VERSION 5.8 ;
BUSBITCHARS "[]" ;
DIVIDERCHAR "/" ;
UNITS
    DATABASE MICRONS 1000 ;
END UNITS

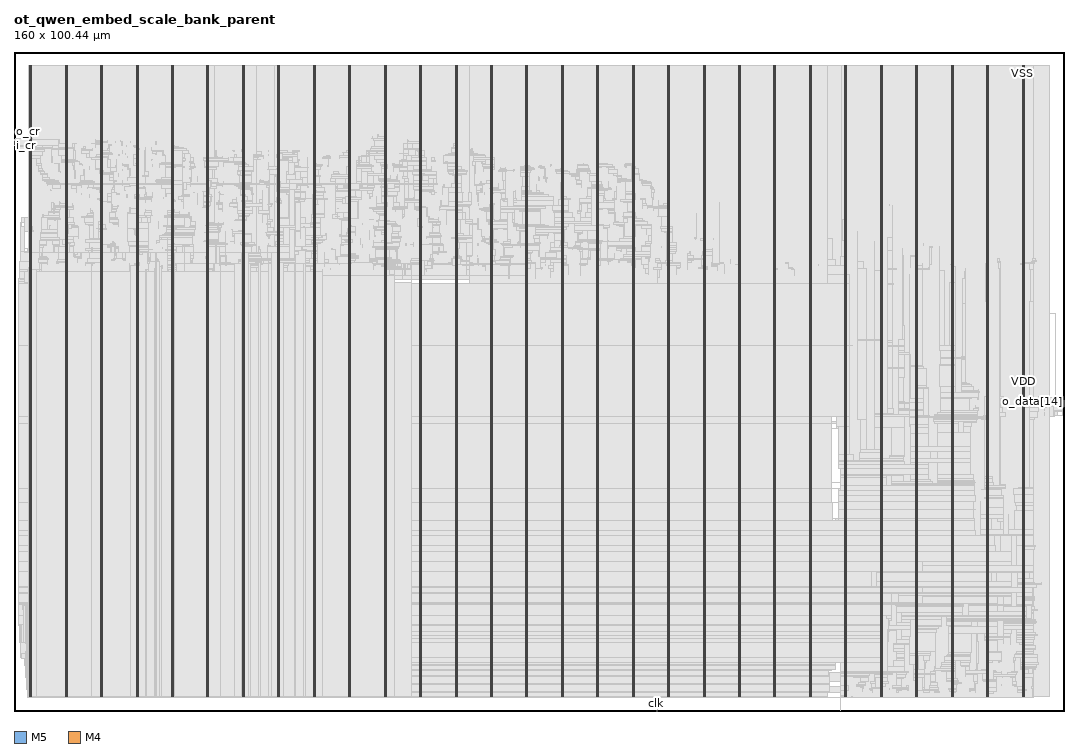
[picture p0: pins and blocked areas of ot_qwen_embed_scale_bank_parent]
MACRO ot_qwen_embed_scale_bank_parent
  FOREIGN ot_qwen_embed_scale_bank_parent 0 0 ;
  CLASS BLOCK ;
  SIZE 160 BY 100.44 ;
  PIN clk
    DIRECTION INPUT ;
    USE SIGNAL ;
    PORT
      LAYER M5 ;
        RECT  97.872 0 97.896 0.084 ;
    END
  END clk
  PIN fault
    DIRECTION OUTPUT ;
    USE SIGNAL ;
    PORT
      LAYER M5 ;
        RECT  97.92 0 97.944 0.084 ;
    END
  END fault
  PIN i_cr
    DIRECTION OUTPUT ;
    USE SIGNAL ;
    PORT
      LAYER M4 ;
        RECT  0 86.112 0.084 86.136 ;
    END
  END i_cr
  PIN i_row[0]
    DIRECTION INPUT ;
    USE SIGNAL ;
    PORT
      LAYER M4 ;
        RECT  0 86.16 0.084 86.184 ;
    END
  END i_row[0]
  PIN i_row[10]
    DIRECTION INPUT ;
    USE SIGNAL ;
    PORT
      LAYER M4 ;
        RECT  0 86.64 0.084 86.664 ;
    END
  END i_row[10]
  PIN i_row[11]
    DIRECTION INPUT ;
    USE SIGNAL ;
    PORT
      LAYER M4 ;
        RECT  0 86.688 0.084 86.712 ;
    END
  END i_row[11]
  PIN i_row[12]
    DIRECTION INPUT ;
    USE SIGNAL ;
    PORT
      LAYER M4 ;
        RECT  0 86.736 0.084 86.76 ;
    END
  END i_row[12]
  PIN i_row[13]
    DIRECTION INPUT ;
    USE SIGNAL ;
    PORT
      LAYER M4 ;
        RECT  0 86.784 0.084 86.808 ;
    END
  END i_row[13]
  PIN i_row[14]
    DIRECTION INPUT ;
    USE SIGNAL ;
    PORT
      LAYER M4 ;
        RECT  0 86.832 0.084 86.856 ;
    END
  END i_row[14]
  PIN i_row[15]
    DIRECTION INPUT ;
    USE SIGNAL ;
    PORT
      LAYER M4 ;
        RECT  0 86.88 0.084 86.904 ;
    END
  END i_row[15]
  PIN i_row[16]
    DIRECTION INPUT ;
    USE SIGNAL ;
    PORT
      LAYER M4 ;
        RECT  0 86.928 0.084 86.952 ;
    END
  END i_row[16]
  PIN i_row[17]
    DIRECTION INPUT ;
    USE SIGNAL ;
    PORT
      LAYER M4 ;
        RECT  0 86.976 0.084 87 ;
    END
  END i_row[17]
  PIN i_row[1]
    DIRECTION INPUT ;
    USE SIGNAL ;
    PORT
      LAYER M4 ;
        RECT  0 86.208 0.084 86.232 ;
    END
  END i_row[1]
  PIN i_row[2]
    DIRECTION INPUT ;
    USE SIGNAL ;
    PORT
      LAYER M4 ;
        RECT  0 86.256 0.084 86.28 ;
    END
  END i_row[2]
  PIN i_row[3]
    DIRECTION INPUT ;
    USE SIGNAL ;
    PORT
      LAYER M4 ;
        RECT  0 86.304 0.084 86.328 ;
    END
  END i_row[3]
  PIN i_row[4]
    DIRECTION INPUT ;
    USE SIGNAL ;
    PORT
      LAYER M4 ;
        RECT  0 86.352 0.084 86.376 ;
    END
  END i_row[4]
  PIN i_row[5]
    DIRECTION INPUT ;
    USE SIGNAL ;
    PORT
      LAYER M4 ;
        RECT  0 86.4 0.084 86.424 ;
    END
  END i_row[5]
  PIN i_row[6]
    DIRECTION INPUT ;
    USE SIGNAL ;
    PORT
      LAYER M4 ;
        RECT  0 86.448 0.084 86.472 ;
    END
  END i_row[6]
  PIN i_row[7]
    DIRECTION INPUT ;
    USE SIGNAL ;
    PORT
      LAYER M4 ;
        RECT  0 86.496 0.084 86.52 ;
    END
  END i_row[7]
  PIN i_row[8]
    DIRECTION INPUT ;
    USE SIGNAL ;
    PORT
      LAYER M4 ;
        RECT  0 86.544 0.084 86.568 ;
    END
  END i_row[8]
  PIN i_row[9]
    DIRECTION INPUT ;
    USE SIGNAL ;
    PORT
      LAYER M4 ;
        RECT  0 86.592 0.084 86.616 ;
    END
  END i_row[9]
  PIN i_v
    DIRECTION INPUT ;
    USE SIGNAL ;
    PORT
      LAYER M4 ;
        RECT  0 87.024 0.084 87.048 ;
    END
  END i_v
  PIN o_cr
    DIRECTION INPUT ;
    USE SIGNAL ;
    PORT
      LAYER M4 ;
        RECT  0 87.072 0.084 87.096 ;
    END
  END o_cr
  PIN o_data[0]
    DIRECTION OUTPUT ;
    USE SIGNAL ;
    PORT
      LAYER M4 ;
        RECT  159.916 46.464 160 46.488 ;
    END
  END o_data[0]
  PIN o_data[10]
    DIRECTION OUTPUT ;
    USE SIGNAL ;
    PORT
      LAYER M4 ;
        RECT  159.916 46.944 160 46.968 ;
    END
  END o_data[10]
  PIN o_data[11]
    DIRECTION OUTPUT ;
    USE SIGNAL ;
    PORT
      LAYER M4 ;
        RECT  159.916 46.992 160 47.016 ;
    END
  END o_data[11]
  PIN o_data[12]
    DIRECTION OUTPUT ;
    USE SIGNAL ;
    PORT
      LAYER M4 ;
        RECT  159.916 47.04 160 47.064 ;
    END
  END o_data[12]
  PIN o_data[13]
    DIRECTION OUTPUT ;
    USE SIGNAL ;
    PORT
      LAYER M4 ;
        RECT  159.916 47.088 160 47.112 ;
    END
  END o_data[13]
  PIN o_data[14]
    DIRECTION OUTPUT ;
    USE SIGNAL ;
    PORT
      LAYER M4 ;
        RECT  159.916 47.136 160 47.16 ;
    END
  END o_data[14]
  PIN o_data[15]
    DIRECTION OUTPUT ;
    USE SIGNAL ;
    PORT
      LAYER M4 ;
        RECT  159.916 47.184 160 47.208 ;
    END
  END o_data[15]
  PIN o_data[1]
    DIRECTION OUTPUT ;
    USE SIGNAL ;
    PORT
      LAYER M4 ;
        RECT  159.916 46.512 160 46.536 ;
    END
  END o_data[1]
  PIN o_data[2]
    DIRECTION OUTPUT ;
    USE SIGNAL ;
    PORT
      LAYER M4 ;
        RECT  159.916 46.56 160 46.584 ;
    END
  END o_data[2]
  PIN o_data[3]
    DIRECTION OUTPUT ;
    USE SIGNAL ;
    PORT
      LAYER M4 ;
        RECT  159.916 46.608 160 46.632 ;
    END
  END o_data[3]
  PIN o_data[4]
    DIRECTION OUTPUT ;
    USE SIGNAL ;
    PORT
      LAYER M4 ;
        RECT  159.916 46.656 160 46.68 ;
    END
  END o_data[4]
  PIN o_data[5]
    DIRECTION OUTPUT ;
    USE SIGNAL ;
    PORT
      LAYER M4 ;
        RECT  159.916 46.704 160 46.728 ;
    END
  END o_data[5]
  PIN o_data[6]
    DIRECTION OUTPUT ;
    USE SIGNAL ;
    PORT
      LAYER M4 ;
        RECT  159.916 46.752 160 46.776 ;
    END
  END o_data[6]
  PIN o_data[7]
    DIRECTION OUTPUT ;
    USE SIGNAL ;
    PORT
      LAYER M4 ;
        RECT  159.916 46.8 160 46.824 ;
    END
  END o_data[7]
  PIN o_data[8]
    DIRECTION OUTPUT ;
    USE SIGNAL ;
    PORT
      LAYER M4 ;
        RECT  159.916 46.848 160 46.872 ;
    END
  END o_data[8]
  PIN o_data[9]
    DIRECTION OUTPUT ;
    USE SIGNAL ;
    PORT
      LAYER M4 ;
        RECT  159.916 46.896 160 46.92 ;
    END
  END o_data[9]
  PIN o_v
    DIRECTION OUTPUT ;
    USE SIGNAL ;
    PORT
      LAYER M4 ;
        RECT  159.916 47.232 160 47.256 ;
    END
  END o_v
  PIN rst_n
    DIRECTION INPUT ;
    USE SIGNAL ;
    PORT
      LAYER M5 ;
        RECT  97.968 0 97.992 0.084 ;
    END
  END rst_n
  PIN VDD
    DIRECTION INOUT ;
    USE POWER ;
    PORT
      LAYER M5 ;
        RECT  153.792 2.151 153.912 98.289 ;
        RECT  148.392 2.151 148.512 98.289 ;
        RECT  142.992 2.151 143.112 98.289 ;
        RECT  137.592 2.151 137.712 98.289 ;
        RECT  132.192 2.151 132.312 98.289 ;
        RECT  126.792 2.151 126.912 98.289 ;
        RECT  121.392 2.151 121.512 98.289 ;
        RECT  115.992 2.151 116.112 98.289 ;
        RECT  110.592 2.151 110.712 98.289 ;
        RECT  105.192 2.151 105.312 98.289 ;
        RECT  99.792 2.151 99.912 98.289 ;
        RECT  94.392 2.151 94.512 98.289 ;
        RECT  88.992 2.151 89.112 98.289 ;
        RECT  83.592 2.151 83.712 98.289 ;
        RECT  78.192 2.151 78.312 98.289 ;
        RECT  72.792 2.151 72.912 98.289 ;
        RECT  67.392 2.151 67.512 98.289 ;
        RECT  61.992 2.151 62.112 98.289 ;
        RECT  56.592 2.151 56.712 98.289 ;
        RECT  51.192 2.151 51.312 98.289 ;
        RECT  45.792 2.151 45.912 98.289 ;
        RECT  40.392 2.151 40.512 98.289 ;
        RECT  34.992 2.151 35.112 98.289 ;
        RECT  29.592 2.151 29.712 98.289 ;
        RECT  24.192 2.151 24.312 98.289 ;
        RECT  18.792 2.151 18.912 98.289 ;
        RECT  13.392 2.151 13.512 98.289 ;
        RECT  7.992 2.151 8.112 98.289 ;
        RECT  2.592 2.151 2.712 98.289 ;
    END
  END VDD
  PIN VSS
    DIRECTION INOUT ;
    USE GROUND ;
    PORT
      LAYER M5 ;
        RECT  153.6 2.137 153.72 98.303 ;
        RECT  148.2 2.137 148.32 98.303 ;
        RECT  142.8 2.137 142.92 98.303 ;
        RECT  137.4 2.137 137.52 98.303 ;
        RECT  132 2.137 132.12 98.303 ;
        RECT  126.6 2.137 126.72 98.303 ;
        RECT  121.2 2.151 121.32 98.303 ;
        RECT  115.8 2.151 115.92 98.303 ;
        RECT  110.4 2.151 110.52 98.303 ;
        RECT  105 2.151 105.12 98.303 ;
        RECT  99.6 2.151 99.72 98.303 ;
        RECT  94.2 2.151 94.32 98.303 ;
        RECT  88.8 2.151 88.92 98.303 ;
        RECT  83.4 2.151 83.52 98.303 ;
        RECT  78 2.151 78.12 98.303 ;
        RECT  72.6 2.151 72.72 98.303 ;
        RECT  67.2 2.151 67.32 98.303 ;
        RECT  61.8 2.151 61.92 98.303 ;
        RECT  56.4 2.151 56.52 98.303 ;
        RECT  51 2.151 51.12 98.303 ;
        RECT  45.6 2.151 45.72 98.303 ;
        RECT  40.2 2.151 40.32 98.303 ;
        RECT  34.8 2.151 34.92 98.303 ;
        RECT  29.4 2.151 29.52 98.303 ;
        RECT  24 2.151 24.12 98.303 ;
        RECT  18.6 2.151 18.72 98.303 ;
        RECT  13.2 2.151 13.32 98.303 ;
        RECT  7.8 2.151 7.92 98.303 ;
        RECT  2.4 2.151 2.52 98.303 ;
    END
  END VSS
  OBS
    LAYER RVTN ;
     RECT  126.036 2.16 157.788 2.295 ;
     RECT  126.036 2.565 157.788 2.835 ;
     RECT  126.036 3.105 157.788 3.375 ;
     RECT  126.036 3.645 157.788 3.915 ;
     RECT  126.036 4.185 157.788 4.455 ;
     RECT  126.036 4.725 157.788 4.995 ;
     RECT  126.036 5.265 157.788 5.535 ;
     RECT  126.036 5.805 157.788 6.075 ;
     RECT  126.036 6.345 157.788 6.615 ;
     RECT  126.036 6.885 157.788 7.155 ;
     RECT  126.036 7.425 157.788 7.695 ;
     RECT  126.036 7.965 157.788 8.235 ;
     RECT  126.036 8.505 157.788 8.775 ;
     RECT  126.036 9.045 157.788 9.315 ;
     RECT  126.036 9.585 157.788 9.855 ;
     RECT  126.036 10.125 157.788 10.395 ;
     RECT  126.036 10.665 157.788 10.935 ;
     RECT  126.036 11.205 157.788 11.475 ;
     RECT  126.036 11.745 157.788 12.015 ;
     RECT  126.036 12.285 157.788 12.555 ;
     RECT  126.036 12.825 157.788 13.095 ;
     RECT  126.036 13.365 157.788 13.635 ;
     RECT  126.036 13.905 157.788 14.175 ;
     RECT  126.036 14.445 157.788 14.715 ;
     RECT  126.036 14.985 157.788 15.255 ;
     RECT  126.036 15.525 157.788 15.795 ;
     RECT  126.036 16.065 157.788 16.335 ;
     RECT  126.036 16.605 157.788 16.875 ;
     RECT  126.036 17.145 157.788 17.415 ;
     RECT  126.036 17.685 157.788 17.955 ;
     RECT  126.036 18.225 157.788 18.495 ;
     RECT  126.036 18.765 157.788 19.035 ;
     RECT  126.036 19.305 157.788 19.575 ;
     RECT  126.036 19.845 157.788 20.115 ;
     RECT  126.036 20.385 157.788 20.655 ;
     RECT  126.036 20.925 157.788 21.195 ;
     RECT  126.036 21.465 157.788 21.735 ;
     RECT  126.036 22.005 157.788 22.275 ;
     RECT  126.036 22.545 157.788 22.815 ;
     RECT  126.036 23.085 157.788 23.355 ;
     RECT  126.036 23.625 157.788 23.895 ;
     RECT  126.036 24.165 157.788 24.435 ;
     RECT  126.036 24.705 157.788 24.975 ;
     RECT  126.036 25.245 157.788 25.515 ;
     RECT  126.036 25.785 157.788 26.055 ;
     RECT  126.036 26.325 157.788 26.595 ;
     RECT  126.036 26.865 157.788 27.135 ;
     RECT  126.036 27.405 157.788 27.675 ;
     RECT  126.036 27.945 157.788 28.215 ;
     RECT  126.036 28.485 157.788 28.755 ;
     RECT  126.036 29.025 157.788 29.295 ;
     RECT  126.036 29.565 157.788 29.835 ;
     RECT  126.036 30.105 157.788 30.375 ;
     RECT  126.036 30.645 157.788 30.915 ;
     RECT  126.036 31.185 157.788 31.455 ;
     RECT  126.036 31.725 157.788 31.995 ;
     RECT  126.036 32.265 157.788 32.535 ;
     RECT  126.036 32.805 157.788 33.075 ;
     RECT  126.036 33.345 157.788 33.615 ;
     RECT  126.036 33.885 157.788 34.155 ;
     RECT  126.036 34.425 157.788 34.695 ;
     RECT  126.036 34.965 157.788 35.235 ;
     RECT  126.036 35.505 157.788 35.775 ;
     RECT  126.036 36.045 157.788 36.315 ;
     RECT  126.036 36.585 157.788 36.855 ;
     RECT  126.036 37.125 157.788 37.395 ;
     RECT  126.036 37.665 157.788 37.935 ;
     RECT  126.036 38.205 157.788 38.475 ;
     RECT  126.036 38.745 157.788 39.015 ;
     RECT  126.036 39.285 157.788 39.555 ;
     RECT  126.036 39.825 157.788 40.095 ;
     RECT  126.036 40.365 157.788 40.635 ;
     RECT  126.036 40.905 157.788 41.175 ;
     RECT  126.036 41.445 157.788 41.715 ;
     RECT  126.036 41.985 157.788 42.255 ;
     RECT  126.036 42.525 157.788 42.795 ;
     RECT  126.036 43.065 157.788 43.335 ;
     RECT  126.036 43.605 157.788 43.875 ;
     RECT  126.036 44.145 157.788 44.415 ;
     RECT  126.036 44.685 157.788 44.955 ;
     RECT  126.036 45.225 157.788 45.495 ;
     RECT  126.036 45.765 157.788 46.035 ;
     RECT  126.036 46.305 157.788 46.575 ;
     RECT  126.036 46.845 157.788 47.115 ;
     RECT  126.036 47.385 157.788 47.655 ;
     RECT  126.036 47.925 157.788 48.195 ;
     RECT  126.036 48.465 157.788 48.735 ;
     RECT  126.036 49.005 157.788 49.275 ;
     RECT  126.036 49.545 157.788 49.815 ;
     RECT  126.036 50.085 157.788 50.355 ;
     RECT  126.036 50.625 157.788 50.895 ;
     RECT  126.036 51.165 157.788 51.435 ;
     RECT  126.036 51.705 157.788 51.975 ;
     RECT  126.036 52.245 157.788 52.515 ;
     RECT  126.036 52.785 157.788 53.055 ;
     RECT  126.036 53.325 157.788 53.595 ;
     RECT  126.036 53.865 157.788 54.135 ;
     RECT  126.036 54.405 157.788 54.675 ;
     RECT  126.036 54.945 157.788 55.215 ;
     RECT  126.036 55.485 157.788 55.755 ;
     RECT  126.036 56.025 157.788 56.295 ;
     RECT  126.036 56.565 157.788 56.835 ;
     RECT  126.036 57.105 157.788 57.375 ;
     RECT  126.036 57.645 157.788 57.915 ;
     RECT  126.036 58.185 157.788 58.455 ;
     RECT  126.036 58.725 157.788 58.995 ;
     RECT  126.036 59.265 157.788 59.535 ;
     RECT  126.036 59.805 157.788 60.075 ;
     RECT  126.036 60.345 157.788 60.615 ;
     RECT  126.036 60.885 157.788 61.155 ;
     RECT  126.036 61.425 157.788 61.695 ;
     RECT  126.036 61.965 157.788 62.235 ;
     RECT  126.036 62.505 157.788 62.775 ;
     RECT  126.036 63.045 157.788 63.315 ;
     RECT  126.036 63.585 157.788 63.855 ;
     RECT  126.036 64.125 157.788 64.395 ;
     RECT  126.036 64.665 157.788 64.935 ;
     RECT  126.036 65.205 157.788 65.475 ;
     RECT  126.036 65.745 157.788 66.015 ;
     RECT  126.036 66.285 157.788 66.555 ;
     RECT  126.036 66.825 157.788 67.095 ;
     RECT  2.16 67.365 157.788 67.635 ;
     RECT  2.16 67.905 157.788 68.175 ;
     RECT  2.16 68.445 157.788 68.715 ;
     RECT  2.16 68.985 157.788 69.255 ;
     RECT  2.16 69.525 157.788 69.795 ;
     RECT  2.16 70.065 157.788 70.335 ;
     RECT  2.16 70.605 157.788 70.875 ;
     RECT  2.16 71.145 157.788 71.415 ;
     RECT  2.16 71.685 157.788 71.955 ;
     RECT  2.16 72.225 157.788 72.495 ;
     RECT  2.16 72.765 157.788 73.035 ;
     RECT  2.16 73.305 157.788 73.575 ;
     RECT  2.16 73.845 157.788 74.115 ;
     RECT  2.16 74.385 157.788 74.655 ;
     RECT  2.16 74.925 157.788 75.195 ;
     RECT  2.16 75.465 157.788 75.735 ;
     RECT  2.16 76.005 157.788 76.275 ;
     RECT  2.16 76.545 157.788 76.815 ;
     RECT  2.16 77.085 157.788 77.355 ;
     RECT  2.16 77.625 157.788 77.895 ;
     RECT  2.16 78.165 157.788 78.435 ;
     RECT  2.16 78.705 157.788 78.975 ;
     RECT  2.16 79.245 157.788 79.515 ;
     RECT  2.16 79.785 157.788 80.055 ;
     RECT  2.16 80.325 157.788 80.595 ;
     RECT  2.16 80.865 157.788 81.135 ;
     RECT  2.16 81.405 157.788 81.675 ;
     RECT  2.16 81.945 157.788 82.215 ;
     RECT  2.16 82.485 157.788 82.755 ;
     RECT  2.16 83.025 157.788 83.295 ;
     RECT  2.16 83.565 157.788 83.835 ;
     RECT  2.16 84.105 157.788 84.375 ;
     RECT  2.16 84.645 157.788 84.915 ;
     RECT  2.16 85.185 157.788 85.455 ;
     RECT  2.16 85.725 157.788 85.995 ;
     RECT  2.16 86.265 157.788 86.535 ;
     RECT  2.16 86.805 157.788 87.075 ;
     RECT  2.16 87.345 157.788 87.615 ;
     RECT  2.16 87.885 157.788 88.155 ;
     RECT  2.16 88.425 157.788 88.695 ;
     RECT  2.16 88.965 157.788 89.235 ;
     RECT  2.16 89.505 157.788 89.775 ;
     RECT  2.16 90.045 157.788 90.315 ;
     RECT  2.16 90.585 157.788 90.855 ;
     RECT  2.16 91.125 157.788 91.395 ;
     RECT  2.16 91.665 157.788 91.935 ;
     RECT  2.16 92.205 157.788 92.475 ;
     RECT  2.16 92.745 157.788 93.015 ;
     RECT  2.16 93.285 157.788 93.555 ;
     RECT  2.16 93.825 157.788 94.095 ;
     RECT  2.16 94.365 157.788 94.635 ;
     RECT  2.16 94.905 157.788 95.175 ;
     RECT  2.16 95.445 157.788 95.715 ;
     RECT  2.16 95.985 157.788 96.255 ;
     RECT  2.16 96.525 157.788 96.795 ;
     RECT  2.16 97.065 157.788 97.335 ;
     RECT  2.16 97.605 157.788 97.875 ;
     RECT  2.16 98.145 157.788 98.28 ;
    LAYER RVTP ;
     RECT  126.036 2.295 157.788 2.565 ;
     RECT  126.036 2.835 157.788 3.105 ;
     RECT  126.036 3.375 157.788 3.645 ;
     RECT  126.036 3.915 157.788 4.185 ;
     RECT  126.036 4.455 157.788 4.725 ;
     RECT  126.036 4.995 157.788 5.265 ;
     RECT  126.036 5.535 157.788 5.805 ;
     RECT  126.036 6.075 157.788 6.345 ;
     RECT  126.036 6.615 157.788 6.885 ;
     RECT  126.036 7.155 157.788 7.425 ;
     RECT  126.036 7.695 157.788 7.965 ;
     RECT  126.036 8.235 157.788 8.505 ;
     RECT  126.036 8.775 157.788 9.045 ;
     RECT  126.036 9.315 157.788 9.585 ;
     RECT  126.036 9.855 157.788 10.125 ;
     RECT  126.036 10.395 157.788 10.665 ;
     RECT  126.036 10.935 157.788 11.205 ;
     RECT  126.036 11.475 157.788 11.745 ;
     RECT  126.036 12.015 157.788 12.285 ;
     RECT  126.036 12.555 157.788 12.825 ;
     RECT  126.036 13.095 157.788 13.365 ;
     RECT  126.036 13.635 157.788 13.905 ;
     RECT  126.036 14.175 157.788 14.445 ;
     RECT  126.036 14.715 157.788 14.985 ;
     RECT  126.036 15.255 157.788 15.525 ;
     RECT  126.036 15.795 157.788 16.065 ;
     RECT  126.036 16.335 157.788 16.605 ;
     RECT  126.036 16.875 157.788 17.145 ;
     RECT  126.036 17.415 157.788 17.685 ;
     RECT  126.036 17.955 157.788 18.225 ;
     RECT  126.036 18.495 157.788 18.765 ;
     RECT  126.036 19.035 157.788 19.305 ;
     RECT  126.036 19.575 157.788 19.845 ;
     RECT  126.036 20.115 157.788 20.385 ;
     RECT  126.036 20.655 157.788 20.925 ;
     RECT  126.036 21.195 157.788 21.465 ;
     RECT  126.036 21.735 157.788 22.005 ;
     RECT  126.036 22.275 157.788 22.545 ;
     RECT  126.036 22.815 157.788 23.085 ;
     RECT  126.036 23.355 157.788 23.625 ;
     RECT  126.036 23.895 157.788 24.165 ;
     RECT  126.036 24.435 157.788 24.705 ;
     RECT  126.036 24.975 157.788 25.245 ;
     RECT  126.036 25.515 157.788 25.785 ;
     RECT  126.036 26.055 157.788 26.325 ;
     RECT  126.036 26.595 157.788 26.865 ;
     RECT  126.036 27.135 157.788 27.405 ;
     RECT  126.036 27.675 157.788 27.945 ;
     RECT  126.036 28.215 157.788 28.485 ;
     RECT  126.036 28.755 157.788 29.025 ;
     RECT  126.036 29.295 157.788 29.565 ;
     RECT  126.036 29.835 157.788 30.105 ;
     RECT  126.036 30.375 157.788 30.645 ;
     RECT  126.036 30.915 157.788 31.185 ;
     RECT  126.036 31.455 157.788 31.725 ;
     RECT  126.036 31.995 157.788 32.265 ;
     RECT  126.036 32.535 157.788 32.805 ;
     RECT  126.036 33.075 157.788 33.345 ;
     RECT  126.036 33.615 157.788 33.885 ;
     RECT  126.036 34.155 157.788 34.425 ;
     RECT  126.036 34.695 157.788 34.965 ;
     RECT  126.036 35.235 157.788 35.505 ;
     RECT  126.036 35.775 157.788 36.045 ;
     RECT  126.036 36.315 157.788 36.585 ;
     RECT  126.036 36.855 157.788 37.125 ;
     RECT  126.036 37.395 157.788 37.665 ;
     RECT  126.036 37.935 157.788 38.205 ;
     RECT  126.036 38.475 157.788 38.745 ;
     RECT  126.036 39.015 157.788 39.285 ;
     RECT  126.036 39.555 157.788 39.825 ;
     RECT  126.036 40.095 157.788 40.365 ;
     RECT  126.036 40.635 157.788 40.905 ;
     RECT  126.036 41.175 157.788 41.445 ;
     RECT  126.036 41.715 157.788 41.985 ;
     RECT  126.036 42.255 157.788 42.525 ;
     RECT  126.036 42.795 157.788 43.065 ;
     RECT  126.036 43.335 157.788 43.605 ;
     RECT  126.036 43.875 157.788 44.145 ;
     RECT  126.036 44.415 157.788 44.685 ;
     RECT  126.036 44.955 157.788 45.225 ;
     RECT  126.036 45.495 157.788 45.765 ;
     RECT  126.036 46.035 157.788 46.305 ;
     RECT  126.036 46.575 157.788 46.845 ;
     RECT  126.036 47.115 157.788 47.385 ;
     RECT  126.036 47.655 157.788 47.925 ;
     RECT  126.036 48.195 157.788 48.465 ;
     RECT  126.036 48.735 157.788 49.005 ;
     RECT  126.036 49.275 157.788 49.545 ;
     RECT  126.036 49.815 157.788 50.085 ;
     RECT  126.036 50.355 157.788 50.625 ;
     RECT  126.036 50.895 157.788 51.165 ;
     RECT  126.036 51.435 157.788 51.705 ;
     RECT  126.036 51.975 157.788 52.245 ;
     RECT  126.036 52.515 157.788 52.785 ;
     RECT  126.036 53.055 157.788 53.325 ;
     RECT  126.036 53.595 157.788 53.865 ;
     RECT  126.036 54.135 157.788 54.405 ;
     RECT  126.036 54.675 157.788 54.945 ;
     RECT  126.036 55.215 157.788 55.485 ;
     RECT  126.036 55.755 157.788 56.025 ;
     RECT  126.036 56.295 157.788 56.565 ;
     RECT  126.036 56.835 157.788 57.105 ;
     RECT  126.036 57.375 157.788 57.645 ;
     RECT  126.036 57.915 157.788 58.185 ;
     RECT  126.036 58.455 157.788 58.725 ;
     RECT  126.036 58.995 157.788 59.265 ;
     RECT  126.036 59.535 157.788 59.805 ;
     RECT  126.036 60.075 157.788 60.345 ;
     RECT  126.036 60.615 157.788 60.885 ;
     RECT  126.036 61.155 157.788 61.425 ;
     RECT  126.036 61.695 157.788 61.965 ;
     RECT  126.036 62.235 157.788 62.505 ;
     RECT  126.036 62.775 157.788 63.045 ;
     RECT  126.036 63.315 157.788 63.585 ;
     RECT  126.036 63.855 157.788 64.125 ;
     RECT  126.036 64.395 157.788 64.665 ;
     RECT  126.036 64.935 157.788 65.205 ;
     RECT  126.036 65.475 157.788 65.745 ;
     RECT  126.036 66.015 157.788 66.285 ;
     RECT  126.036 66.555 157.788 66.825 ;
     RECT  126.036 67.095 157.788 67.23 ;
     RECT  2.16 67.23 157.788 67.365 ;
     RECT  2.16 67.635 157.788 67.905 ;
     RECT  2.16 68.175 157.788 68.445 ;
     RECT  2.16 68.715 157.788 68.985 ;
     RECT  2.16 69.255 157.788 69.525 ;
     RECT  2.16 69.795 157.788 70.065 ;
     RECT  2.16 70.335 157.788 70.605 ;
     RECT  2.16 70.875 157.788 71.145 ;
     RECT  2.16 71.415 157.788 71.685 ;
     RECT  2.16 71.955 157.788 72.225 ;
     RECT  2.16 72.495 157.788 72.765 ;
     RECT  2.16 73.035 157.788 73.305 ;
     RECT  2.16 73.575 157.788 73.845 ;
     RECT  2.16 74.115 157.788 74.385 ;
     RECT  2.16 74.655 157.788 74.925 ;
     RECT  2.16 75.195 157.788 75.465 ;
     RECT  2.16 75.735 157.788 76.005 ;
     RECT  2.16 76.275 157.788 76.545 ;
     RECT  2.16 76.815 157.788 77.085 ;
     RECT  2.16 77.355 157.788 77.625 ;
     RECT  2.16 77.895 157.788 78.165 ;
     RECT  2.16 78.435 157.788 78.705 ;
     RECT  2.16 78.975 157.788 79.245 ;
     RECT  2.16 79.515 157.788 79.785 ;
     RECT  2.16 80.055 157.788 80.325 ;
     RECT  2.16 80.595 157.788 80.865 ;
     RECT  2.16 81.135 157.788 81.405 ;
     RECT  2.16 81.675 157.788 81.945 ;
     RECT  2.16 82.215 157.788 82.485 ;
     RECT  2.16 82.755 157.788 83.025 ;
     RECT  2.16 83.295 157.788 83.565 ;
     RECT  2.16 83.835 157.788 84.105 ;
     RECT  2.16 84.375 157.788 84.645 ;
     RECT  2.16 84.915 157.788 85.185 ;
     RECT  2.16 85.455 157.788 85.725 ;
     RECT  2.16 85.995 157.788 86.265 ;
     RECT  2.16 86.535 157.788 86.805 ;
     RECT  2.16 87.075 157.788 87.345 ;
     RECT  2.16 87.615 157.788 87.885 ;
     RECT  2.16 88.155 157.788 88.425 ;
     RECT  2.16 88.695 157.788 88.965 ;
     RECT  2.16 89.235 157.788 89.505 ;
     RECT  2.16 89.775 157.788 90.045 ;
     RECT  2.16 90.315 157.788 90.585 ;
     RECT  2.16 90.855 157.788 91.125 ;
     RECT  2.16 91.395 157.788 91.665 ;
     RECT  2.16 91.935 157.788 92.205 ;
     RECT  2.16 92.475 157.788 92.745 ;
     RECT  2.16 93.015 157.788 93.285 ;
     RECT  2.16 93.555 157.788 93.825 ;
     RECT  2.16 94.095 157.788 94.365 ;
     RECT  2.16 94.635 157.788 94.905 ;
     RECT  2.16 95.175 157.788 95.445 ;
     RECT  2.16 95.715 157.788 95.985 ;
     RECT  2.16 96.255 157.788 96.525 ;
     RECT  2.16 96.795 157.788 97.065 ;
     RECT  2.16 97.335 157.788 97.605 ;
     RECT  2.16 97.875 157.788 98.145 ;
    LAYER M1 ;
     RECT  2.16 2.16 123.984 65.07 ;
     RECT  126.036 2.151 157.788 67.221 ;
     RECT  2.16 67.221 157.788 98.289 ;
    LAYER M2 ;
     RECT  0.175 86.85 0.347 86.868 ;
     RECT  0.175 85.536 0.499 85.554 ;
     RECT  0.715 65.376 0.751 65.394 ;
     RECT  0.751 65.376 0.931 65.934 ;
     RECT  0.859 66.951 0.931 66.969 ;
     RECT  1.003 73.044 1.075 73.062 ;
     RECT  0.967 74.43 1.111 74.448 ;
     RECT  0.931 65.376 1.291 66.969 ;
     RECT  1.291 65.25 1.435 66.969 ;
     RECT  1.435 65.25 1.507 67.014 ;
     RECT  1.075 73.044 1.615 73.134 ;
     RECT  1.111 74.43 1.615 75.186 ;
     RECT  1.039 70.416 2.011 70.434 ;
     RECT  0.895 68.454 2.047 68.472 ;
     RECT  2.047 68.454 2.083 69.048 ;
     RECT  2.083 2.106 2.16 2.124 ;
     RECT  1.507 65.25 2.16 67.05 ;
     RECT  2.083 68.454 2.16 69.246 ;
     RECT  2.011 70.038 2.16 70.434 ;
     RECT  1.615 73.044 2.16 75.186 ;
     RECT  0.499 85.536 2.16 85.986 ;
     RECT  1.687 86.85 2.16 86.868 ;
     RECT  2.16 2.106 30.479 98.289 ;
     RECT  30.479 2.106 35.699 65.349 ;
     RECT  35.699 2.106 36.895 65.304 ;
     RECT  30.479 66.366 36.895 98.289 ;
     RECT  36.895 2.106 39.623 98.289 ;
     RECT  39.623 2.106 69.403 65.07 ;
     RECT  39.623 65.826 69.403 98.289 ;
     RECT  69.403 2.106 123.984 98.289 ;
     RECT  123.984 2.88 124.223 5.832 ;
     RECT  123.984 11.754 124.259 12.816 ;
     RECT  124.259 11.754 124.295 11.772 ;
     RECT  123.984 9.396 124.655 9.504 ;
     RECT  125.095 27.108 125.131 27.126 ;
     RECT  123.984 52.218 125.131 52.236 ;
     RECT  123.984 29.268 125.167 29.286 ;
     RECT  123.984 16.308 125.239 16.326 ;
     RECT  125.203 17.154 125.239 17.172 ;
     RECT  125.167 55.998 125.239 56.016 ;
     RECT  125.167 11.016 125.303 11.124 ;
     RECT  123.984 43.038 125.347 43.056 ;
     RECT  123.984 43.848 125.347 44.136 ;
     RECT  123.984 33.894 125.671 33.912 ;
     RECT  125.167 29.034 125.707 29.286 ;
     RECT  123.984 20.394 125.779 20.412 ;
     RECT  123.984 2.106 126.036 2.124 ;
     RECT  124.223 2.88 126.036 3.708 ;
     RECT  124.223 4.464 126.036 5.832 ;
     RECT  126.031 8.514 126.036 8.532 ;
     RECT  124.655 9.396 126.036 9.414 ;
     RECT  125.303 11.016 126.036 11.034 ;
     RECT  124.259 12.798 126.036 12.816 ;
     RECT  125.239 16.308 126.036 17.172 ;
     RECT  125.779 20.16 126.036 20.412 ;
     RECT  125.743 21.168 126.036 21.186 ;
     RECT  123.984 22.896 126.036 23.454 ;
     RECT  125.815 25.326 126.036 25.344 ;
     RECT  125.131 27.108 126.036 27.666 ;
     RECT  125.707 28.494 126.036 29.286 ;
     RECT  123.984 31.734 126.036 31.752 ;
     RECT  125.671 33.588 126.036 33.912 ;
     RECT  123.984 34.776 126.036 34.794 ;
     RECT  125.671 36.936 126.036 36.954 ;
     RECT  125.347 43.038 126.036 44.136 ;
     RECT  123.984 44.928 126.036 44.946 ;
     RECT  125.095 46.008 126.036 46.026 ;
     RECT  123.984 50.328 126.036 50.346 ;
     RECT  125.131 52.218 126.036 52.506 ;
     RECT  125.239 55.998 126.036 56.556 ;
     RECT  124.735 61.056 126.036 61.074 ;
     RECT  123.984 65.25 126.036 98.289 ;
     RECT  126.036 2.106 155.291 98.289 ;
     RECT  155.291 2.151 157.788 98.289 ;
     RECT  157.788 44.928 158.459 47.844 ;
     RECT  158.459 44.928 158.495 47.682 ;
     RECT  158.495 44.928 158.531 45.594 ;
     RECT  157.788 60.516 158.747 60.534 ;
     RECT  158.495 46.548 158.963 47.682 ;
     RECT  158.963 46.548 158.999 47.574 ;
     RECT  158.531 45 159.071 45.594 ;
     RECT  158.999 46.548 159.071 47.304 ;
     RECT  159.071 45 159.755 45.018 ;
     RECT  159.071 47.286 159.827 47.304 ;
    LAYER M3 ;
     RECT  97.992 0.043 98.01 0.173 ;
     RECT  125.964 0.043 125.982 2.059 ;
     RECT  125.964 2.059 126.198 2.143 ;
     RECT  2.088 2.101 2.106 2.16 ;
     RECT  127.692 2.191 127.71 2.237 ;
     RECT  125.964 2.143 126.705 2.413 ;
     RECT  132.015 2.143 132.105 2.413 ;
     RECT  137.415 2.143 137.505 2.413 ;
     RECT  142.815 2.143 142.905 2.413 ;
     RECT  148.215 2.143 148.305 2.413 ;
     RECT  153.615 2.143 153.705 2.413 ;
     RECT  148.215 2.413 148.497 2.605 ;
     RECT  148.215 2.605 149.202 2.641 ;
     RECT  153.615 2.413 153.897 2.767 ;
     RECT  142.815 2.413 143.097 2.839 ;
     RECT  2.088 2.16 123.984 2.875 ;
     RECT  134.64 2.839 134.658 2.875 ;
     RECT  138.636 2.839 138.726 2.875 ;
     RECT  140.328 2.839 140.346 2.875 ;
     RECT  153.072 2.767 153.897 2.875 ;
     RECT  2.088 2.875 124.146 2.911 ;
     RECT  142.815 2.839 143.442 2.911 ;
     RECT  148.215 2.641 149.274 2.911 ;
     RECT  148.176 2.911 149.598 3.001 ;
     RECT  140.328 2.875 140.994 3.005 ;
     RECT  145.548 2.911 145.566 3.019 ;
     RECT  125.964 2.413 126.897 3.065 ;
     RECT  130.752 2.875 130.842 3.067 ;
     RECT  137.415 2.413 137.697 3.067 ;
     RECT  138.636 2.875 139.446 3.067 ;
     RECT  137.415 3.067 139.446 3.073 ;
     RECT  140.328 3.005 140.922 3.073 ;
     RECT  126 3.065 126.897 3.109 ;
     RECT  150.48 3.073 150.498 3.137 ;
     RECT  126 3.109 127.062 3.145 ;
     RECT  134.532 2.875 134.73 3.145 ;
     RECT  137.415 3.073 140.922 3.173 ;
     RECT  130.536 3.067 130.842 3.181 ;
     RECT  134.532 3.145 135.054 3.181 ;
     RECT  145.548 3.019 145.746 3.181 ;
     RECT  146.484 2.875 146.502 3.181 ;
     RECT  152.892 2.875 153.897 3.181 ;
     RECT  145.548 3.181 146.538 3.299 ;
     RECT  152.892 3.181 154.314 3.299 ;
     RECT  129.24 3.037 129.258 3.307 ;
     RECT  130.464 3.181 130.842 3.307 ;
     RECT  134.532 3.181 135.198 3.307 ;
     RECT  136.224 3.181 136.242 3.307 ;
     RECT  145.62 3.299 146.538 3.307 ;
     RECT  138.492 3.173 140.886 3.335 ;
     RECT  152.892 3.299 154.17 3.341 ;
     RECT  142.524 2.911 143.694 3.343 ;
     RECT  130.32 3.307 130.842 3.389 ;
     RECT  133.38 3.307 133.398 3.389 ;
     RECT  142.416 3.343 143.694 3.389 ;
     RECT  145.62 3.307 146.574 3.407 ;
     RECT  134.532 3.307 136.242 3.415 ;
     RECT  129.24 3.307 129.33 3.451 ;
     RECT  130.68 3.389 130.842 3.451 ;
     RECT  132.015 2.413 132.297 3.451 ;
     RECT  155.268 2.101 155.286 3.451 ;
     RECT  129.24 3.451 129.51 3.541 ;
     RECT  133.848 3.415 136.242 3.569 ;
     RECT  138.492 3.335 138.762 3.569 ;
     RECT  139.536 3.335 140.886 3.569 ;
     RECT  139.536 3.569 140.814 3.605 ;
     RECT  146.304 3.407 146.574 3.605 ;
     RECT  148.176 3.001 149.67 3.605 ;
     RECT  130.68 3.451 132.297 3.641 ;
     RECT  132.015 3.641 132.297 3.685 ;
     RECT  152.892 3.341 153.897 3.685 ;
     RECT  155.088 3.451 155.286 3.713 ;
     RECT  128.916 3.541 129.51 3.721 ;
     RECT  152.46 3.685 153.897 3.749 ;
     RECT  128.34 3.721 129.51 3.811 ;
     RECT  135.936 3.569 136.242 3.839 ;
     RECT  139.536 3.605 140.742 3.869 ;
     RECT  126 3.145 127.134 3.875 ;
     RECT  133.848 3.569 135.162 3.875 ;
     RECT  136.224 3.839 136.242 3.875 ;
     RECT  139.536 3.869 140.706 3.875 ;
     RECT  152.46 3.749 152.694 3.883 ;
     RECT  2.088 2.911 124.254 3.979 ;
     RECT  128.34 3.811 129.69 3.983 ;
     RECT  150.444 3.883 150.462 3.983 ;
     RECT  152.208 3.883 152.694 3.991 ;
     RECT  142.815 3.389 143.694 4.075 ;
     RECT  130.68 3.641 131.202 4.123 ;
     RECT  132.015 3.685 132.75 4.123 ;
     RECT  2.052 3.979 124.254 4.157 ;
     RECT  142.815 4.075 143.802 4.189 ;
     RECT  146.376 3.605 146.574 4.261 ;
     RECT  128.628 3.983 129.69 4.301 ;
     RECT  139.644 3.875 140.706 4.379 ;
     RECT  142.815 4.189 144.306 4.379 ;
     RECT  142.815 4.379 144.162 4.415 ;
     RECT  146.376 4.261 146.754 4.423 ;
     RECT  152.172 3.991 152.694 4.451 ;
     RECT  130.536 4.123 131.202 4.493 ;
     RECT  132.015 4.123 133.218 4.493 ;
     RECT  128.916 4.301 129.69 4.495 ;
     RECT  142.815 4.415 143.874 4.495 ;
     RECT  148.215 3.605 149.67 4.507 ;
     RECT  139.644 4.379 140.49 4.523 ;
     RECT  142.092 4.495 143.874 4.649 ;
     RECT  147.78 4.507 149.67 4.657 ;
     RECT  137.415 3.173 137.697 4.699 ;
     RECT  147.636 4.657 149.67 4.757 ;
     RECT  131.148 4.493 131.202 4.843 ;
     RECT  142.092 4.649 143.766 4.919 ;
     RECT  142.092 4.919 143.622 4.955 ;
     RECT  134.532 3.875 135.162 4.987 ;
     RECT  128.916 4.495 130.266 5.035 ;
     RECT  131.148 4.843 131.238 5.071 ;
     RECT  132.015 4.493 133.11 5.071 ;
     RECT  153.615 3.749 153.897 5.071 ;
     RECT  155.268 3.713 155.286 5.071 ;
     RECT  128.268 5.035 130.266 5.161 ;
     RECT  134.532 4.987 135.486 5.161 ;
     RECT  137.052 4.699 137.697 5.161 ;
     RECT  138.492 3.569 138.726 5.161 ;
     RECT  152.172 4.451 152.622 5.161 ;
     RECT  151.812 5.161 152.622 5.197 ;
     RECT  126 3.875 126.897 5.227 ;
     RECT  127.944 5.161 130.266 5.227 ;
     RECT  149.292 4.757 149.67 5.233 ;
     RECT  150.588 5.161 150.606 5.233 ;
     RECT  149.292 5.233 150.606 5.305 ;
     RECT  151.704 5.197 152.622 5.305 ;
     RECT  2.088 4.157 124.254 5.323 ;
     RECT  126 5.227 130.266 5.431 ;
     RECT  1.692 5.323 124.254 5.453 ;
     RECT  131.148 5.071 133.11 5.503 ;
     RECT  149.292 5.305 152.622 5.531 ;
     RECT  137.052 5.161 138.726 5.575 ;
     RECT  139.644 4.523 140.454 5.575 ;
     RECT  149.292 5.531 150.57 5.603 ;
     RECT  134.532 5.161 135.918 5.611 ;
     RECT  145.044 5.233 145.062 5.611 ;
     RECT  146.16 4.423 146.754 5.611 ;
     RECT  151.416 5.531 152.622 5.611 ;
     RECT  126 5.431 130.41 5.707 ;
     RECT  131.148 5.503 133.794 5.707 ;
     RECT  137.052 5.575 140.454 5.729 ;
     RECT  153.615 5.071 155.358 5.729 ;
     RECT  145.044 5.611 146.754 5.773 ;
     RECT  147.636 4.757 148.497 5.773 ;
     RECT  126 5.707 133.794 5.803 ;
     RECT  134.532 5.611 136.026 5.803 ;
     RECT  151.416 5.611 152.766 5.873 ;
     RECT  126 5.803 136.026 5.881 ;
     RECT  152.028 5.873 152.766 5.881 ;
     RECT  149.292 5.603 150.534 5.909 ;
     RECT  142.092 4.955 143.514 5.995 ;
     RECT  149.292 5.909 149.778 5.999 ;
     RECT  150.516 5.909 150.534 5.999 ;
     RECT  126 5.881 136.242 6.035 ;
     RECT  139.644 5.729 140.454 6.035 ;
     RECT  149.292 5.999 149.634 6.035 ;
     RECT  152.028 5.881 152.874 6.035 ;
     RECT  152.028 6.035 152.442 6.071 ;
     RECT  133.056 6.035 135.738 6.077 ;
     RECT  141.732 5.995 143.514 6.079 ;
     RECT  149.292 6.035 149.49 6.107 ;
     RECT  140.112 6.035 140.454 6.115 ;
     RECT  141.408 6.079 143.514 6.115 ;
     RECT  140.112 6.115 143.514 6.143 ;
     RECT  145.044 5.773 148.497 6.143 ;
     RECT  149.472 6.107 149.49 6.143 ;
     RECT  146.484 6.143 148.497 6.179 ;
     RECT  1.692 5.453 124.074 6.187 ;
     RECT  137.052 5.729 138.762 6.269 ;
     RECT  146.484 6.179 146.754 6.269 ;
     RECT  1.692 6.187 124.614 6.283 ;
     RECT  153.615 5.729 154.53 6.283 ;
     RECT  155.268 5.729 155.358 6.283 ;
     RECT  147.492 6.179 148.497 6.305 ;
     RECT  140.328 6.143 143.514 6.449 ;
     RECT  138.708 6.269 138.762 6.511 ;
     RECT  153.432 6.283 154.53 6.511 ;
     RECT  155.268 6.283 155.61 6.511 ;
     RECT  138.708 6.511 138.942 6.539 ;
     RECT  153.432 6.511 155.61 6.619 ;
     RECT  153.432 6.619 155.718 6.691 ;
     RECT  133.056 6.077 135.63 6.749 ;
     RECT  145.044 6.143 145.602 6.781 ;
     RECT  153.432 6.691 155.79 6.781 ;
     RECT  144.828 6.781 145.602 6.808 ;
     RECT  141.192 6.449 143.514 6.809 ;
     RECT  140.328 6.449 140.454 6.845 ;
     RECT  133.992 6.749 135.63 6.853 ;
     RECT  1.692 6.283 125.19 6.859 ;
     RECT  144.432 6.808 145.602 6.859 ;
     RECT  137.052 6.269 137.79 7.051 ;
     RECT  153.324 6.781 155.79 7.087 ;
     RECT  1.656 6.859 125.19 7.099 ;
     RECT  153.324 7.087 156.006 7.123 ;
     RECT  141.264 6.809 143.514 7.151 ;
     RECT  146.736 6.269 146.754 7.231 ;
     RECT  148.215 6.305 148.497 7.321 ;
     RECT  1.656 7.099 125.226 7.339 ;
     RECT  126 6.035 132.297 7.339 ;
     RECT  153.324 7.123 156.114 7.349 ;
     RECT  144.252 6.859 145.602 7.357 ;
     RECT  141.408 7.151 143.514 7.385 ;
     RECT  138.744 6.539 138.942 7.393 ;
     RECT  148.215 7.321 148.77 7.393 ;
     RECT  152.424 6.071 152.442 7.429 ;
     RECT  148.215 7.393 149.022 7.435 ;
     RECT  150.084 7.435 150.102 7.483 ;
     RECT  150.084 7.483 150.498 7.501 ;
     RECT  152.352 7.429 152.442 7.501 ;
     RECT  133.992 6.853 135.666 7.655 ;
     RECT  149.976 7.501 150.498 7.661 ;
     RECT  138.744 7.393 139.122 7.675 ;
     RECT  148.215 7.435 149.13 7.699 ;
     RECT  149.976 7.661 150.426 7.699 ;
     RECT  152.28 7.501 152.442 7.699 ;
     RECT  141.768 7.385 143.514 7.723 ;
     RECT  144.252 7.357 145.746 7.723 ;
     RECT  138.744 7.675 139.41 7.735 ;
     RECT  138.6 7.735 139.41 7.771 ;
     RECT  152.28 7.699 152.514 7.771 ;
     RECT  134.532 7.655 135.666 8.041 ;
     RECT  1.656 7.339 132.297 8.107 ;
     RECT  152.28 7.771 152.55 8.131 ;
     RECT  153.324 7.349 156.006 8.131 ;
     RECT  152.28 8.131 156.006 8.159 ;
     RECT  134.532 8.041 135.702 8.195 ;
     RECT  141.768 7.723 145.746 8.339 ;
     RECT  142.092 8.339 145.746 8.401 ;
     RECT  138.6 7.771 139.554 8.437 ;
     RECT  142.092 8.401 145.782 8.465 ;
     RECT  136.476 7.051 137.79 8.491 ;
     RECT  138.6 8.437 139.698 8.491 ;
     RECT  142.2 8.465 145.782 8.537 ;
     RECT  152.424 8.159 156.006 8.537 ;
     RECT  142.452 8.537 145.782 8.671 ;
     RECT  136.476 8.491 139.698 8.735 ;
     RECT  152.64 8.537 155.286 8.771 ;
     RECT  134.532 8.195 135.666 8.779 ;
     RECT  142.452 8.671 145.818 8.851 ;
     RECT  148.215 7.699 150.426 8.941 ;
     RECT  152.82 8.771 155.286 9.041 ;
     RECT  148.215 8.941 150.462 9.077 ;
     RECT  152.928 9.041 155.286 9.113 ;
     RECT  134.496 8.779 135.666 9.121 ;
     RECT  137.415 8.735 139.698 9.121 ;
     RECT  140.436 6.845 140.454 9.121 ;
     RECT  133.056 6.749 133.11 9.275 ;
     RECT  153.615 9.113 155.286 9.391 ;
     RECT  133.992 9.121 135.666 9.499 ;
     RECT  153.615 9.391 155.646 9.545 ;
     RECT  153.615 9.545 155.61 10.049 ;
     RECT  133.956 9.499 135.666 10.075 ;
     RECT  136.476 8.735 136.494 10.075 ;
     RECT  153.615 10.049 155.286 10.093 ;
     RECT  133.956 10.075 136.494 10.355 ;
     RECT  153.216 10.093 155.286 10.459 ;
     RECT  0.936 8.107 132.297 10.507 ;
     RECT  146.736 7.231 147.042 10.625 ;
     RECT  133.056 9.275 133.074 10.651 ;
     RECT  148.215 9.077 149.814 10.699 ;
     RECT  152.82 10.459 155.286 10.843 ;
     RECT  147.924 10.699 149.814 10.891 ;
     RECT  150.768 10.315 150.786 10.891 ;
     RECT  134.496 10.355 136.494 10.895 ;
     RECT  0.9 10.507 132.297 10.987 ;
     RECT  152.82 10.843 155.466 11.245 ;
     RECT  147.924 10.891 150.786 11.258 ;
     RECT  151.884 10.123 151.902 11.258 ;
     RECT  147.924 11.258 151.902 11.309 ;
     RECT  135.288 10.895 136.494 11.419 ;
     RECT  0.864 10.987 132.297 11.467 ;
     RECT  152.82 11.245 155.538 11.551 ;
     RECT  152.82 11.551 155.934 11.705 ;
     RECT  142.452 8.851 145.89 11.749 ;
     RECT  146.736 10.625 146.79 11.749 ;
     RECT  150.768 11.309 151.902 11.755 ;
     RECT  142.452 11.749 146.79 11.803 ;
     RECT  147.924 11.309 149.814 11.803 ;
     RECT  152.82 11.705 155.646 11.939 ;
     RECT  152.82 11.939 155.574 11.975 ;
     RECT  137.415 9.121 140.454 11.983 ;
     RECT  0.828 11.467 132.297 12.043 ;
     RECT  133.056 10.651 133.254 12.043 ;
     RECT  133.056 12.043 133.47 12.253 ;
     RECT  134.496 10.895 134.514 12.253 ;
     RECT  133.056 12.253 134.514 12.353 ;
     RECT  137.415 11.983 140.562 12.361 ;
     RECT  150.768 11.755 151.938 12.361 ;
     RECT  152.82 11.975 155.286 12.361 ;
     RECT  133.236 12.353 134.514 12.487 ;
     RECT  135.288 11.419 136.674 12.487 ;
     RECT  137.415 12.361 140.598 12.523 ;
     RECT  137.415 12.523 140.85 12.829 ;
     RECT  142.452 11.803 149.814 12.929 ;
     RECT  142.452 12.929 145.89 13.003 ;
     RECT  137.415 12.829 141.354 13.063 ;
     RECT  133.236 12.487 136.674 13.085 ;
     RECT  0.792 12.043 132.297 13.099 ;
     RECT  150.768 12.361 155.286 13.099 ;
     RECT  0.756 13.099 132.297 13.195 ;
     RECT  150.768 13.099 155.394 13.369 ;
     RECT  134.496 13.085 136.674 13.433 ;
     RECT  150.768 13.369 155.61 13.441 ;
     RECT  150.768 13.441 155.754 13.595 ;
     RECT  146.772 12.929 149.814 13.603 ;
     RECT  142.128 13.003 145.89 13.675 ;
     RECT  146.772 13.603 149.886 13.675 ;
     RECT  142.128 13.675 149.886 13.801 ;
     RECT  150.768 13.595 155.682 13.801 ;
     RECT  133.236 13.085 133.47 13.819 ;
     RECT  142.128 13.801 155.682 13.829 ;
     RECT  135.288 13.433 136.674 13.867 ;
     RECT  137.412 13.063 141.354 13.867 ;
     RECT  142.128 13.829 155.61 13.973 ;
     RECT  133.236 13.819 133.65 14.107 ;
     RECT  142.128 13.973 155.106 14.171 ;
     RECT  155.016 14.171 155.106 14.243 ;
     RECT  135.288 13.867 141.354 14.443 ;
     RECT  142.128 14.171 154.278 14.443 ;
     RECT  0.72 13.195 132.297 14.521 ;
     RECT  133.02 14.107 133.65 14.521 ;
     RECT  135.288 14.443 154.278 14.549 ;
     RECT  155.088 14.243 155.106 14.827 ;
     RECT  155.088 14.827 155.214 14.989 ;
     RECT  134.496 13.433 134.514 15.061 ;
     RECT  135.288 14.549 144.594 15.061 ;
     RECT  155.088 14.989 155.322 15.061 ;
     RECT  145.476 14.549 154.278 15.179 ;
     RECT  155.088 15.061 155.394 15.331 ;
     RECT  155.088 15.331 155.934 15.485 ;
     RECT  155.088 15.485 155.466 15.863 ;
     RECT  134.496 15.061 144.594 15.871 ;
     RECT  150.768 15.179 154.278 15.989 ;
     RECT  145.476 15.179 149.922 16.069 ;
     RECT  150.768 15.989 151.938 16.069 ;
     RECT  134.496 15.871 144.666 16.105 ;
     RECT  152.82 15.989 154.278 16.141 ;
     RECT  155.088 15.863 155.214 16.141 ;
     RECT  145.476 16.069 151.938 16.169 ;
     RECT  0.72 14.521 133.65 16.267 ;
     RECT  134.388 16.105 144.666 16.267 ;
     RECT  152.82 16.141 155.214 16.295 ;
     RECT  0.72 16.267 144.666 16.331 ;
     RECT  138.42 16.331 144.666 16.411 ;
     RECT  145.476 16.169 149.922 16.411 ;
     RECT  0.72 16.331 137.697 16.529 ;
     RECT  153.615 16.295 155.214 16.843 ;
     RECT  153.615 16.843 155.538 16.915 ;
     RECT  153.615 16.915 155.574 17.069 ;
     RECT  153.615 17.069 155.538 17.339 ;
     RECT  153.615 17.339 155.466 17.375 ;
     RECT  138.42 16.411 149.922 17.419 ;
     RECT  138.42 17.419 149.958 17.491 ;
     RECT  150.768 16.169 151.938 17.491 ;
     RECT  152.82 16.295 152.838 17.491 ;
     RECT  153.615 17.375 155.142 17.491 ;
     RECT  134.784 16.529 137.697 17.653 ;
     RECT  138.42 17.491 151.938 17.653 ;
     RECT  0.72 16.529 133.65 17.851 ;
     RECT  134.784 17.653 151.938 17.851 ;
     RECT  0.72 17.851 151.938 17.987 ;
     RECT  138.42 17.987 151.938 18.031 ;
     RECT  152.82 17.491 155.142 18.031 ;
     RECT  0.72 17.987 137.697 18.805 ;
     RECT  138.42 18.031 155.142 18.805 ;
     RECT  0.72 18.805 155.142 18.811 ;
     RECT  0.72 18.811 155.79 18.869 ;
     RECT  0.72 18.869 151.938 18.995 ;
     RECT  152.892 18.869 155.79 19.345 ;
     RECT  152.892 19.345 156.582 19.499 ;
     RECT  152.892 19.499 155.466 19.535 ;
     RECT  156.564 19.499 156.582 19.643 ;
     RECT  131.364 18.995 151.938 19.769 ;
     RECT  152.892 19.535 155.358 20.147 ;
     RECT  149.76 19.769 151.938 21.091 ;
     RECT  152.892 20.147 153.897 21.091 ;
     RECT  131.364 19.769 149.022 21.115 ;
     RECT  149.76 21.091 153.897 21.115 ;
     RECT  154.692 20.147 155.358 21.115 ;
     RECT  0.72 18.995 130.626 21.199 ;
     RECT  131.364 21.115 155.358 21.199 ;
     RECT  0.72 21.199 155.358 21.263 ;
     RECT  138.42 21.263 155.358 22.199 ;
     RECT  138.42 22.199 152.838 22.208 ;
     RECT  0.72 21.263 137.697 22.819 ;
     RECT  138.42 22.208 151.938 22.819 ;
     RECT  0.72 22.819 151.938 24.269 ;
     RECT  153.615 22.199 155.358 24.601 ;
     RECT  153.615 24.601 155.502 25.051 ;
     RECT  0.72 24.269 149.526 25.169 ;
     RECT  152.82 22.208 152.838 25.177 ;
     RECT  153.615 25.051 155.646 25.177 ;
     RECT  152.82 25.177 155.646 25.205 ;
     RECT  0.72 25.169 149.418 26.669 ;
     RECT  150.372 24.269 151.938 26.761 ;
     RECT  152.82 25.205 155.358 26.761 ;
     RECT  147.312 26.669 149.418 26.797 ;
     RECT  150.372 26.761 155.358 26.797 ;
     RECT  147.312 26.797 155.358 26.897 ;
     RECT  0.72 26.669 146.502 27.509 ;
     RECT  147.312 26.897 150.75 27.635 ;
     RECT  151.488 26.897 155.358 27.635 ;
     RECT  147.312 27.635 149.526 27.707 ;
     RECT  150.372 27.635 150.75 28.921 ;
     RECT  0.72 27.509 146.43 29.057 ;
     RECT  147.312 27.707 149.022 29.299 ;
     RECT  149.904 28.921 150.75 29.299 ;
     RECT  125.676 29.057 146.43 29.363 ;
     RECT  147.312 29.299 150.75 29.939 ;
     RECT  151.488 27.635 151.506 29.939 ;
     RECT  152.46 27.635 155.358 30.605 ;
     RECT  125.676 29.363 146.178 30.649 ;
     RECT  125.676 30.649 146.502 30.749 ;
     RECT  148.215 29.939 150.75 30.991 ;
     RECT  152.82 30.605 155.358 31.351 ;
     RECT  0.72 29.057 124.65 31.757 ;
     RECT  152.676 31.351 155.358 31.801 ;
     RECT  125.676 30.749 146.178 31.927 ;
     RECT  147.312 29.939 147.33 31.991 ;
     RECT  148.14 30.991 150.75 32.305 ;
     RECT  147.888 32.305 150.75 32.459 ;
     RECT  148.14 32.459 150.75 32.801 ;
     RECT  125.676 31.927 146.502 32.909 ;
     RECT  152.388 31.801 155.358 33.043 ;
     RECT  125.676 32.909 146.394 33.611 ;
     RECT  148.14 32.801 150.498 33.781 ;
     RECT  147.492 33.781 150.498 33.821 ;
     RECT  152.244 33.043 155.358 33.845 ;
     RECT  0.72 31.757 124.614 33.917 ;
     RECT  147.816 33.821 150.498 33.961 ;
     RECT  153 33.845 155.358 33.989 ;
     RECT  147.816 33.961 151.074 34.013 ;
     RECT  126 33.611 146.394 34.385 ;
     RECT  147.888 34.013 151.074 34.385 ;
     RECT  133.776 34.385 146.394 34.501 ;
     RECT  150.156 34.385 151.074 34.529 ;
     RECT  133.776 34.501 146.43 34.691 ;
     RECT  140.688 34.691 146.43 34.771 ;
     RECT  147.888 34.385 149.31 34.799 ;
     RECT  140.688 34.771 146.466 34.889 ;
     RECT  133.776 34.691 139.95 34.973 ;
     RECT  140.688 34.889 146.394 34.997 ;
     RECT  136.548 34.973 139.95 35.033 ;
     RECT  140.688 34.997 146.358 35.159 ;
     RECT  136.548 35.033 139.626 35.267 ;
     RECT  147.888 34.799 149.166 35.429 ;
     RECT  140.688 35.159 146.25 35.501 ;
     RECT  126 34.385 132.966 35.509 ;
     RECT  147.888 35.429 149.058 35.699 ;
     RECT  147.888 35.699 148.914 35.735 ;
     RECT  126 35.509 133.002 35.851 ;
     RECT  133.776 34.973 135.594 35.851 ;
     RECT  126 35.851 135.594 35.977 ;
     RECT  136.548 35.267 139.374 35.977 ;
     RECT  140.688 35.501 146.178 36.005 ;
     RECT  126 35.977 139.374 36.931 ;
     RECT  125.676 36.931 139.374 37.613 ;
     RECT  136.548 37.613 139.374 37.831 ;
     RECT  140.688 36.005 145.818 37.831 ;
     RECT  136.548 37.831 139.842 37.867 ;
     RECT  140.652 37.831 145.818 37.867 ;
     RECT  125.676 37.613 135.666 37.967 ;
     RECT  125.676 37.967 135.594 38.129 ;
     RECT  128.88 38.129 135.594 38.435 ;
     RECT  136.548 37.867 145.818 38.435 ;
     RECT  133.344 38.435 135.594 38.749 ;
     RECT  133.344 38.749 135.666 38.939 ;
     RECT  133.668 38.939 135.666 38.975 ;
     RECT  125.676 38.129 127.962 39.119 ;
     RECT  128.88 38.435 132.354 39.317 ;
     RECT  136.548 38.435 139.626 39.559 ;
     RECT  140.688 38.435 145.818 39.559 ;
     RECT  129.06 39.317 132.354 39.857 ;
     RECT  136.548 39.559 145.818 40.289 ;
     RECT  136.548 40.289 139.41 40.325 ;
     RECT  136.548 40.325 139.338 42.287 ;
     RECT  140.688 40.289 145.818 42.485 ;
     RECT  137.415 42.287 139.338 43.141 ;
     RECT  131.076 39.857 132.354 43.231 ;
     RECT  133.74 38.975 135.666 43.231 ;
     RECT  136.548 42.287 136.638 43.303 ;
     RECT  144.648 42.485 145.818 43.303 ;
     RECT  136.404 43.303 136.638 43.403 ;
     RECT  125.676 39.119 127.386 43.411 ;
     RECT  136.476 43.403 136.638 43.681 ;
     RECT  137.376 43.141 139.338 43.681 ;
     RECT  0.72 33.917 124.542 43.843 ;
     RECT  140.688 42.485 143.91 43.879 ;
     RECT  144.648 43.303 145.962 43.915 ;
     RECT  140.256 43.879 143.91 44.077 ;
     RECT  140.148 44.077 143.91 44.149 ;
     RECT  144.648 43.915 146.61 44.149 ;
     RECT  129.06 39.857 129.834 44.383 ;
     RECT  140.148 44.149 146.61 44.491 ;
     RECT  147.888 35.735 148.497 44.491 ;
     RECT  154.692 33.989 155.358 44.491 ;
     RECT  140.148 44.491 146.754 44.617 ;
     RECT  147.492 44.491 148.497 44.617 ;
     RECT  136.476 43.681 139.338 44.653 ;
     RECT  140.148 44.617 148.497 44.653 ;
     RECT  154.692 44.491 155.502 44.689 ;
     RECT  136.476 44.653 148.497 44.879 ;
     RECT  131.076 43.231 135.666 44.887 ;
     RECT  136.476 44.879 139.482 44.887 ;
     RECT  150.156 34.529 150.39 44.887 ;
     RECT  147.528 44.879 148.497 44.915 ;
     RECT  0.72 43.843 124.614 44.923 ;
     RECT  125.352 43.411 127.386 44.923 ;
     RECT  150.156 44.887 150.57 44.923 ;
     RECT  131.076 44.887 139.482 44.951 ;
     RECT  137.415 44.951 139.482 44.987 ;
     RECT  140.256 44.879 146.79 44.987 ;
     RECT  147.708 44.915 148.497 44.987 ;
     RECT  139.32 44.987 139.482 45.023 ;
     RECT  131.076 44.951 136.494 45.185 ;
     RECT  140.256 44.987 146.754 45.185 ;
     RECT  140.328 45.185 146.754 45.221 ;
     RECT  131.076 45.185 134.046 45.329 ;
     RECT  150.156 44.923 151.074 45.455 ;
     RECT  156.996 44.959 157.014 45.455 ;
     RECT  140.688 45.221 146.754 45.491 ;
     RECT  154.692 44.689 156.006 45.571 ;
     RECT  158.508 44.923 158.526 45.571 ;
     RECT  159.732 44.995 159.75 45.571 ;
     RECT  141.192 45.491 146.754 45.761 ;
     RECT  134.784 45.185 136.494 45.769 ;
     RECT  137.415 44.987 138.582 45.769 ;
     RECT  146.268 45.761 146.754 45.805 ;
     RECT  158.508 45.571 159.75 45.841 ;
     RECT  134.784 45.769 138.582 45.995 ;
     RECT  133.056 45.329 134.046 46.103 ;
     RECT  146.268 45.805 147.042 46.103 ;
     RECT  134.784 45.995 136.494 46.139 ;
     RECT  150.156 45.455 150.57 46.229 ;
     RECT  153.615 33.989 153.897 46.237 ;
     RECT  154.692 45.571 156.15 46.237 ;
     RECT  146.52 46.103 147.042 46.265 ;
     RECT  157.068 45.805 157.086 46.273 ;
     RECT  153.615 46.237 156.15 46.373 ;
     RECT  157.068 46.273 157.302 46.381 ;
     RECT  158.472 45.841 159.75 46.381 ;
     RECT  146.52 46.265 146.538 46.535 ;
     RECT  157.068 46.381 159.75 46.637 ;
     RECT  154.692 46.373 156.15 46.645 ;
     RECT  154.692 46.645 156.762 46.679 ;
     RECT  156.744 46.679 156.762 46.685 ;
     RECT  154.692 46.679 155.718 46.733 ;
     RECT  134.784 46.139 135.702 46.921 ;
     RECT  136.476 46.139 136.494 46.921 ;
     RECT  157.896 46.637 159.75 46.925 ;
     RECT  158.436 46.925 159.75 46.939 ;
     RECT  134.784 46.921 136.494 47.035 ;
     RECT  137.415 45.995 138.582 47.035 ;
     RECT  158.436 46.939 159.822 47.069 ;
     RECT  134.784 47.035 138.582 47.075 ;
     RECT  158.436 47.069 159.066 47.117 ;
     RECT  134.784 47.075 135.702 47.219 ;
     RECT  159.804 47.069 159.822 47.309 ;
     RECT  146.988 47.425 147.006 47.461 ;
     RECT  141.192 45.761 145.53 47.563 ;
     RECT  136.476 47.075 138.582 47.579 ;
     RECT  158.436 47.117 158.994 47.579 ;
     RECT  156.132 47.623 156.15 47.659 ;
     RECT  158.436 47.579 158.958 47.687 ;
     RECT  150.156 46.229 150.39 47.695 ;
     RECT  141.192 47.563 145.89 47.731 ;
     RECT  146.88 47.461 147.006 47.731 ;
     RECT  156.132 47.659 156.366 47.731 ;
     RECT  150.156 47.695 150.75 47.849 ;
     RECT  158.436 47.687 158.742 47.849 ;
     RECT  156.132 47.731 156.798 47.885 ;
     RECT  147.888 44.987 148.497 47.993 ;
     RECT  141.192 47.731 147.006 48.541 ;
     RECT  141.192 48.541 147.078 48.569 ;
     RECT  144.36 48.569 147.078 48.659 ;
     RECT  144.36 48.659 147.006 48.839 ;
     RECT  146.988 48.839 147.006 48.965 ;
     RECT  137.415 47.579 138.582 49.081 ;
     RECT  139.32 45.023 139.338 49.081 ;
     RECT  137.415 49.081 139.338 49.271 ;
     RECT  144.36 48.839 146.178 49.379 ;
     RECT  141.192 48.569 143.514 49.513 ;
     RECT  137.415 49.271 139.122 49.541 ;
     RECT  144.36 49.379 145.89 49.739 ;
     RECT  144.36 49.739 145.53 49.919 ;
     RECT  144.36 49.919 145.17 50.045 ;
     RECT  134.784 47.219 135.594 50.791 ;
     RECT  137.415 49.541 139.086 52.169 ;
     RECT  133.056 46.103 133.902 52.213 ;
     RECT  134.784 50.791 135.666 52.213 ;
     RECT  133.056 52.213 135.666 52.313 ;
     RECT  137.415 52.169 138.582 52.475 ;
     RECT  136.476 47.579 136.602 52.483 ;
     RECT  137.415 52.475 138.438 52.483 ;
     RECT  136.476 52.483 138.438 52.583 ;
     RECT  141.012 49.513 143.514 52.591 ;
     RECT  140.976 52.591 143.514 52.817 ;
     RECT  144.36 50.045 144.99 53.599 ;
     RECT  141.228 52.817 143.514 53.671 ;
     RECT  144.324 53.599 144.99 53.671 ;
     RECT  141.228 53.671 144.99 53.825 ;
     RECT  144.36 53.825 144.99 54.095 ;
     RECT  134.784 52.313 135.666 54.301 ;
     RECT  136.476 52.583 136.602 54.301 ;
     RECT  134.784 54.301 136.602 54.329 ;
     RECT  134.784 54.329 136.494 54.635 ;
     RECT  134.784 54.635 135.702 54.869 ;
     RECT  141.228 53.825 143.514 54.985 ;
     RECT  133.056 52.313 133.902 55.561 ;
     RECT  134.784 54.869 135.666 55.561 ;
     RECT  0.72 44.923 127.386 55.675 ;
     RECT  0.72 55.675 127.746 55.715 ;
     RECT  133.056 55.561 135.666 55.751 ;
     RECT  141.048 54.985 143.514 55.751 ;
     RECT  133.056 55.751 133.902 56.093 ;
     RECT  133.056 56.093 133.866 56.489 ;
     RECT  128.52 44.383 129.834 56.533 ;
     RECT  131.076 45.329 132.297 56.533 ;
     RECT  134.784 55.751 135.666 56.561 ;
     RECT  128.52 56.533 132.297 56.633 ;
     RECT  135.396 56.561 135.666 58.721 ;
     RECT  158.724 47.849 158.742 60.539 ;
     RECT  144.468 54.095 144.99 62.131 ;
     RECT  148.215 47.993 148.497 62.437 ;
     RECT  154.692 46.733 155.358 62.465 ;
     RECT  133.056 56.489 133.83 65.035 ;
     RECT  0.72 55.715 127.386 65.07 ;
     RECT  133.056 65.035 134.046 65.129 ;
     RECT  142.488 55.751 143.514 65.273 ;
     RECT  0.72 65.07 2.106 65.399 ;
     RECT  37.44 65.07 37.458 65.821 ;
     RECT  3.816 65.07 3.978 65.911 ;
     RECT  0.756 65.399 2.106 65.939 ;
     RECT  144.468 62.131 145.062 65.975 ;
     RECT  98.028 65.07 98.046 66.019 ;
     RECT  23.364 65.866 23.382 66.361 ;
     RECT  57.888 65.803 57.906 66.406 ;
     RECT  57.888 66.406 57.978 66.451 ;
     RECT  136.476 54.635 136.494 66.479 ;
     RECT  30.456 65.821 30.474 66.487 ;
     RECT  124.02 65.07 127.386 66.587 ;
     RECT  96.624 66.559 96.642 66.631 ;
     RECT  20.592 66.361 20.61 66.676 ;
     RECT  20.52 66.676 20.61 66.704 ;
     RECT  3.816 65.911 4.194 66.721 ;
     RECT  39.6 65.07 39.618 66.721 ;
     RECT  36.9 65.821 37.458 66.749 ;
     RECT  0.864 65.939 2.106 66.974 ;
     RECT  81.72 65.983 81.738 66.991 ;
     RECT  144.864 65.975 145.062 67.019 ;
     RECT  24.696 66.946 24.714 67.027 ;
     RECT  141.048 55.751 141.75 67.091 ;
     RECT  131.076 56.633 132.297 67.163 ;
     RECT  0.9 66.974 2.106 67.213 ;
     RECT  23.364 66.361 23.526 67.213 ;
     RECT  24.48 67.027 24.714 67.213 ;
     RECT  30.276 66.487 30.474 67.213 ;
     RECT  35.676 65.07 35.694 67.213 ;
     RECT  39.6 66.721 39.726 67.213 ;
     RECT  45.108 66.406 45.126 67.213 ;
     RECT  57.276 66.451 57.978 67.213 ;
     RECT  94.536 67.135 94.554 67.213 ;
     RECT  3.816 66.721 4.266 67.243 ;
     RECT  20.52 66.704 20.538 67.243 ;
     RECT  34.2 66.991 34.218 67.243 ;
     RECT  35.007 67.213 35.694 67.243 ;
     RECT  69.408 65.07 69.426 67.243 ;
     RECT  98.028 66.019 98.406 67.243 ;
     RECT  116.007 67.213 116.097 67.243 ;
     RECT  38.844 67.243 38.862 67.261 ;
     RECT  39.6 67.213 40.497 67.261 ;
     RECT  56.607 67.213 57.978 67.261 ;
     RECT  59.148 65.911 59.166 67.261 ;
     RECT  60.552 65.07 60.57 67.261 ;
     RECT  62.007 67.213 62.097 67.261 ;
     RECT  62.892 67.027 62.91 67.261 ;
     RECT  105.207 67.213 105.297 67.261 ;
     RECT  116.007 67.243 116.334 67.261 ;
     RECT  118.872 66.325 118.89 67.261 ;
     RECT  154.872 62.465 155.358 67.261 ;
     RECT  56.607 67.261 59.166 67.288 ;
     RECT  59.904 67.261 60.57 67.288 ;
     RECT  3.42 67.243 4.266 67.289 ;
     RECT  20.052 67.243 20.538 67.289 ;
     RECT  47.052 66.955 47.07 67.289 ;
     RECT  118.728 67.261 118.89 67.289 ;
     RECT  21.348 67.288 21.366 67.325 ;
     RECT  114.768 67.288 114.786 67.325 ;
     RECT  97.38 67.243 98.406 67.333 ;
     RECT  118.728 67.289 118.746 67.333 ;
     RECT  133.056 65.129 133.83 67.333 ;
     RECT  137.415 52.583 138.438 67.333 ;
     RECT  118.584 67.333 118.746 67.339 ;
     RECT  48.168 67.261 48.186 67.361 ;
     RECT  145.044 67.019 145.062 67.361 ;
     RECT  54.72 67.261 54.738 67.369 ;
     RECT  79.416 65.947 79.434 67.369 ;
     RECT  80.352 67.243 80.37 67.369 ;
     RECT  99.807 67.213 99.897 67.369 ;
     RECT  118.476 67.339 118.746 67.369 ;
     RECT  150.156 47.849 150.39 67.369 ;
     RECT  137.415 67.333 139.446 67.373 ;
     RECT  62.007 67.261 62.91 67.387 ;
     RECT  79.416 67.369 80.37 67.387 ;
     RECT  116.007 67.261 116.406 67.397 ;
     RECT  118.008 67.369 118.746 67.397 ;
     RECT  128.52 56.633 129.834 67.397 ;
     RECT  78.207 67.213 78.297 67.405 ;
     RECT  81.72 66.991 82.17 67.405 ;
     RECT  102.6 67.261 102.618 67.405 ;
     RECT  56.607 67.288 60.57 67.421 ;
     RECT  79.416 67.387 80.55 67.421 ;
     RECT  21.42 67.333 21.438 67.433 ;
     RECT  56.607 67.421 59.67 67.433 ;
     RECT  96.228 66.631 96.642 67.441 ;
     RECT  100.98 66.487 100.998 67.441 ;
     RECT  105.207 67.261 105.642 67.441 ;
     RECT  139.284 67.373 139.446 67.441 ;
     RECT  102.6 67.405 102.69 67.469 ;
     RECT  133.056 67.333 134.55 67.469 ;
     RECT  8.007 67.213 8.097 67.483 ;
     RECT  13.407 67.213 13.497 67.483 ;
     RECT  18.807 67.213 18.897 67.483 ;
     RECT  29.607 67.213 30.474 67.483 ;
     RECT  51.207 67.213 51.297 67.483 ;
     RECT  56.607 67.433 59.166 67.483 ;
     RECT  62.007 67.387 63.594 67.483 ;
     RECT  67.407 67.213 67.497 67.483 ;
     RECT  72.807 67.213 72.897 67.483 ;
     RECT  78.207 67.405 78.678 67.483 ;
     RECT  83.607 67.213 83.697 67.483 ;
     RECT  89.007 67.213 89.097 67.483 ;
     RECT  94.407 67.213 94.554 67.483 ;
     RECT  99.756 67.369 99.897 67.483 ;
     RECT  110.607 67.213 110.697 67.483 ;
     RECT  116.007 67.397 116.097 67.483 ;
     RECT  121.407 67.213 121.497 67.483 ;
     RECT  104.328 67.441 105.642 67.517 ;
     RECT  56.415 67.483 59.166 67.559 ;
     RECT  80.208 67.421 80.55 67.559 ;
     RECT  97.38 67.333 98.622 67.559 ;
     RECT  104.472 67.517 105.642 67.559 ;
     RECT  118.008 67.397 118.602 67.559 ;
     RECT  139.284 67.441 139.518 67.559 ;
     RECT  33.552 67.243 35.946 67.603 ;
     RECT  36.9 66.749 37.386 67.603 ;
     RECT  38.844 67.261 40.806 67.603 ;
     RECT  41.616 66.451 41.634 67.603 ;
     RECT  94.215 67.483 94.554 67.603 ;
     RECT  100.98 67.441 101.394 67.603 ;
     RECT  80.208 67.559 80.262 67.613 ;
     RECT  23.364 67.213 24.714 67.639 ;
     RECT  104.76 67.559 105.642 67.703 ;
     RECT  56.415 67.559 59.13 67.711 ;
     RECT  71.784 67.099 71.802 67.711 ;
     RECT  107.172 67.171 107.19 67.711 ;
     RECT  104.76 67.703 105.426 67.739 ;
     RECT  142.815 65.273 143.514 67.739 ;
     RECT  22.608 67.441 22.626 67.771 ;
     RECT  45.108 67.213 45.897 67.771 ;
     RECT  18.615 67.483 18.897 67.801 ;
     RECT  56.268 67.711 59.13 67.801 ;
     RECT  106.56 67.711 107.19 67.801 ;
     RECT  44.388 67.771 45.897 67.819 ;
     RECT  67.215 67.483 67.497 67.819 ;
     RECT  22.464 67.771 22.626 67.829 ;
     RECT  71.352 67.711 71.802 67.829 ;
     RECT  81.468 67.405 82.17 67.829 ;
     RECT  124.02 66.587 126.897 67.829 ;
     RECT  17.568 65.07 17.586 67.837 ;
     RECT  38.844 67.603 41.634 67.837 ;
     RECT  66.888 67.819 67.497 67.837 ;
     RECT  75.42 65.866 75.438 67.837 ;
     RECT  83.415 67.483 83.697 67.837 ;
     RECT  84.42 66.523 84.438 67.837 ;
     RECT  86.364 66.379 86.382 67.837 ;
     RECT  99.615 67.483 99.897 67.837 ;
     RECT  100.98 67.603 101.502 67.837 ;
     RECT  118.008 67.559 118.062 67.853 ;
     RECT  33.552 67.603 37.386 67.864 ;
     RECT  137.415 67.373 138.438 67.865 ;
     RECT  18.615 67.801 19.026 67.873 ;
     RECT  23.364 67.639 24.75 67.873 ;
     RECT  31.428 67.819 31.446 67.873 ;
     RECT  42.696 67.837 42.714 67.873 ;
     RECT  56.052 67.801 59.13 67.873 ;
     RECT  68.94 67.243 69.426 67.873 ;
     RECT  74.664 67.837 75.438 67.873 ;
     RECT  86.364 67.837 86.598 67.873 ;
     RECT  110.415 67.483 110.697 67.873 ;
     RECT  44.064 67.819 45.897 67.901 ;
     RECT  56.016 67.873 59.13 67.901 ;
     RECT  104.76 67.739 105.354 67.901 ;
     RECT  11.772 67.819 11.79 67.909 ;
     RECT  38.844 67.837 41.778 67.909 ;
     RECT  54.72 67.369 54.81 67.909 ;
     RECT  106.236 67.801 107.19 67.909 ;
     RECT  42.696 67.873 42.786 67.915 ;
     RECT  68.94 67.873 70.002 67.945 ;
     RECT  74.664 67.873 75.654 67.945 ;
     RECT  88.815 67.483 89.097 67.945 ;
     RECT  94.215 67.603 94.662 67.945 ;
     RECT  99.615 67.837 101.502 67.945 ;
     RECT  17.568 67.837 17.874 67.949 ;
     RECT  142.815 67.739 143.097 67.963 ;
     RECT  153.615 46.373 153.897 67.963 ;
     RECT  68.4 67.945 70.002 67.973 ;
     RECT  83.415 67.837 84.51 67.973 ;
     RECT  11.772 67.909 11.898 67.981 ;
     RECT  31.356 67.873 31.446 67.981 ;
     RECT  32.292 67.837 32.454 67.981 ;
     RECT  70.776 67.909 70.83 67.981 ;
     RECT  86.256 67.873 87.03 67.981 ;
     RECT  95.976 67.441 96.642 67.981 ;
     RECT  106.236 67.909 107.262 67.981 ;
     RECT  81 67.873 81.018 68.009 ;
     RECT  122.544 67.909 122.562 68.009 ;
     RECT  142.704 67.963 143.097 68.009 ;
     RECT  54.72 67.909 55.098 68.059 ;
     RECT  86.184 67.981 87.03 68.059 ;
     RECT  110.34 67.873 110.697 68.059 ;
     RECT  18.615 67.873 19.062 68.071 ;
     RECT  31.356 67.981 32.454 68.071 ;
     RECT  33.552 67.864 37.602 68.071 ;
     RECT  54.72 68.059 55.242 68.071 ;
     RECT  56.016 67.901 58.878 68.071 ;
     RECT  66.744 67.837 67.497 68.098 ;
     RECT  23.364 67.873 24.822 68.099 ;
     RECT  31.356 68.071 37.602 68.099 ;
     RECT  86.148 68.059 87.318 68.099 ;
     RECT  95.544 67.981 96.642 68.099 ;
     RECT  108.288 66.595 108.306 68.099 ;
     RECT  109.98 68.059 110.697 68.099 ;
     RECT  34.2 68.099 37.602 68.107 ;
     RECT  72.615 67.483 72.897 68.107 ;
     RECT  74.124 67.945 75.726 68.107 ;
     RECT  139.5 67.559 139.518 68.107 ;
     RECT  138.42 67.865 138.438 68.135 ;
     RECT  11.772 67.981 11.934 68.143 ;
     RECT  20.484 67.289 20.538 68.143 ;
     RECT  38.772 67.909 41.778 68.143 ;
     RECT  60.444 67.421 60.57 68.143 ;
     RECT  66.708 68.098 67.497 68.143 ;
     RECT  98.028 67.559 98.622 68.143 ;
     RECT  99.504 67.945 101.502 68.143 ;
     RECT  106.236 67.981 107.55 68.143 ;
     RECT  60.444 68.143 60.642 68.155 ;
     RECT  98.028 68.143 101.502 68.17 ;
     RECT  95.544 68.099 95.634 68.171 ;
     RECT  106.236 68.143 108.162 68.171 ;
     RECT  110.34 68.099 110.697 68.171 ;
     RECT  66.708 68.143 67.662 68.179 ;
     RECT  68.4 67.973 69.93 68.179 ;
     RECT  78.015 67.483 78.678 68.179 ;
     RECT  79.416 67.421 79.434 68.179 ;
     RECT  83.415 67.973 84.186 68.179 ;
     RECT  154.764 67.261 155.358 68.179 ;
     RECT  106.236 68.171 106.686 68.189 ;
     RECT  51.015 67.483 51.297 68.203 ;
     RECT  54.72 68.071 58.878 68.203 ;
     RECT  18.432 68.071 19.062 68.207 ;
     RECT  44.172 67.901 45.897 68.207 ;
     RECT  61.815 67.483 63.594 68.207 ;
     RECT  71.856 67.837 71.874 68.207 ;
     RECT  86.184 68.099 87.318 68.207 ;
     RECT  10.836 67.837 10.854 68.215 ;
     RECT  11.7 68.143 12.258 68.215 ;
     RECT  31.356 68.099 33.066 68.215 ;
     RECT  102.672 67.469 102.69 68.215 ;
     RECT  17.568 67.949 17.658 68.243 ;
     RECT  72.615 68.107 75.726 68.243 ;
     RECT  106.236 68.189 106.65 68.243 ;
     RECT  110.376 68.171 110.697 68.243 ;
     RECT  147.996 62.437 148.497 68.243 ;
     RECT  153.324 67.963 153.897 68.243 ;
     RECT  3.816 67.289 4.266 68.251 ;
     RECT  5.076 68.071 5.094 68.251 ;
     RECT  49.572 68.071 49.59 68.251 ;
     RECT  66.708 68.179 69.93 68.251 ;
     RECT  118.008 67.853 118.026 68.251 ;
     RECT  153.615 68.243 153.897 68.251 ;
     RECT  154.764 68.179 155.538 68.251 ;
     RECT  10.836 68.215 12.258 68.279 ;
     RECT  66.24 68.251 69.93 68.279 ;
     RECT  98.028 68.17 101.538 68.279 ;
     RECT  106.236 68.243 106.506 68.279 ;
     RECT  117.576 68.251 118.026 68.279 ;
     RECT  11.052 68.279 12.258 68.285 ;
     RECT  6.444 68.251 6.822 68.341 ;
     RECT  7.815 67.483 8.097 68.341 ;
     RECT  44.352 68.207 45.897 68.341 ;
     RECT  62.892 68.207 63.594 68.341 ;
     RECT  18.615 68.207 19.062 68.369 ;
     RECT  31.248 68.215 33.066 68.369 ;
     RECT  62.892 68.341 63.954 68.369 ;
     RECT  66.24 68.279 69.858 68.369 ;
     RECT  78.015 68.179 79.434 68.369 ;
     RECT  98.028 68.279 100.926 68.369 ;
     RECT  106.344 68.279 106.506 68.369 ;
     RECT  107.532 68.171 108.162 68.369 ;
     RECT  117.576 68.279 117.81 68.369 ;
     RECT  153.615 68.251 155.538 68.369 ;
     RECT  3.816 68.251 5.13 68.377 ;
     RECT  11.196 68.285 12.258 68.377 ;
     RECT  13.215 67.483 13.497 68.377 ;
     RECT  25.992 65.07 26.01 68.377 ;
     RECT  29.415 67.483 30.474 68.377 ;
     RECT  31.248 68.369 31.446 68.377 ;
     RECT  47.268 67.675 47.286 68.377 ;
     RECT  49.572 68.251 49.626 68.377 ;
     RECT  60.444 68.155 60.714 68.377 ;
     RECT  61.815 68.207 62.097 68.377 ;
     RECT  80.244 67.613 80.262 68.377 ;
     RECT  81.792 67.829 82.17 68.377 ;
     RECT  83.376 68.179 84.186 68.377 ;
     RECT  25.992 68.377 26.55 68.395 ;
     RECT  51.015 68.203 51.39 68.395 ;
     RECT  54.576 68.203 58.878 68.395 ;
     RECT  102.6 68.215 102.69 68.395 ;
     RECT  6.444 68.341 8.097 68.405 ;
     RECT  78.015 68.369 79.362 68.405 ;
     RECT  99.252 68.369 100.926 68.405 ;
     RECT  109.152 68.143 109.17 68.405 ;
     RECT  117.792 68.369 117.81 68.405 ;
     RECT  153.615 68.369 154.314 68.405 ;
     RECT  21.672 67.441 21.69 68.413 ;
     RECT  25.992 68.395 26.802 68.413 ;
     RECT  38.772 68.143 41.958 68.413 ;
     RECT  42.696 67.915 42.822 68.413 ;
     RECT  50.904 68.395 51.39 68.413 ;
     RECT  94.104 67.945 94.662 68.413 ;
     RECT  98.028 68.369 98.478 68.413 ;
     RECT  150.084 67.369 150.39 68.413 ;
     RECT  6.552 68.405 8.097 68.441 ;
     RECT  18.615 68.369 19.026 68.441 ;
     RECT  128.52 67.397 129.51 68.441 ;
     RECT  149.94 68.413 150.39 68.441 ;
     RECT  25.992 68.413 27.234 68.443 ;
     RECT  92.16 68.413 92.25 68.443 ;
     RECT  54.288 68.395 58.878 68.449 ;
     RECT  155.052 68.369 155.538 68.449 ;
     RECT  0.9 67.213 2.697 68.477 ;
     RECT  21.672 68.413 22.122 68.485 ;
     RECT  34.2 68.107 37.854 68.485 ;
     RECT  90.648 68.071 90.666 68.485 ;
     RECT  20.34 68.143 20.574 68.491 ;
     RECT  21.492 68.485 22.122 68.491 ;
     RECT  128.52 68.441 129.15 68.513 ;
     RECT  34.2 68.485 37.926 68.521 ;
     RECT  63 68.369 63.954 68.521 ;
     RECT  93.492 68.413 94.698 68.521 ;
     RECT  96.624 68.099 96.642 68.521 ;
     RECT  155.052 68.449 155.718 68.521 ;
     RECT  20.34 68.491 22.122 68.525 ;
     RECT  155.052 68.521 155.754 68.549 ;
     RECT  90.432 68.485 90.846 68.587 ;
     RECT  25.956 68.443 27.234 68.611 ;
     RECT  34.2 68.521 37.998 68.611 ;
     RECT  38.772 68.413 42.822 68.611 ;
     RECT  50.904 68.413 51.822 68.611 ;
     RECT  63 68.521 63.99 68.611 ;
     RECT  60.444 68.377 62.097 68.635 ;
     RECT  92.16 68.443 92.322 68.635 ;
     RECT  93.456 68.521 94.698 68.635 ;
     RECT  32.184 68.369 32.454 68.639 ;
     RECT  54.18 68.449 58.878 68.639 ;
     RECT  78.015 68.405 78.822 68.639 ;
     RECT  97.812 68.413 98.478 68.639 ;
     RECT  99.252 68.405 100.386 68.639 ;
     RECT  102.6 68.395 103.302 68.647 ;
     RECT  66.708 68.369 69.462 68.648 ;
     RECT  60.408 68.635 62.097 68.675 ;
     RECT  63 68.611 64.026 68.675 ;
     RECT  72.615 68.243 75.618 68.675 ;
     RECT  106.38 68.369 106.506 68.675 ;
     RECT  155.268 68.549 155.754 68.675 ;
     RECT  23.4 68.099 24.822 68.683 ;
     RECT  25.668 68.611 27.234 68.683 ;
     RECT  44.352 68.341 45.954 68.683 ;
     RECT  54.18 68.639 58.842 68.711 ;
     RECT  63.324 68.675 64.026 68.711 ;
     RECT  70.704 67.981 70.83 68.711 ;
     RECT  14.868 68.683 14.886 68.719 ;
     RECT  16.884 68.683 16.938 68.719 ;
     RECT  88.815 67.945 89.442 68.719 ;
     RECT  90.432 68.587 91.242 68.719 ;
     RECT  20.34 68.525 22.05 68.72 ;
     RECT  34.2 68.611 42.822 68.747 ;
     RECT  63.324 68.711 63.99 68.747 ;
     RECT  66.708 68.648 68.274 68.747 ;
     RECT  74.016 68.675 75.618 68.747 ;
     RECT  109.224 68.413 109.242 68.747 ;
     RECT  3.708 68.377 5.13 68.755 ;
     RECT  14.868 68.719 15.39 68.755 ;
     RECT  16.668 68.719 16.938 68.755 ;
     RECT  49.572 68.377 49.734 68.755 ;
     RECT  88.815 68.719 91.242 68.755 ;
     RECT  92.16 68.635 94.698 68.755 ;
     RECT  95.544 68.171 95.562 68.755 ;
     RECT  102.6 68.647 103.482 68.755 ;
     RECT  47.268 68.377 47.898 68.783 ;
     RECT  54.18 68.711 58.806 68.783 ;
     RECT  3.708 68.755 5.166 68.791 ;
     RECT  29.415 68.377 31.446 68.791 ;
     RECT  80.244 68.377 80.982 68.791 ;
     RECT  81.792 68.377 84.186 68.791 ;
     RECT  86.256 68.207 87.318 68.791 ;
     RECT  102.6 68.755 103.878 68.791 ;
     RECT  104.76 67.901 105.297 68.791 ;
     RECT  6.66 68.441 8.097 68.813 ;
     RECT  88.815 68.755 95.562 68.813 ;
     RECT  14.868 68.755 15.426 68.819 ;
     RECT  20.34 68.72 22.014 68.819 ;
     RECT  58.356 68.783 58.806 68.819 ;
     RECT  124.02 67.829 125.154 68.819 ;
     RECT  9.684 68.377 9.702 68.881 ;
     RECT  16.56 68.755 16.938 68.881 ;
     RECT  48.924 68.755 49.734 68.881 ;
     RECT  3.708 68.791 5.274 68.909 ;
     RECT  15.192 68.819 15.426 68.909 ;
     RECT  60.624 68.675 62.097 68.909 ;
     RECT  63.324 68.747 63.954 68.909 ;
     RECT  78.015 68.639 78.75 68.909 ;
     RECT  92.376 68.813 95.562 68.909 ;
     RECT  97.812 68.639 98.406 68.909 ;
     RECT  149.94 68.441 150.102 68.909 ;
     RECT  155.268 68.675 155.718 68.909 ;
     RECT  15.336 68.909 15.426 68.917 ;
     RECT  16.344 68.881 16.938 68.917 ;
     RECT  20.34 68.819 21.906 68.945 ;
     RECT  34.704 68.747 42.822 68.945 ;
     RECT  88.815 68.813 91.566 68.945 ;
     RECT  150.012 68.909 150.102 68.945 ;
     RECT  155.268 68.909 155.286 68.945 ;
     RECT  50.904 68.611 52.074 68.953 ;
     RECT  54.18 68.783 57.582 68.953 ;
     RECT  96.624 68.521 96.894 68.953 ;
     RECT  15.336 68.917 16.938 68.957 ;
     RECT  44.352 68.683 46.206 68.957 ;
     RECT  66.708 68.747 68.202 68.957 ;
     RECT  3.96 68.909 5.202 68.981 ;
     RECT  11.196 68.377 13.497 68.981 ;
     RECT  15.336 68.957 16.686 68.981 ;
     RECT  20.34 68.945 21.834 68.981 ;
     RECT  32.184 68.639 32.418 68.981 ;
     RECT  48.924 68.881 49.77 68.981 ;
     RECT  54.144 68.953 57.582 68.981 ;
     RECT  61.344 68.909 62.097 68.981 ;
     RECT  70.704 68.711 70.794 68.981 ;
     RECT  86.256 68.791 87.786 68.981 ;
     RECT  91.512 68.945 91.566 68.981 ;
     RECT  98.208 68.909 98.226 68.981 ;
     RECT  102.6 68.791 105.297 68.981 ;
     RECT  48.996 68.981 49.77 69.016 ;
     RECT  50.508 68.953 52.074 69.016 ;
     RECT  34.704 68.945 41.958 69.017 ;
     RECT  63.324 68.909 63.846 69.017 ;
     RECT  80.244 68.791 84.186 69.017 ;
     RECT  150.084 68.945 150.102 69.017 ;
     RECT  23.4 68.683 27.234 69.025 ;
     RECT  29.34 68.791 31.446 69.025 ;
     RECT  48.996 69.016 52.074 69.025 ;
     RECT  102.6 68.981 103.482 69.025 ;
     RECT  20.34 68.981 21.654 69.053 ;
     RECT  21.492 69.053 21.654 69.059 ;
     RECT  9.684 68.881 10.242 69.061 ;
     RECT  48.996 69.025 52.47 69.061 ;
     RECT  74.124 68.747 75.618 69.061 ;
     RECT  96.3 68.953 96.894 69.061 ;
     RECT  3.96 68.981 5.166 69.179 ;
     RECT  20.34 69.053 20.718 69.179 ;
     RECT  21.492 69.059 21.51 69.179 ;
     RECT  48.996 69.061 52.542 69.179 ;
     RECT  55.152 68.981 57.582 69.179 ;
     RECT  67.032 68.957 68.202 69.179 ;
     RECT  80.244 69.017 82.674 69.179 ;
     RECT  87.444 68.981 87.786 69.179 ;
     RECT  92.844 68.909 95.562 69.187 ;
     RECT  96.3 69.061 96.966 69.187 ;
     RECT  3.96 69.179 4.95 69.215 ;
     RECT  20.34 69.179 20.574 69.215 ;
     RECT  34.704 69.017 37.674 69.215 ;
     RECT  67.032 69.179 68.13 69.215 ;
     RECT  126 67.829 126.897 69.251 ;
     RECT  29.124 69.025 31.446 69.259 ;
     RECT  32.184 68.981 32.382 69.259 ;
     RECT  74.124 69.061 75.978 69.259 ;
     RECT  9.144 69.061 10.242 69.287 ;
     RECT  29.124 69.259 32.382 69.287 ;
     RECT  74.124 69.259 76.086 69.287 ;
     RECT  48.996 69.179 52.506 69.293 ;
     RECT  9.144 69.287 9.414 69.295 ;
     RECT  69.012 68.648 69.462 69.331 ;
     RECT  136.584 67.531 136.602 69.331 ;
     RECT  137.415 67.865 137.697 69.331 ;
     RECT  49.788 69.293 52.506 69.359 ;
     RECT  74.592 69.287 76.086 69.359 ;
     RECT  102.564 69.025 103.482 69.359 ;
     RECT  135.396 58.721 135.594 69.359 ;
     RECT  69.012 69.331 69.75 69.421 ;
     RECT  72.615 68.675 73.242 69.421 ;
     RECT  104.76 68.981 105.297 69.421 ;
     RECT  106.38 68.675 106.398 69.421 ;
     RECT  9 69.295 9.414 69.449 ;
     RECT  23.4 69.025 27.342 69.449 ;
     RECT  29.34 69.287 32.382 69.449 ;
     RECT  34.704 69.215 37.566 69.449 ;
     RECT  67.215 69.215 67.914 69.449 ;
     RECT  70.632 69.331 70.65 69.449 ;
     RECT  83.415 69.017 84.186 69.449 ;
     RECT  102.564 69.359 103.014 69.449 ;
     RECT  104.76 69.421 106.398 69.449 ;
     RECT  136.584 69.331 137.697 69.449 ;
     RECT  29.34 69.449 32.31 69.485 ;
     RECT  136.584 69.449 136.602 69.485 ;
     RECT  63.432 69.017 63.846 69.491 ;
     RECT  42.804 68.945 42.822 69.493 ;
     RECT  15.336 68.981 16.434 69.521 ;
     RECT  49.788 69.359 52.074 69.521 ;
     RECT  74.592 69.359 74.682 69.521 ;
     RECT  9 69.449 9.27 69.533 ;
     RECT  18.615 68.441 18.954 69.547 ;
     RECT  92.844 69.187 96.966 69.557 ;
     RECT  54.144 68.981 54.162 69.593 ;
     RECT  63.756 69.491 63.846 69.691 ;
     RECT  64.584 69.547 64.602 69.691 ;
     RECT  10.152 69.287 10.242 69.719 ;
     RECT  34.776 69.449 37.566 69.719 ;
     RECT  51.015 69.521 52.074 69.719 ;
     RECT  91.512 68.981 91.53 69.719 ;
     RECT  102.6 69.449 103.014 69.719 ;
     RECT  45.396 68.957 46.206 69.727 ;
     RECT  78.015 68.909 78.678 69.727 ;
     RECT  51.015 69.719 51.966 69.755 ;
     RECT  99.504 68.639 100.386 69.763 ;
     RECT  10.224 69.719 10.242 69.791 ;
     RECT  47.268 68.783 47.286 69.791 ;
     RECT  78.015 69.727 78.858 69.799 ;
     RECT  38.628 69.017 41.958 69.835 ;
     RECT  63.756 69.691 64.602 69.835 ;
     RECT  15.336 69.521 15.966 69.871 ;
     RECT  18.615 69.547 19.494 69.871 ;
     RECT  20.34 69.215 20.502 69.871 ;
     RECT  63.756 69.835 64.818 69.871 ;
     RECT  80.964 69.179 82.674 69.899 ;
     RECT  63.756 69.871 65.862 69.989 ;
     RECT  102.996 69.719 103.014 69.989 ;
     RECT  104.94 69.449 106.398 69.989 ;
     RECT  18.615 69.871 20.502 69.997 ;
     RECT  58.356 68.819 58.446 69.997 ;
     RECT  86.256 68.981 86.67 69.997 ;
     RECT  93.276 69.557 96.966 70.025 ;
     RECT  42.804 69.493 43.362 70.033 ;
     RECT  81.612 69.899 82.674 70.033 ;
     RECT  83.415 69.449 83.697 70.033 ;
     RECT  99.504 69.763 100.854 70.033 ;
     RECT  0.972 68.477 2.697 70.061 ;
     RECT  44.352 68.957 44.478 70.069 ;
     RECT  45.288 69.727 46.206 70.069 ;
     RECT  58.176 69.997 58.446 70.069 ;
     RECT  58.14 70.069 58.446 70.105 ;
     RECT  87.516 69.179 87.786 70.105 ;
     RECT  88.815 68.945 89.442 70.105 ;
     RECT  81.612 70.033 83.697 70.109 ;
     RECT  11.484 68.981 13.497 70.141 ;
     RECT  23.4 69.449 24.822 70.141 ;
     RECT  74.664 69.521 74.682 70.141 ;
     RECT  78.015 69.799 79.074 70.141 ;
     RECT  79.992 69.295 80.01 70.141 ;
     RECT  133.056 67.469 133.83 70.169 ;
     RECT  42.804 70.033 43.398 70.231 ;
     RECT  44.352 70.069 46.206 70.231 ;
     RECT  92.448 70.075 92.538 70.231 ;
     RECT  23.112 70.141 24.822 70.259 ;
     RECT  37.296 69.719 37.566 70.259 ;
     RECT  105.015 69.989 106.398 70.259 ;
     RECT  55.152 69.179 57.294 70.261 ;
     RECT  58.14 70.105 58.482 70.261 ;
     RECT  99.504 70.033 100.926 70.261 ;
     RECT  18.252 69.997 20.502 70.267 ;
     RECT  99.432 70.261 100.926 70.301 ;
     RECT  48.996 69.293 49.014 70.303 ;
     RECT  86.22 69.997 86.67 70.303 ;
     RECT  48.456 70.303 49.014 70.331 ;
     RECT  72.615 69.421 73.386 70.331 ;
     RECT  18.252 70.267 21.114 70.367 ;
     RECT  85.932 70.303 86.67 70.375 ;
     RECT  87.516 70.105 89.442 70.375 ;
     RECT  48.456 70.331 48.474 70.403 ;
     RECT  106.38 70.259 106.398 70.403 ;
     RECT  55.152 70.261 58.482 70.411 ;
     RECT  67.215 69.449 67.662 70.411 ;
     RECT  90.432 68.945 90.45 70.411 ;
     RECT  91.836 70.231 92.538 70.411 ;
     RECT  93.276 70.025 94.698 70.411 ;
     RECT  10.836 70.141 13.497 70.439 ;
     RECT  85.932 70.375 89.442 70.445 ;
     RECT  14.832 69.871 15.966 70.529 ;
     RECT  135.396 69.359 135.414 70.529 ;
     RECT  14.832 70.529 15.858 70.537 ;
     RECT  85.032 70.303 85.05 70.537 ;
     RECT  85.932 70.445 86.67 70.537 ;
     RECT  81.792 70.109 83.697 70.601 ;
     RECT  84.492 70.537 86.67 70.601 ;
     RECT  91.836 70.411 94.698 70.601 ;
     RECT  99.468 70.301 100.926 70.601 ;
     RECT  3.96 69.215 4.338 70.609 ;
     RECT  22.644 70.411 22.662 70.637 ;
     RECT  3.96 70.609 4.554 70.645 ;
     RECT  85.284 70.601 86.67 70.673 ;
     RECT  14.688 70.537 15.858 70.681 ;
     RECT  18.252 70.367 20.502 70.681 ;
     RECT  29.34 69.485 32.238 70.681 ;
     RECT  55.152 70.411 58.626 70.681 ;
     RECT  74.664 70.141 74.718 70.681 ;
     RECT  75.888 70.645 75.906 70.681 ;
     RECT  83.088 70.601 83.697 70.681 ;
     RECT  99.504 70.601 100.926 70.681 ;
     RECT  139.5 68.107 139.842 70.681 ;
     RECT  42.804 70.231 46.206 70.709 ;
     RECT  139.5 70.681 139.95 70.709 ;
     RECT  6.804 68.813 8.097 70.747 ;
     RECT  9 69.533 9.018 70.747 ;
     RECT  17.676 70.681 20.502 70.747 ;
     RECT  6.048 70.699 6.066 70.771 ;
     RECT  6.804 70.747 9.018 70.771 ;
     RECT  23.4 70.259 24.822 70.771 ;
     RECT  90.432 70.411 90.666 70.771 ;
     RECT  91.836 70.601 94.626 70.771 ;
     RECT  6.048 70.771 9.018 70.799 ;
     RECT  14.256 70.681 15.858 70.799 ;
     RECT  38.556 69.835 41.958 70.799 ;
     RECT  43.848 70.709 46.206 70.799 ;
     RECT  54.576 70.681 58.626 70.799 ;
     RECT  95.544 70.025 96.966 70.799 ;
     RECT  141.048 67.091 141.066 70.799 ;
     RECT  23.4 70.771 24.93 70.807 ;
     RECT  25.668 69.449 27.342 70.807 ;
     RECT  54.72 70.799 58.626 70.807 ;
     RECT  37.296 70.259 37.422 70.835 ;
     RECT  85.284 70.673 86.382 70.835 ;
     RECT  98.604 70.645 98.622 70.835 ;
     RECT  139.824 70.709 139.95 70.835 ;
     RECT  34.776 69.719 36.234 70.843 ;
     RECT  90.432 70.771 94.626 70.871 ;
     RECT  7.815 70.799 9.018 70.879 ;
     RECT  34.776 70.843 36.306 70.879 ;
     RECT  49.788 69.521 49.806 70.879 ;
     RECT  38.556 70.799 39.15 70.907 ;
     RECT  83.088 70.681 84.366 70.907 ;
     RECT  85.464 70.835 86.382 70.907 ;
     RECT  95.616 70.799 96.966 70.907 ;
     RECT  99.504 70.681 100.998 70.907 ;
     RECT  6.048 70.799 6.93 70.915 ;
     RECT  74.664 70.681 75.906 70.915 ;
     RECT  77.112 70.681 77.13 70.915 ;
     RECT  3.852 70.645 4.554 70.951 ;
     RECT  17.604 70.747 20.502 70.951 ;
     RECT  34.704 70.879 36.306 70.951 ;
     RECT  49.788 70.879 50.202 70.951 ;
     RECT  63.756 69.989 65.394 70.951 ;
     RECT  74.664 70.915 76.122 70.951 ;
     RECT  77.112 70.915 77.202 70.951 ;
     RECT  78.015 70.141 80.01 70.951 ;
     RECT  14.256 70.799 15.534 70.979 ;
     RECT  38.772 70.907 39.15 70.979 ;
     RECT  60.876 70.807 60.894 71.032 ;
     RECT  5.976 70.915 6.93 71.035 ;
     RECT  63.756 70.951 65.502 71.035 ;
     RECT  74.448 70.951 80.01 71.035 ;
     RECT  29.34 70.681 32.274 71.041 ;
     RECT  49.752 70.951 50.202 71.041 ;
     RECT  51.015 69.755 51.297 71.041 ;
     RECT  72.615 70.331 73.026 71.041 ;
     RECT  23.4 70.807 27.342 71.069 ;
     RECT  34.596 70.951 36.738 71.069 ;
     RECT  44.388 70.799 46.206 71.069 ;
     RECT  49.752 71.041 51.297 71.069 ;
     RECT  53.1 70.699 53.118 71.069 ;
     RECT  60.552 71.032 60.894 71.069 ;
     RECT  74.376 71.035 80.01 71.077 ;
     RECT  39.888 70.799 41.958 71.105 ;
     RECT  74.268 71.077 80.01 71.105 ;
     RECT  34.596 71.069 36.666 71.113 ;
     RECT  59.724 70.951 59.742 71.113 ;
     RECT  63.396 71.035 65.502 71.113 ;
     RECT  14.292 70.979 15.534 71.117 ;
     RECT  63.324 71.113 65.502 71.141 ;
     RECT  3.852 70.951 4.95 71.149 ;
     RECT  74.268 71.105 75.654 71.176 ;
     RECT  29.34 71.041 32.49 71.177 ;
     RECT  38.772 70.979 38.79 71.177 ;
     RECT  63.324 71.141 65.25 71.177 ;
     RECT  45.396 71.069 46.206 71.185 ;
     RECT  14.652 71.117 15.534 71.213 ;
     RECT  59.724 71.113 59.814 71.213 ;
     RECT  63.324 71.177 65.034 71.213 ;
     RECT  74.16 71.176 75.654 71.213 ;
     RECT  76.752 71.105 80.01 71.213 ;
     RECT  138.528 70.915 138.546 71.213 ;
     RECT  79.38 71.213 80.01 71.221 ;
     RECT  87.516 70.445 89.442 71.221 ;
     RECT  96.228 70.907 96.966 71.221 ;
     RECT  14.688 71.213 15.282 71.249 ;
     RECT  70.704 70.879 70.722 71.249 ;
     RECT  76.752 71.213 78.297 71.249 ;
     RECT  72.252 71.041 73.026 71.311 ;
     RECT  7.815 70.879 9.198 71.339 ;
     RECT  34.488 71.113 36.666 71.339 ;
     RECT  54.72 70.807 58.806 71.339 ;
     RECT  60.876 71.069 60.894 71.339 ;
     RECT  81.792 70.601 82.35 71.339 ;
     RECT  83.232 70.907 84.366 71.339 ;
     RECT  67.215 70.411 67.914 71.347 ;
     RECT  15.084 71.249 15.282 71.375 ;
     RECT  29.34 71.177 32.202 71.375 ;
     RECT  34.815 71.339 36.594 71.375 ;
     RECT  54.72 71.339 55.242 71.375 ;
     RECT  76.752 71.249 77.202 71.375 ;
     RECT  79.38 71.221 80.298 71.375 ;
     RECT  49.932 71.069 51.297 71.383 ;
     RECT  67.215 71.347 67.986 71.383 ;
     RECT  29.34 71.375 31.338 71.411 ;
     RECT  99.504 70.907 100.962 71.411 ;
     RECT  71.928 71.311 73.026 71.413 ;
     RECT  45.396 71.185 46.638 71.419 ;
     RECT  71.928 71.413 73.098 71.419 ;
     RECT  85.572 70.907 86.382 71.419 ;
     RECT  87.516 71.221 89.586 71.419 ;
     RECT  11.484 70.439 13.497 71.455 ;
     RECT  67.215 71.383 68.166 71.455 ;
     RECT  69.012 69.421 69.822 71.455 ;
     RECT  71.748 71.419 73.098 71.455 ;
     RECT  76.824 71.375 77.13 71.483 ;
     RECT  85.572 71.419 86.67 71.483 ;
     RECT  90.432 70.871 94.497 71.483 ;
     RECT  17.46 70.951 20.502 71.491 ;
     RECT  21.744 71.311 21.762 71.491 ;
     RECT  29.34 71.411 31.23 71.491 ;
     RECT  33.624 71.221 33.642 71.491 ;
     RECT  57.492 71.339 58.806 71.491 ;
     RECT  71.748 71.455 73.818 71.491 ;
     RECT  85.932 71.483 86.67 71.491 ;
     RECT  87.408 71.419 89.586 71.491 ;
     RECT  90.432 71.483 91.602 71.491 ;
     RECT  39.888 71.105 41.058 71.501 ;
     RECT  15.084 71.375 15.102 71.519 ;
     RECT  85.932 71.491 91.602 71.519 ;
     RECT  96.228 71.221 97.11 71.519 ;
     RECT  131.076 67.163 131.094 71.519 ;
     RECT  28.908 71.491 31.23 71.609 ;
     RECT  33.048 71.491 33.642 71.609 ;
     RECT  71.388 71.491 73.818 71.609 ;
     RECT  74.628 71.213 75.582 71.609 ;
     RECT  85.932 71.519 91.314 71.609 ;
     RECT  21.744 71.491 22.23 71.651 ;
     RECT  3.852 71.149 5.022 71.653 ;
     RECT  126.072 69.251 126.897 71.681 ;
     RECT  3.852 71.653 5.094 71.689 ;
     RECT  5.832 71.035 6.93 71.689 ;
     RECT  29.052 71.609 31.23 71.717 ;
     RECT  54.72 71.375 54.738 71.717 ;
     RECT  56.016 71.339 56.697 71.717 ;
     RECT  90.432 71.609 90.666 71.717 ;
     RECT  105.015 70.259 105.297 71.725 ;
     RECT  3.852 71.689 6.93 71.753 ;
     RECT  85.932 71.609 89.694 71.753 ;
     RECT  45.396 71.419 47.07 71.761 ;
     RECT  82.332 71.339 82.35 71.761 ;
     RECT  83.232 71.339 83.862 71.761 ;
     RECT  10.836 71.455 13.497 71.789 ;
     RECT  29.304 71.717 31.23 71.789 ;
     RECT  49.932 71.383 51.57 71.789 ;
     RECT  71.388 71.609 73.206 71.789 ;
     RECT  85.932 71.753 89.097 71.789 ;
     RECT  86.688 71.789 89.097 71.795 ;
     RECT  3.996 71.753 6.93 71.851 ;
     RECT  7.815 71.339 9.018 71.851 ;
     RECT  22.212 71.651 22.23 71.851 ;
     RECT  44.388 71.069 44.406 71.887 ;
     RECT  45.396 71.761 47.25 71.887 ;
     RECT  3.996 71.851 9.018 71.888 ;
     RECT  75.204 71.609 75.582 71.915 ;
     RECT  44.388 71.887 47.25 71.923 ;
     RECT  11.556 71.789 13.497 71.951 ;
     RECT  106.596 71.851 106.614 71.951 ;
     RECT  124.02 68.819 124.758 71.951 ;
     RECT  67.215 71.455 69.822 71.959 ;
     RECT  40.215 71.501 41.058 71.987 ;
     RECT  71.388 71.789 73.134 71.987 ;
     RECT  38.88 71.959 38.898 71.995 ;
     RECT  52.848 71.077 52.866 72.023 ;
     RECT  104.616 71.725 105.297 72.023 ;
     RECT  57.492 71.491 58.878 72.031 ;
     RECT  62.82 71.995 62.838 72.031 ;
     RECT  79.38 71.375 80.01 72.031 ;
     RECT  103.824 71.851 103.842 72.031 ;
     RECT  71.388 71.987 73.026 72.059 ;
     RECT  92.34 71.483 94.497 72.059 ;
     RECT  57.492 72.031 58.914 72.139 ;
     RECT  133.128 70.169 133.83 72.149 ;
     RECT  22.212 71.851 22.518 72.157 ;
     RECT  23.4 71.069 27.234 72.157 ;
     RECT  62.82 72.031 62.874 72.185 ;
     RECT  103.68 72.031 103.986 72.185 ;
     RECT  133.632 72.149 133.83 72.185 ;
     RECT  62.856 72.185 62.874 72.187 ;
     RECT  63.756 71.213 65.034 72.187 ;
     RECT  3.996 71.888 6.858 72.221 ;
     RECT  66.708 71.959 69.822 72.221 ;
     RECT  62.856 72.187 65.034 72.229 ;
     RECT  57.492 72.139 58.986 72.23 ;
     RECT  62.856 72.229 65.07 72.257 ;
     RECT  7.815 71.888 9.018 72.265 ;
     RECT  9.792 71.959 9.81 72.265 ;
     RECT  38.772 71.995 38.898 72.265 ;
     RECT  57.492 72.23 58.95 72.269 ;
     RECT  57.492 72.269 58.914 72.293 ;
     RECT  71.388 72.059 71.766 72.293 ;
     RECT  49.932 71.789 51.297 72.301 ;
     RECT  54.936 72.265 54.954 72.301 ;
     RECT  92.844 72.059 94.497 72.301 ;
     RECT  92.844 72.301 94.77 72.329 ;
     RECT  72.504 72.059 73.026 72.365 ;
     RECT  33.624 71.609 33.642 72.379 ;
     RECT  38.664 72.265 38.898 72.391 ;
     RECT  79.2 72.031 80.01 72.391 ;
     RECT  81.252 72.031 81.27 72.391 ;
     RECT  22.212 72.157 27.234 72.419 ;
     RECT  44.388 71.923 47.574 72.419 ;
     RECT  49.608 72.301 51.297 72.419 ;
     RECT  79.2 72.391 81.27 72.419 ;
     RECT  96.624 71.519 97.11 72.419 ;
     RECT  38.664 72.391 39.042 72.427 ;
     RECT  40.215 71.987 41.022 72.427 ;
     RECT  44.46 72.419 47.574 72.455 ;
     RECT  67.215 72.221 69.822 72.455 ;
     RECT  54.936 72.301 55.098 72.491 ;
     RECT  63.288 72.257 65.07 72.491 ;
     RECT  22.68 72.419 27.234 72.499 ;
     RECT  39.888 72.427 41.022 72.499 ;
     RECT  79.524 72.419 81.27 72.499 ;
     RECT  79.524 72.499 81.378 72.535 ;
     RECT  85.932 71.789 85.95 72.535 ;
     RECT  38.448 72.427 39.042 72.571 ;
     RECT  39.78 72.499 41.022 72.571 ;
     RECT  56.415 71.717 56.697 72.571 ;
     RECT  22.68 72.499 27.522 72.599 ;
     RECT  34.815 71.375 36.234 72.599 ;
     RECT  49.608 72.419 49.95 72.605 ;
     RECT  56.088 72.571 56.697 72.661 ;
     RECT  3.996 72.221 6.642 72.689 ;
     RECT  34.815 72.599 36.162 72.689 ;
     RECT  47.52 72.455 47.574 72.689 ;
     RECT  57.492 72.293 58.626 72.689 ;
     RECT  63.288 72.491 64.962 72.689 ;
     RECT  67.215 72.455 68.526 72.689 ;
     RECT  33.336 72.379 33.642 72.697 ;
     RECT  67.215 72.689 68.418 72.725 ;
     RECT  22.968 72.599 27.522 72.761 ;
     RECT  47.556 72.689 47.574 72.761 ;
     RECT  82.332 71.761 83.862 72.769 ;
     RECT  85.932 72.535 86.31 72.769 ;
     RECT  34.815 72.689 35.514 72.797 ;
     RECT  33.336 72.697 33.858 72.805 ;
     RECT  34.815 72.797 35.097 72.805 ;
     RECT  29.34 71.789 31.23 72.841 ;
     RECT  50.724 72.419 51.297 72.841 ;
     RECT  52.02 72.463 52.038 72.841 ;
     RECT  85.932 72.769 86.67 72.841 ;
     RECT  63.288 72.689 64.782 72.869 ;
     RECT  55.98 72.661 56.697 72.931 ;
     RECT  79.524 72.535 81.414 72.931 ;
     RECT  82.152 72.769 83.862 72.931 ;
     RECT  99.504 71.411 100.314 72.931 ;
     RECT  4.104 72.689 6.642 72.959 ;
     RECT  23.076 72.761 27.522 72.959 ;
     RECT  29.088 72.841 31.23 72.959 ;
     RECT  38.448 72.571 41.022 72.959 ;
     RECT  50.724 72.841 52.038 72.959 ;
     RECT  42.804 70.709 42.822 72.967 ;
     RECT  33.336 72.805 35.097 72.995 ;
     RECT  76.968 71.483 77.13 73.003 ;
     RECT  78.015 71.249 78.297 73.003 ;
     RECT  2.415 70.061 2.697 73.039 ;
     RECT  29.304 72.959 31.23 73.039 ;
     RECT  42.732 72.967 42.822 73.039 ;
     RECT  43.632 71.959 43.65 73.039 ;
     RECT  50.796 72.959 52.038 73.067 ;
     RECT  12.924 71.951 13.497 73.075 ;
     RECT  32.184 71.375 32.202 73.103 ;
     RECT  57.744 72.689 58.626 73.111 ;
     RECT  99.18 72.931 100.314 73.111 ;
     RECT  38.628 72.959 41.022 73.139 ;
     RECT  128.52 68.513 128.538 73.139 ;
     RECT  76.968 73.003 78.297 73.195 ;
     RECT  85.464 72.841 86.67 73.201 ;
     RECT  87.408 71.795 89.097 73.201 ;
     RECT  2.415 73.039 2.898 73.229 ;
     RECT  33.336 72.995 33.354 73.229 ;
     RECT  34.2 72.995 35.097 73.229 ;
     RECT  41.94 71.105 41.958 73.237 ;
     RECT  54.936 72.491 54.954 73.237 ;
     RECT  55.98 72.931 56.754 73.237 ;
     RECT  42.732 73.039 43.65 73.265 ;
     RECT  54.144 71.887 54.162 73.265 ;
     RECT  54.936 73.237 56.754 73.273 ;
     RECT  23.292 72.959 27.522 73.309 ;
     RECT  41.94 73.237 41.994 73.309 ;
     RECT  42.732 73.265 42.822 73.309 ;
     RECT  12.924 73.075 13.554 73.345 ;
     RECT  79.524 72.931 83.862 73.345 ;
     RECT  54.936 73.273 56.826 73.373 ;
     RECT  29.304 73.039 31.41 73.381 ;
     RECT  71.208 72.301 71.226 73.381 ;
     RECT  72.615 72.365 73.026 73.381 ;
     RECT  75.204 71.915 75.222 73.381 ;
     RECT  4.176 72.959 6.642 73.409 ;
     RECT  70.668 73.381 71.226 73.409 ;
     RECT  33.192 73.345 33.21 73.421 ;
     RECT  12.924 73.345 14.022 73.483 ;
     RECT  12.888 73.483 14.022 73.499 ;
     RECT  12.888 73.499 13.986 73.535 ;
     RECT  17.352 71.491 20.502 73.535 ;
     RECT  95.544 73.507 95.562 73.543 ;
     RECT  96.336 72.535 96.354 73.543 ;
     RECT  98.604 73.111 100.314 73.543 ;
     RECT  72.615 73.381 73.602 73.579 ;
     RECT  74.592 73.381 75.222 73.579 ;
     RECT  90.432 71.717 90.45 73.579 ;
     RECT  95.544 73.543 96.354 73.579 ;
     RECT  97.092 72.419 97.11 73.579 ;
     RECT  40.215 73.139 41.022 73.615 ;
     RECT  41.94 73.309 42.822 73.615 ;
     RECT  54.936 73.373 56.697 73.615 ;
     RECT  89.82 73.579 90.45 73.615 ;
     RECT  7.815 72.265 9.81 73.651 ;
     RECT  43.632 73.265 43.65 73.651 ;
     RECT  44.46 72.455 46.638 73.651 ;
     RECT  61.815 68.981 62.097 73.651 ;
     RECT  79.524 73.345 84.186 73.651 ;
     RECT  23.292 73.309 27.63 73.679 ;
     RECT  38.628 73.139 39.474 73.679 ;
     RECT  29.304 73.381 31.446 73.741 ;
     RECT  7.815 73.651 9.846 73.769 ;
     RECT  54.72 73.615 56.697 73.769 ;
     RECT  61.815 73.651 62.19 73.769 ;
     RECT  98.46 73.543 100.314 73.769 ;
     RECT  76.572 73.195 78.297 73.777 ;
     RECT  92.844 72.329 92.97 73.777 ;
     RECT  26.676 73.679 27.63 73.805 ;
     RECT  54.72 73.769 55.494 73.805 ;
     RECT  98.46 73.769 100.17 73.805 ;
     RECT  92.628 73.777 92.97 73.813 ;
     RECT  0.972 70.061 1.638 73.841 ;
     RECT  2.415 73.229 2.862 73.841 ;
     RECT  7.815 73.769 9.81 73.841 ;
     RECT  23.292 73.679 25.938 73.849 ;
     RECT  57.744 73.111 58.914 73.849 ;
     RECT  61.815 73.769 62.097 73.849 ;
     RECT  76.428 73.777 78.297 73.849 ;
     RECT  79.488 73.651 84.186 73.849 ;
     RECT  50.904 73.067 52.038 73.877 ;
     RECT  79.488 73.849 84.438 73.877 ;
     RECT  76.104 73.849 78.39 73.885 ;
     RECT  79.488 73.877 81.45 73.885 ;
     RECT  98.46 73.805 99.897 73.901 ;
     RECT  63.756 72.869 64.782 73.912 ;
     RECT  76.104 73.885 81.45 73.913 ;
     RECT  89.82 73.615 90.81 73.913 ;
     RECT  11.556 71.951 12.042 73.921 ;
     RECT  57.564 73.849 58.914 73.921 ;
     RECT  85.464 73.201 89.097 73.921 ;
     RECT  89.82 73.913 89.838 73.921 ;
     RECT  94.215 72.329 94.77 73.921 ;
     RECT  95.544 73.579 97.11 73.921 ;
     RECT  22.824 73.849 25.938 73.949 ;
     RECT  26.892 73.805 27.63 73.949 ;
     RECT  29.304 73.741 31.59 73.949 ;
     RECT  40.215 73.615 42.822 73.949 ;
     RECT  54.72 73.805 54.738 73.949 ;
     RECT  57.492 73.921 58.914 73.949 ;
     RECT  76.104 73.913 80.874 73.949 ;
     RECT  85.464 73.921 89.838 73.949 ;
     RECT  124.02 71.951 124.038 73.949 ;
     RECT  11.412 73.921 12.042 74.011 ;
     RECT  92.196 73.813 92.97 74.011 ;
     RECT  7.815 73.841 9.702 74.039 ;
     RECT  40.215 73.949 42.03 74.039 ;
     RECT  50.904 73.877 51.39 74.039 ;
     RECT  57.492 73.949 58.842 74.039 ;
     RECT  12.924 73.535 13.986 74.075 ;
     RECT  50.904 74.039 51.318 74.075 ;
     RECT  57.492 74.039 58.482 74.075 ;
     RECT  90.72 73.913 90.81 74.075 ;
     RECT  94.215 73.921 97.11 74.075 ;
     RECT  15.876 73.849 15.894 74.083 ;
     RECT  11.304 74.011 12.042 74.107 ;
     RECT  76.104 73.949 80.838 74.111 ;
     RECT  90.792 74.075 90.81 74.111 ;
     RECT  72.615 73.579 75.222 74.119 ;
     RECT  70.668 73.409 70.794 74.147 ;
     RECT  76.104 74.111 80.262 74.147 ;
     RECT  91.764 74.011 92.97 74.155 ;
     RECT  88.815 73.949 89.838 74.183 ;
     RECT  29.415 73.949 31.59 74.191 ;
     RECT  38.628 73.679 39.078 74.191 ;
     RECT  56.415 73.769 56.697 74.191 ;
     RECT  57.492 74.075 58.23 74.191 ;
     RECT  63.756 73.912 64.854 74.191 ;
     RECT  69.408 72.455 69.822 74.191 ;
     RECT  70.668 74.147 70.758 74.191 ;
     RECT  42.768 73.949 42.822 74.219 ;
     RECT  15.192 74.083 15.894 74.281 ;
     RECT  29.415 74.191 31.986 74.309 ;
     RECT  38.484 74.191 39.078 74.309 ;
     RECT  53.064 74.191 53.082 74.309 ;
     RECT  56.415 74.191 58.23 74.309 ;
     RECT  69.408 74.191 70.758 74.309 ;
     RECT  76.104 74.147 76.698 74.309 ;
     RECT  69.408 74.309 69.858 74.317 ;
     RECT  15.084 74.281 15.894 74.344 ;
     RECT  29.415 74.309 31.23 74.345 ;
     RECT  43.632 73.651 46.638 74.345 ;
     RECT  82.332 73.877 84.438 74.353 ;
     RECT  85.464 73.949 88.002 74.353 ;
     RECT  15.084 74.344 15.966 74.381 ;
     RECT  18.615 73.535 20.502 74.381 ;
     RECT  31.104 74.345 31.23 74.381 ;
     RECT  10.836 74.107 12.042 74.389 ;
     RECT  63.756 74.191 64.926 74.389 ;
     RECT  7.815 74.039 9.162 74.417 ;
     RECT  29.415 74.345 30.33 74.417 ;
     RECT  31.212 74.381 31.23 74.417 ;
     RECT  15.084 74.381 15.894 74.425 ;
     RECT  76.104 74.309 76.302 74.425 ;
     RECT  91.332 74.155 92.97 74.429 ;
     RECT  0.972 73.841 1.134 74.453 ;
     RECT  31.968 74.309 31.986 74.453 ;
     RECT  45.144 74.345 46.638 74.453 ;
     RECT  20.34 74.381 20.502 74.461 ;
     RECT  91.512 74.429 92.97 74.461 ;
     RECT  91.512 74.461 93.438 74.489 ;
     RECT  38.664 74.309 39.078 74.551 ;
     RECT  12.924 74.075 13.497 74.579 ;
     RECT  21.996 73.507 22.014 74.579 ;
     RECT  26.964 73.949 27.63 74.579 ;
     RECT  63.18 74.389 64.926 74.579 ;
     RECT  72.288 74.119 75.222 74.587 ;
     RECT  56.415 74.309 58.122 74.615 ;
     RECT  63.18 74.579 64.782 74.615 ;
     RECT  91.512 74.489 92.178 74.615 ;
     RECT  94.215 74.075 96.606 74.615 ;
     RECT  55.476 73.805 55.494 74.623 ;
     RECT  12.996 74.579 13.497 74.651 ;
     RECT  82.332 74.353 88.002 74.651 ;
     RECT  68.832 74.317 69.858 74.662 ;
     RECT  72.072 74.587 75.222 74.669 ;
     RECT  56.415 74.615 57.15 74.687 ;
     RECT  70.704 74.309 70.758 74.687 ;
     RECT  94.215 74.615 96.138 74.723 ;
     RECT  49.932 72.605 49.95 74.731 ;
     RECT  50.904 74.075 51.297 74.731 ;
     RECT  55.296 74.623 55.494 74.759 ;
     RECT  34.815 73.229 35.097 74.779 ;
     RECT  34.164 74.779 35.37 74.821 ;
     RECT  14.508 74.425 15.894 74.849 ;
     RECT  38.664 74.551 39.402 74.849 ;
     RECT  55.548 74.779 55.566 74.849 ;
     RECT  68.832 74.662 69.822 74.849 ;
     RECT  74.016 74.669 75.222 74.849 ;
     RECT  91.512 74.615 91.638 74.849 ;
     RECT  5.076 73.409 6.642 74.857 ;
     RECT  67.215 72.725 68.094 74.857 ;
     RECT  68.832 74.849 68.85 74.857 ;
     RECT  33.84 74.821 35.37 74.861 ;
     RECT  67.215 74.857 68.85 74.885 ;
     RECT  69.804 74.849 69.822 74.885 ;
     RECT  49.932 74.731 51.297 74.893 ;
     RECT  54.252 74.821 54.27 74.909 ;
     RECT  72.072 74.669 73.17 74.909 ;
     RECT  63.18 74.615 64.746 74.921 ;
     RECT  126.216 71.681 126.897 74.921 ;
     RECT  76.032 74.425 76.302 74.957 ;
     RECT  40.215 74.039 41.994 74.993 ;
     RECT  70.704 74.687 70.722 74.993 ;
     RECT  26.964 74.579 26.982 75.001 ;
     RECT  49.608 74.893 51.297 75.001 ;
     RECT  92.916 74.489 93.438 75.001 ;
     RECT  63.18 74.921 63.954 75.029 ;
     RECT  94.215 74.723 95.742 75.029 ;
     RECT  26.784 75.001 26.982 75.091 ;
     RECT  49.068 75.001 51.894 75.091 ;
     RECT  5.076 74.857 7.038 75.119 ;
     RECT  14.508 74.849 15.822 75.119 ;
     RECT  48.564 75.091 52.434 75.119 ;
     RECT  61.56 73.849 62.097 75.119 ;
     RECT  94.215 75.029 95.346 75.119 ;
     RECT  23.4 73.949 25.938 75.127 ;
     RECT  26.712 75.091 26.982 75.127 ;
     RECT  59.148 75.091 59.166 75.127 ;
     RECT  14.508 75.119 15.75 75.155 ;
     RECT  40.215 74.993 41.958 75.155 ;
     RECT  43.632 74.345 44.37 75.155 ;
     RECT  1.116 74.453 1.134 75.191 ;
     RECT  50.184 75.119 51.297 75.191 ;
     RECT  64.728 74.921 64.746 75.191 ;
     RECT  82.332 74.651 85.482 75.191 ;
     RECT  45.36 74.453 46.638 75.199 ;
     RECT  59.148 75.127 59.238 75.199 ;
     RECT  86.292 74.651 88.002 75.227 ;
     RECT  4.176 73.409 4.194 75.235 ;
     RECT  5.076 75.119 6.966 75.235 ;
     RECT  10.764 74.389 12.042 75.235 ;
     RECT  18.615 74.381 19.422 75.259 ;
     RECT  20.34 74.461 20.826 75.259 ;
     RECT  4.176 75.235 6.966 75.263 ;
     RECT  7.815 74.417 9.126 75.263 ;
     RECT  18.615 75.259 20.826 75.271 ;
     RECT  23.4 75.127 26.982 75.271 ;
     RECT  92.916 75.001 93.474 75.271 ;
     RECT  94.215 75.119 94.914 75.271 ;
     RECT  22.86 75.271 26.982 75.299 ;
     RECT  92.916 75.271 94.914 75.307 ;
     RECT  98.64 73.901 99.897 75.307 ;
     RECT  63.18 75.029 63.27 75.361 ;
     RECT  62.928 75.361 63.27 75.389 ;
     RECT  92.7 75.307 94.914 75.389 ;
     RECT  34.164 74.861 35.37 75.397 ;
     RECT  59.148 75.199 59.346 75.397 ;
     RECT  62.928 75.389 63.018 75.397 ;
     RECT  10.296 75.235 12.042 75.425 ;
     RECT  92.7 75.389 94.734 75.425 ;
     RECT  98.1 75.307 99.897 75.425 ;
     RECT  18.615 75.271 20.862 75.433 ;
     RECT  34.164 75.397 35.694 75.433 ;
     RECT  4.32 75.263 6.966 75.461 ;
     RECT  18.615 75.433 21.078 75.461 ;
     RECT  22.86 75.299 26.802 75.461 ;
     RECT  5.22 75.461 6.966 75.497 ;
     RECT  34.164 75.433 35.766 75.505 ;
     RECT  11.016 75.425 12.042 75.533 ;
     RECT  19.908 75.461 21.078 75.533 ;
     RECT  56.415 74.687 56.697 75.541 ;
     RECT  55.728 75.541 56.697 75.631 ;
     RECT  4.32 75.461 4.482 75.659 ;
     RECT  23.4 75.461 26.802 75.659 ;
     RECT  48.564 75.119 49.266 75.659 ;
     RECT  59.148 75.397 59.562 75.659 ;
     RECT  37.872 74.461 37.89 75.667 ;
     RECT  38.664 74.849 38.898 75.667 ;
     RECT  45.36 75.199 47.286 75.695 ;
     RECT  23.4 75.659 25.758 75.725 ;
     RECT  55.476 75.631 56.697 75.739 ;
     RECT  11.196 75.533 12.042 75.767 ;
     RECT  17.352 73.535 17.37 75.775 ;
     RECT  34.164 75.505 35.874 75.775 ;
     RECT  37.872 75.667 38.898 75.775 ;
     RECT  45.504 75.695 47.286 75.775 ;
     RECT  91.512 74.849 91.602 75.775 ;
     RECT  86.292 75.227 86.31 75.811 ;
     RECT  91.188 75.775 91.602 75.811 ;
     RECT  17.352 75.775 17.694 75.835 ;
     RECT  26.604 75.659 26.802 75.839 ;
     RECT  103.968 72.185 103.986 75.839 ;
     RECT  17.352 75.835 17.802 75.901 ;
     RECT  18.615 75.461 18.897 75.901 ;
     RECT  74.124 74.849 75.222 75.901 ;
     RECT  76.032 74.957 76.23 75.901 ;
     RECT  5.22 75.497 6.858 75.929 ;
     RECT  14.508 75.155 15.498 75.929 ;
     RECT  17.352 75.901 18.897 75.929 ;
     RECT  19.908 75.533 21.006 75.929 ;
     RECT  23.4 75.725 25.182 75.929 ;
     RECT  26.604 75.839 26.73 75.929 ;
     RECT  68.364 74.885 68.85 75.929 ;
     RECT  90.648 75.811 91.602 75.929 ;
     RECT  92.916 75.425 94.734 75.929 ;
     RECT  26.604 75.929 26.622 75.965 ;
     RECT  82.332 75.191 85.05 75.965 ;
     RECT  49.032 75.659 49.266 75.973 ;
     RECT  50.184 75.191 50.202 75.973 ;
     RECT  50.94 75.191 51.297 75.973 ;
     RECT  82.332 75.965 84.438 75.973 ;
     RECT  11.628 75.767 12.042 76.001 ;
     RECT  19.908 75.929 20.898 76.001 ;
     RECT  87.156 75.227 88.002 76.001 ;
     RECT  67.215 74.885 67.497 76.009 ;
     RECT  68.364 75.929 68.382 76.009 ;
     RECT  72.072 74.909 73.026 76.045 ;
     RECT  77.472 74.147 80.262 76.045 ;
     RECT  82.26 75.973 84.438 76.045 ;
     RECT  85.932 75.811 86.31 76.045 ;
     RECT  5.256 75.929 6.858 76.073 ;
     RECT  25.164 75.929 25.182 76.073 ;
     RECT  14.832 75.929 15.498 76.081 ;
     RECT  55.296 75.739 56.697 76.081 ;
     RECT  77.04 76.045 80.262 76.081 ;
     RECT  82.188 76.045 84.438 76.081 ;
     RECT  93.42 75.929 94.626 76.109 ;
     RECT  85.896 76.045 86.31 76.171 ;
     RECT  20.016 76.001 20.898 76.199 ;
     RECT  34.02 75.775 36.342 76.199 ;
     RECT  37.224 75.775 38.898 76.199 ;
     RECT  62.82 75.397 63.018 76.199 ;
     RECT  85.896 76.171 86.454 76.199 ;
     RECT  90.648 75.929 91.53 76.199 ;
     RECT  67.215 76.009 68.382 76.207 ;
     RECT  23.4 75.929 24.426 76.235 ;
     RECT  77.004 76.081 80.262 76.243 ;
     RECT  82.152 76.081 84.438 76.243 ;
     RECT  11.628 76.001 11.97 76.271 ;
     RECT  65.88 74.155 65.898 76.279 ;
     RECT  66.672 76.207 68.382 76.279 ;
     RECT  71.64 76.045 73.026 76.279 ;
     RECT  61.815 75.119 62.097 76.315 ;
     RECT  14.832 76.081 15.678 76.343 ;
     RECT  7.815 75.263 8.478 76.351 ;
     RECT  54.756 76.081 56.697 76.351 ;
     RECT  64.872 76.315 64.89 76.351 ;
     RECT  65.88 76.279 68.382 76.351 ;
     RECT  74.124 75.901 76.23 76.351 ;
     RECT  76.968 76.243 80.262 76.351 ;
     RECT  90.648 76.199 91.494 76.351 ;
     RECT  24.015 76.235 24.426 76.379 ;
     RECT  20.016 76.199 20.034 76.397 ;
     RECT  88.815 74.183 89.097 76.411 ;
     RECT  5.724 76.073 6.858 76.441 ;
     RECT  31.752 76.081 31.77 76.441 ;
     RECT  58.104 76.081 58.122 76.441 ;
     RECT  59.22 75.659 59.562 76.441 ;
     RECT  61.308 76.315 62.097 76.441 ;
     RECT  71.244 76.279 73.026 76.459 ;
     RECT  17.676 75.929 18.897 76.469 ;
     RECT  11.628 76.271 11.718 76.505 ;
     RECT  70.992 76.459 73.026 76.505 ;
     RECT  14.904 76.343 15.678 76.513 ;
     RECT  31.14 76.441 31.77 76.513 ;
     RECT  74.124 76.351 80.262 76.513 ;
     RECT  88.815 76.411 89.658 76.513 ;
     RECT  90.504 76.351 91.494 76.513 ;
     RECT  87.408 76.001 88.002 76.541 ;
     RECT  54.612 76.351 56.697 76.549 ;
     RECT  61.02 76.441 62.097 76.549 ;
     RECT  11.628 76.505 11.646 76.577 ;
     RECT  97.452 76.315 97.47 76.585 ;
     RECT  98.244 75.425 99.897 76.585 ;
     RECT  57.672 76.441 59.562 76.621 ;
     RECT  17.676 76.469 17.874 76.637 ;
     RECT  17.676 76.637 17.694 76.649 ;
     RECT  54.144 76.549 56.697 76.649 ;
     RECT  71.568 76.505 73.026 76.649 ;
     RECT  29.415 74.417 29.697 76.699 ;
     RECT  60.984 76.549 62.097 76.711 ;
     RECT  62.82 76.199 62.946 76.711 ;
     RECT  96.552 76.621 96.57 76.711 ;
     RECT  97.452 76.585 99.897 76.711 ;
     RECT  57.672 76.621 59.994 76.739 ;
     RECT  60.984 76.711 62.946 76.739 ;
     RECT  71.928 76.649 73.026 76.739 ;
     RECT  5.724 76.441 7.038 76.747 ;
     RECT  7.815 76.351 9.09 76.747 ;
     RECT  34.02 76.199 34.038 76.747 ;
     RECT  54.9 76.649 56.697 76.775 ;
     RECT  14.904 76.513 15.822 76.811 ;
     RECT  64.872 76.351 68.382 76.811 ;
     RECT  37.224 76.199 37.89 76.819 ;
     RECT  96.552 76.711 99.897 76.847 ;
     RECT  33.444 76.747 34.038 76.855 ;
     RECT  38.844 76.199 38.898 76.855 ;
     RECT  55.296 76.775 56.697 76.855 ;
     RECT  65.052 76.811 68.382 76.855 ;
     RECT  69.228 76.711 69.246 76.855 ;
     RECT  5.724 76.747 9.09 76.883 ;
     RECT  57.816 76.739 59.994 76.883 ;
     RECT  74.124 76.513 80.946 76.883 ;
     RECT  98.028 76.847 99.897 76.883 ;
     RECT  28.836 76.699 29.697 76.891 ;
     RECT  34.815 76.199 36.342 76.891 ;
     RECT  37.188 76.819 37.89 76.891 ;
     RECT  60.984 76.739 62.73 76.919 ;
     RECT  65.052 76.855 69.246 76.919 ;
     RECT  14.904 76.811 15.066 77.009 ;
     RECT  15.84 76.855 15.858 77.009 ;
     RECT  65.052 76.919 66.186 77.009 ;
     RECT  96.552 76.847 97.29 77.009 ;
     RECT  133.812 72.185 133.83 77.009 ;
     RECT  67.215 76.919 69.246 77.017 ;
     RECT  5.724 76.883 8.097 77.045 ;
     RECT  8.856 76.883 9.09 77.045 ;
     RECT  82.044 76.243 84.438 77.045 ;
     RECT  82.044 77.045 82.17 77.053 ;
     RECT  98.208 76.883 99.897 77.081 ;
     RECT  28.836 76.891 29.79 77.089 ;
     RECT  76.104 76.883 80.946 77.089 ;
     RECT  81.792 77.053 82.17 77.089 ;
     RECT  95.796 76.549 95.814 77.089 ;
     RECT  31.104 76.513 31.77 77.125 ;
     RECT  38.844 76.855 39.258 77.125 ;
     RECT  72.396 76.739 73.026 77.125 ;
     RECT  38.844 77.125 39.402 77.161 ;
     RECT  67.215 77.017 69.57 77.161 ;
     RECT  72.396 77.125 73.206 77.189 ;
     RECT  133.344 77.089 133.362 77.189 ;
     RECT  30.816 77.125 31.77 77.213 ;
     RECT  38.664 77.161 39.402 77.213 ;
     RECT  86.148 76.199 86.454 77.251 ;
     RECT  5.724 77.045 6.21 77.279 ;
     RECT  6.948 77.045 8.097 77.279 ;
     RECT  8.856 77.045 8.946 77.279 ;
     RECT  38.844 77.213 39.402 77.279 ;
     RECT  70.776 76.981 70.794 77.279 ;
     RECT  72.615 77.189 73.206 77.279 ;
     RECT  95.796 77.089 96.354 77.279 ;
     RECT  99 77.081 99.897 77.279 ;
     RECT  40.215 75.155 40.497 77.287 ;
     RECT  86.112 77.251 86.454 77.287 ;
     RECT  87.444 76.541 88.002 77.287 ;
     RECT  8.856 77.279 8.874 77.315 ;
     RECT  34.815 76.891 37.89 77.315 ;
     RECT  55.296 76.855 56.862 77.315 ;
     RECT  30.852 77.213 31.77 77.351 ;
     RECT  40.215 77.287 40.734 77.359 ;
     RECT  32.904 76.855 34.038 77.387 ;
     RECT  30.924 77.351 31.77 77.423 ;
     RECT  59.544 76.883 59.994 77.431 ;
     RECT  60.984 76.919 62.097 77.431 ;
     RECT  5.724 77.279 6.03 77.453 ;
     RECT  30.924 77.423 31.374 77.459 ;
     RECT  57.816 76.883 58.734 77.459 ;
     RECT  86.112 77.287 88.002 77.459 ;
     RECT  107.532 68.369 107.55 77.459 ;
     RECT  32.94 77.387 34.038 77.501 ;
     RECT  88.815 76.513 91.494 77.501 ;
     RECT  14.904 77.009 14.922 77.521 ;
     RECT  28.836 77.089 29.898 77.521 ;
     RECT  6.948 77.279 7.074 77.549 ;
     RECT  14.544 77.521 14.922 77.549 ;
     RECT  33.336 77.501 34.038 77.549 ;
     RECT  37.368 77.315 37.89 77.549 ;
     RECT  38.844 77.279 39.006 77.549 ;
     RECT  56.052 77.315 56.862 77.549 ;
     RECT  14.544 77.549 14.886 77.557 ;
     RECT  20.016 77.515 20.034 77.557 ;
     RECT  40.14 77.359 40.734 77.557 ;
     RECT  42.804 74.219 42.822 77.557 ;
     RECT  43.632 75.155 43.65 77.557 ;
     RECT  93.42 76.109 94.59 77.557 ;
     RECT  6.948 77.549 6.966 77.585 ;
     RECT  28.836 77.521 29.97 77.593 ;
     RECT  14.22 77.557 14.886 77.597 ;
     RECT  67.215 77.161 69.642 77.621 ;
     RECT  42.804 77.557 43.65 77.629 ;
     RECT  49.032 75.973 51.297 77.629 ;
     RECT  52.416 75.119 52.434 77.629 ;
     RECT  31.14 77.459 31.374 77.657 ;
     RECT  25.812 76.621 25.83 77.665 ;
     RECT  66.168 77.009 66.186 77.665 ;
     RECT  67.215 77.621 68.418 77.665 ;
     RECT  92.916 77.557 94.59 77.665 ;
     RECT  31.212 77.657 31.374 77.693 ;
     RECT  19.98 77.557 20.034 77.701 ;
     RECT  24.015 76.379 24.297 77.701 ;
     RECT  34.815 77.315 36.342 77.701 ;
     RECT  92.484 77.665 94.59 77.701 ;
     RECT  24.015 77.701 24.57 77.819 ;
     RECT  31.212 77.693 31.338 77.819 ;
     RECT  34.704 77.701 36.342 77.819 ;
     RECT  40.068 77.557 40.734 77.819 ;
     RECT  65.052 77.009 65.07 77.819 ;
     RECT  76.104 77.089 82.17 77.819 ;
     RECT  98.208 77.081 98.226 77.819 ;
     RECT  13.215 74.651 13.497 77.827 ;
     RECT  59.544 77.431 62.097 77.827 ;
     RECT  31.248 77.819 31.338 77.855 ;
     RECT  34.815 77.819 36.342 77.855 ;
     RECT  38.844 77.549 38.97 77.855 ;
     RECT  89.82 77.501 91.494 77.855 ;
     RECT  33.336 77.549 33.858 77.891 ;
     RECT  59.544 77.827 62.154 77.891 ;
     RECT  45.504 75.775 47.358 77.899 ;
     RECT  95.796 77.279 96.174 77.899 ;
     RECT  37.476 77.549 37.89 77.927 ;
     RECT  20.952 77.701 20.97 77.935 ;
     RECT  42.804 77.629 44.298 77.935 ;
     RECT  91.224 77.855 91.494 77.935 ;
     RECT  95.472 77.899 96.174 77.935 ;
     RECT  97.236 77.009 97.254 77.935 ;
     RECT  82.908 77.045 84.438 77.963 ;
     RECT  92.484 77.701 94.626 77.963 ;
     RECT  12.96 77.827 13.497 77.971 ;
     RECT  18.615 76.469 18.897 77.971 ;
     RECT  19.98 77.701 20.07 77.971 ;
     RECT  20.88 77.935 20.97 77.971 ;
     RECT  25.56 77.665 25.83 77.971 ;
     RECT  49.032 77.629 52.434 77.971 ;
     RECT  83.34 77.963 84.438 77.971 ;
     RECT  91.224 77.935 91.638 77.971 ;
     RECT  93.132 77.963 94.626 77.971 ;
     RECT  74.124 76.883 75.222 77.999 ;
     RECT  40.068 77.819 40.626 78.043 ;
     RECT  42.768 77.935 44.37 78.043 ;
     RECT  45.504 77.899 47.718 78.043 ;
     RECT  12.708 77.971 13.497 78.089 ;
     RECT  39.96 78.043 40.626 78.089 ;
     RECT  42.768 78.043 47.718 78.089 ;
     RECT  59.544 77.891 61.002 78.089 ;
     RECT  74.34 77.999 75.222 78.089 ;
     RECT  76.104 77.819 76.59 78.089 ;
     RECT  83.34 77.971 84.762 78.089 ;
     RECT  86.184 77.459 88.002 78.089 ;
     RECT  89.82 77.855 90.09 78.089 ;
     RECT  91.224 77.971 91.782 78.089 ;
     RECT  95.436 77.935 96.174 78.089 ;
     RECT  76.104 78.089 76.482 78.125 ;
     RECT  95.796 78.089 95.814 78.125 ;
     RECT  54.288 78.061 54.306 78.133 ;
     RECT  40.032 78.089 40.626 78.161 ;
     RECT  45.576 78.089 47.358 78.161 ;
     RECT  83.34 78.089 84.438 78.161 ;
     RECT  18.615 77.971 20.97 78.169 ;
     RECT  54.216 78.133 54.306 78.169 ;
     RECT  22.824 78.097 22.842 78.197 ;
     RECT  33.84 77.891 33.858 78.197 ;
     RECT  49.032 77.971 52.974 78.197 ;
     RECT  61.815 77.891 62.154 78.197 ;
     RECT  97.236 77.935 97.506 78.205 ;
     RECT  18.432 78.169 20.97 78.233 ;
     RECT  42.768 78.089 43.65 78.233 ;
     RECT  60.876 78.089 61.002 78.233 ;
     RECT  19.908 78.233 20.97 78.241 ;
     RECT  40.032 78.161 40.497 78.269 ;
     RECT  28.836 77.593 30.114 78.331 ;
     RECT  54.216 78.169 54.342 78.331 ;
     RECT  56.052 77.549 56.754 78.331 ;
     RECT  57.816 77.459 58.338 78.331 ;
     RECT  18.432 78.233 19.17 78.359 ;
     RECT  19.908 78.241 21.042 78.359 ;
     RECT  34.815 77.855 35.55 78.359 ;
     RECT  55.296 77.315 55.314 78.359 ;
     RECT  77.364 77.819 82.17 78.359 ;
     RECT  28.836 78.331 30.15 78.368 ;
     RECT  21.024 78.359 21.042 78.395 ;
     RECT  25.092 77.971 25.83 78.395 ;
     RECT  34.815 78.359 35.406 78.395 ;
     RECT  83.34 78.161 84.222 78.395 ;
     RECT  87.228 78.089 88.002 78.395 ;
     RECT  25.452 78.395 25.83 78.403 ;
     RECT  14.256 77.597 14.886 78.439 ;
     RECT  87.336 78.395 88.002 78.467 ;
     RECT  18.432 78.359 19.062 78.475 ;
     RECT  25.452 78.403 25.902 78.475 ;
     RECT  26.784 78.403 26.802 78.475 ;
     RECT  54.216 78.331 54.558 78.475 ;
     RECT  25.452 78.475 26.802 78.503 ;
     RECT  45.576 78.161 47.142 78.503 ;
     RECT  38.844 77.855 38.898 78.511 ;
     RECT  56.052 78.331 58.338 78.511 ;
     RECT  88.815 77.501 89.097 78.511 ;
     RECT  89.82 78.089 89.982 78.511 ;
     RECT  34.815 78.395 35.226 78.601 ;
     RECT  11.52 78.205 11.538 78.629 ;
     RECT  17.208 78.205 17.226 78.629 ;
     RECT  18.288 78.475 19.062 78.629 ;
     RECT  23.076 78.475 23.166 78.629 ;
     RECT  25.632 78.503 26.802 78.629 ;
     RECT  28.836 78.368 30.042 78.629 ;
     RECT  38.772 78.511 38.898 78.629 ;
     RECT  77.364 78.359 81.522 78.629 ;
     RECT  36.324 77.855 36.342 78.637 ;
     RECT  18.504 78.629 18.897 78.665 ;
     RECT  34.452 78.601 35.226 78.665 ;
     RECT  77.364 78.629 81.09 78.665 ;
     RECT  93.132 77.971 94.698 78.665 ;
     RECT  31.32 77.855 31.338 78.667 ;
     RECT  60.984 78.233 61.002 78.673 ;
     RECT  19.908 78.359 20.178 78.701 ;
     RECT  25.632 78.629 25.902 78.701 ;
     RECT  60.984 78.673 61.074 78.701 ;
     RECT  36.144 78.637 36.342 78.709 ;
     RECT  63.576 78.709 63.666 78.715 ;
     RECT  77.364 78.665 80.982 78.737 ;
     RECT  41.868 75.155 41.958 78.745 ;
     RECT  70.704 77.629 70.722 78.745 ;
     RECT  63.576 78.715 63.99 78.781 ;
     RECT  70.452 78.745 70.722 78.781 ;
     RECT  74.34 78.089 74.934 78.781 ;
     RECT  88.815 78.511 89.982 78.859 ;
     RECT  23.148 78.629 23.166 78.871 ;
     RECT  24.015 77.819 24.354 78.871 ;
     RECT  54.144 78.475 54.558 78.871 ;
     RECT  72.615 77.279 72.897 78.871 ;
     RECT  10.332 78.637 10.35 78.899 ;
     RECT  14.22 78.439 14.886 78.899 ;
     RECT  15.624 78.637 16.002 78.899 ;
     RECT  27.972 77.125 27.99 78.899 ;
     RECT  31.32 78.667 31.518 78.899 ;
     RECT  36.144 78.709 36.486 78.899 ;
     RECT  93.204 78.665 94.698 78.899 ;
     RECT  77.364 78.737 80.658 78.907 ;
     RECT  77.328 78.907 80.658 78.935 ;
     RECT  42.804 78.233 43.65 78.943 ;
     RECT  44.424 78.089 44.442 78.943 ;
     RECT  63.576 78.781 64.098 78.943 ;
     RECT  19.98 78.701 20.178 78.971 ;
     RECT  71.748 78.745 71.766 78.971 ;
     RECT  40.104 78.269 40.497 78.979 ;
     RECT  41.544 78.745 41.958 78.979 ;
     RECT  72.615 78.871 73.062 78.979 ;
     RECT  74.196 78.781 74.934 78.979 ;
     RECT  69.228 77.621 69.642 79.007 ;
     RECT  13.215 78.089 13.497 79.015 ;
     RECT  14.796 78.899 14.886 79.015 ;
     RECT  15.624 78.899 15.642 79.015 ;
     RECT  28.836 78.629 29.754 79.015 ;
     RECT  31.32 78.899 31.338 79.015 ;
     RECT  63.576 78.943 64.314 79.015 ;
     RECT  66.168 77.665 68.418 79.015 ;
     RECT  70.452 78.781 70.794 79.015 ;
     RECT  72.615 78.979 74.934 79.015 ;
     RECT  21.06 78.475 21.078 79.043 ;
     RECT  27.468 78.955 27.486 79.043 ;
     RECT  69.336 79.007 69.642 79.043 ;
     RECT  45.615 78.503 47.142 79.051 ;
     RECT  97.164 78.205 97.506 79.051 ;
     RECT  14.796 79.015 15.642 79.079 ;
     RECT  63.252 79.015 64.314 79.079 ;
     RECT  77.328 78.935 80.046 79.079 ;
     RECT  66.168 79.015 68.454 79.085 ;
     RECT  56.052 78.511 58.41 79.141 ;
     RECT  77.328 79.079 78.894 79.141 ;
     RECT  31.284 79.015 31.338 79.169 ;
     RECT  45.615 79.051 47.538 79.169 ;
     RECT  69.336 79.043 69.354 79.169 ;
     RECT  76.104 78.125 76.41 79.169 ;
     RECT  91.44 78.089 91.782 79.169 ;
     RECT  93.204 78.899 94.626 79.169 ;
     RECT  28.8 79.015 29.754 79.205 ;
     RECT  42.804 78.943 44.442 79.205 ;
     RECT  77.292 79.141 78.894 79.205 ;
     RECT  40.104 78.979 41.958 79.213 ;
     RECT  49.032 78.197 51.297 79.213 ;
     RECT  61.815 78.197 62.097 79.213 ;
     RECT  63.252 79.079 64.062 79.213 ;
     RECT  61.815 79.213 64.062 79.241 ;
     RECT  77.292 79.205 78.858 79.241 ;
     RECT  79.668 79.079 80.046 79.241 ;
     RECT  39.96 79.213 41.958 79.243 ;
     RECT  48.996 79.213 51.297 79.249 ;
     RECT  52.056 78.197 52.974 79.249 ;
     RECT  53.856 78.871 54.558 79.249 ;
     RECT  77.328 79.241 78.858 79.277 ;
     RECT  48.996 79.249 52.974 79.285 ;
     RECT  53.856 79.249 54.846 79.285 ;
     RECT  76.392 79.169 76.41 79.313 ;
     RECT  36.144 78.899 36.414 79.321 ;
     RECT  61.056 78.701 61.074 79.321 ;
     RECT  61.815 79.241 63.99 79.321 ;
     RECT  88.815 78.859 90.018 79.321 ;
     RECT  37.872 77.927 37.89 79.349 ;
     RECT  25.668 78.701 25.866 79.421 ;
     RECT  5.616 79.243 5.634 79.439 ;
     RECT  14.796 79.079 15.354 79.439 ;
     RECT  25.668 79.421 25.794 79.439 ;
     RECT  72.612 79.015 74.934 79.439 ;
     RECT  97.164 79.051 97.578 79.439 ;
     RECT  34.452 78.665 35.097 79.447 ;
     RECT  35.964 79.321 36.414 79.447 ;
     RECT  88.815 79.321 90.486 79.447 ;
     RECT  25.668 79.439 25.758 79.483 ;
     RECT  39.96 79.243 42.03 79.483 ;
     RECT  42.804 79.205 43.65 79.483 ;
     RECT  61.056 79.321 63.99 79.483 ;
     RECT  13.068 79.015 13.497 79.519 ;
     RECT  97.164 79.439 97.47 79.519 ;
     RECT  9.468 79.015 9.486 79.555 ;
     RECT  12.6 79.519 13.497 79.555 ;
     RECT  72.612 79.439 73.818 79.555 ;
     RECT  25.632 79.483 25.758 79.583 ;
     RECT  88.815 79.447 90.99 79.583 ;
     RECT  34.452 79.447 36.414 79.591 ;
     RECT  87.444 78.467 88.002 79.591 ;
     RECT  88.815 79.583 89.874 79.591 ;
     RECT  97.092 79.519 97.47 79.591 ;
     RECT  72.504 79.555 73.818 79.613 ;
     RECT  48.996 79.285 54.846 79.619 ;
     RECT  5.796 79.591 5.922 79.681 ;
     RECT  7.02 79.591 7.038 79.681 ;
     RECT  18.615 78.665 18.897 79.681 ;
     RECT  19.98 78.971 19.998 79.681 ;
     RECT  23.148 78.871 24.354 79.681 ;
     RECT  29.415 79.205 29.754 79.681 ;
     RECT  30.78 79.591 30.906 79.681 ;
     RECT  11.124 79.591 11.142 79.709 ;
     RECT  14.94 79.439 15.354 79.709 ;
     RECT  18.615 79.681 19.998 79.709 ;
     RECT  34.272 79.591 36.414 79.709 ;
     RECT  45.615 79.169 47.358 79.709 ;
     RECT  50.184 79.619 54.846 79.709 ;
     RECT  87.444 79.591 89.874 79.709 ;
     RECT  90.648 79.583 90.918 79.709 ;
     RECT  97.02 79.591 97.47 79.709 ;
     RECT  38.844 78.629 38.898 79.717 ;
     RECT  65.232 78.637 65.25 79.717 ;
     RECT  66.168 79.085 68.202 79.717 ;
     RECT  11.988 79.555 13.497 79.745 ;
     RECT  34.272 79.709 36.378 79.745 ;
     RECT  72.615 79.613 73.818 79.745 ;
     RECT  90.648 79.709 90.774 79.745 ;
     RECT  56.052 79.141 58.734 79.753 ;
     RECT  18.615 79.709 19.89 79.781 ;
     RECT  65.232 79.717 68.202 79.781 ;
     RECT  53.856 79.709 54.846 79.789 ;
     RECT  87.444 79.709 89.73 79.817 ;
     RECT  11.988 79.745 12.042 79.825 ;
     RECT  55.872 79.753 58.734 79.853 ;
     RECT  16.884 79.243 16.902 79.861 ;
     RECT  44.748 79.789 44.838 79.889 ;
     RECT  48.996 79.619 49.086 79.889 ;
     RECT  73.764 79.745 73.818 79.889 ;
     RECT  16.884 79.861 17.046 79.951 ;
     RECT  34.272 79.745 35.838 79.951 ;
     RECT  16.884 79.951 17.73 79.979 ;
     RECT  19.764 79.781 19.89 79.979 ;
     RECT  50.184 79.709 53.118 79.979 ;
     RECT  60.912 79.483 63.99 79.979 ;
     RECT  65.232 79.781 65.538 79.979 ;
     RECT  77.328 79.277 78.57 79.979 ;
     RECT  87.984 79.817 89.73 79.979 ;
     RECT  91.764 79.169 91.782 79.979 ;
     RECT  97.02 79.709 97.326 79.979 ;
     RECT  56.052 79.853 58.734 79.987 ;
     RECT  8.82 79.555 9.486 80.015 ;
     RECT  29.415 79.681 30.906 80.023 ;
     RECT  31.788 79.951 31.806 80.023 ;
     RECT  33.948 79.951 35.838 80.023 ;
     RECT  26.856 79.861 26.874 80.051 ;
     RECT  50.184 79.979 53.046 80.051 ;
     RECT  53.856 79.789 54.882 80.051 ;
     RECT  10.224 79.717 10.242 80.059 ;
     RECT  38.412 79.717 38.898 80.059 ;
     RECT  97.02 79.979 97.182 80.059 ;
     RECT  17.712 79.979 17.73 80.095 ;
     RECT  70.452 79.015 71.442 80.095 ;
     RECT  96.372 80.059 97.182 80.095 ;
     RECT  45.615 79.709 46.854 80.123 ;
     RECT  87.984 79.979 89.694 80.123 ;
     RECT  39.96 79.483 43.65 80.131 ;
     RECT  44.748 79.889 44.766 80.131 ;
     RECT  86.4 79.789 86.418 80.131 ;
     RECT  17.712 80.095 17.802 80.141 ;
     RECT  17.712 80.141 17.73 80.159 ;
     RECT  70.164 80.095 71.442 80.159 ;
     RECT  5.796 79.681 7.038 80.221 ;
     RECT  7.815 77.279 8.097 80.221 ;
     RECT  9.684 80.059 10.242 80.221 ;
     RECT  29.415 80.023 31.806 80.221 ;
     RECT  38.412 80.059 38.97 80.221 ;
     RECT  8.82 80.015 8.838 80.249 ;
     RECT  9.684 80.221 10.386 80.249 ;
     RECT  33.66 80.023 35.838 80.249 ;
     RECT  45.615 80.123 46.782 80.249 ;
     RECT  50.508 80.051 53.01 80.249 ;
     RECT  53.856 80.051 54.846 80.249 ;
     RECT  79.668 79.241 79.686 80.249 ;
     RECT  87.984 80.123 89.658 80.249 ;
     RECT  5.04 80.095 5.058 80.251 ;
     RECT  5.796 80.221 8.097 80.251 ;
     RECT  86.4 80.131 86.49 80.251 ;
     RECT  5.04 80.251 8.097 80.257 ;
     RECT  37.944 80.221 38.97 80.257 ;
     RECT  70.992 80.159 71.442 80.257 ;
     RECT  65.52 79.979 65.538 80.285 ;
     RECT  87.984 80.249 89.586 80.285 ;
     RECT  9.792 80.249 10.386 80.291 ;
     RECT  63.936 79.979 63.99 80.293 ;
     RECT  66.708 79.781 68.202 80.321 ;
     RECT  85.68 80.251 86.49 80.321 ;
     RECT  5.04 80.257 8.154 80.333 ;
     RECT  63.936 80.293 64.53 80.333 ;
     RECT  29.415 80.221 32.526 80.357 ;
     RECT  37.944 80.257 39.042 80.357 ;
     RECT  39.96 80.131 44.766 80.357 ;
     RECT  70.992 80.257 71.694 80.357 ;
     RECT  5.04 80.333 6.894 80.365 ;
     RECT  95.76 80.095 97.182 80.365 ;
     RECT  71.1 80.357 71.694 80.401 ;
     RECT  72.615 79.745 72.954 80.401 ;
     RECT  31.968 80.357 32.31 80.429 ;
     RECT  33.768 80.249 35.838 80.429 ;
     RECT  39.96 80.357 43.902 80.429 ;
     RECT  71.1 80.401 72.954 80.429 ;
     RECT  73.8 79.889 73.818 80.429 ;
     RECT  9.972 80.291 10.386 80.443 ;
     RECT  11.376 79.825 12.042 80.443 ;
     RECT  25.632 79.583 25.686 80.443 ;
     RECT  37.944 80.357 38.898 80.485 ;
     RECT  4.968 80.365 6.894 80.519 ;
     RECT  9.972 80.443 12.042 80.519 ;
     RECT  25.632 80.443 26.154 80.519 ;
     RECT  29.415 80.357 31.23 80.519 ;
     RECT  71.1 80.429 71.262 80.519 ;
     RECT  83.34 78.395 83.697 80.519 ;
     RECT  95.652 80.365 97.182 80.519 ;
     RECT  10.188 80.519 12.042 80.527 ;
     RECT  22.464 79.681 24.354 80.527 ;
     RECT  95.652 80.519 97.074 80.555 ;
     RECT  34.344 80.429 35.838 80.563 ;
     RECT  34.344 80.563 35.91 80.599 ;
     RECT  90.648 79.745 90.666 80.627 ;
     RECT  95.652 80.555 97.038 80.627 ;
     RECT  4.968 80.519 6.822 80.635 ;
     RECT  15.192 79.709 15.354 80.635 ;
     RECT  25.632 80.519 25.65 80.635 ;
     RECT  81.072 80.491 81.09 80.635 ;
     RECT  95.652 80.627 96.39 80.635 ;
     RECT  10.188 80.527 12.258 80.663 ;
     RECT  31.968 80.429 31.986 80.663 ;
     RECT  52.128 80.249 52.902 80.663 ;
     RECT  87.984 80.285 89.478 80.663 ;
     RECT  71.1 80.519 71.118 80.669 ;
     RECT  21.744 80.527 24.354 80.671 ;
     RECT  48.996 79.889 49.014 80.671 ;
     RECT  56.052 79.987 58.77 80.671 ;
     RECT  91.908 80.587 92.43 80.671 ;
     RECT  93.24 79.169 94.626 80.671 ;
     RECT  39.96 80.429 40.59 80.699 ;
     RECT  59.544 78.089 60.138 80.699 ;
     RECT  37.44 80.485 38.898 80.717 ;
     RECT  15.156 80.635 15.354 80.761 ;
     RECT  26.928 80.443 26.946 80.761 ;
     RECT  56.052 80.671 58.806 80.761 ;
     RECT  87.984 80.663 89.097 80.761 ;
     RECT  4.716 80.635 6.822 80.789 ;
     RECT  10.188 80.663 12.006 80.789 ;
     RECT  16.488 80.131 16.506 80.789 ;
     RECT  21.564 80.671 24.354 80.789 ;
     RECT  37.44 80.717 37.962 80.789 ;
     RECT  60.912 79.979 63.198 80.789 ;
     RECT  72 80.429 72.954 80.789 ;
     RECT  85.68 80.321 86.418 80.789 ;
     RECT  37.44 80.789 37.638 80.797 ;
     RECT  55.656 80.761 58.806 80.825 ;
     RECT  10.188 80.789 11.394 80.861 ;
     RECT  15.156 80.761 15.642 80.861 ;
     RECT  38.844 80.717 38.898 80.861 ;
     RECT  72.036 80.789 72.954 80.861 ;
     RECT  91.908 80.671 94.626 80.861 ;
     RECT  95.58 80.635 96.39 80.861 ;
     RECT  37.368 80.797 37.638 80.897 ;
     RECT  4.716 80.789 6.174 80.905 ;
     RECT  15.156 80.861 15.21 80.905 ;
     RECT  55.656 80.825 58.41 80.905 ;
     RECT  74.556 79.439 74.934 80.905 ;
     RECT  95.58 80.861 95.814 80.905 ;
     RECT  25.2 80.635 25.65 80.909 ;
     RECT  21.744 80.789 24.354 80.933 ;
     RECT  37.62 80.897 37.638 80.933 ;
     RECT  91.908 80.861 94.497 80.933 ;
     RECT  85.68 80.789 86.13 80.941 ;
     RECT  4.32 80.905 6.174 80.957 ;
     RECT  6.156 80.957 6.174 81.059 ;
     RECT  41.544 80.429 43.902 81.059 ;
     RECT  55.548 80.905 58.41 81.059 ;
     RECT  91.908 80.933 93.33 81.059 ;
     RECT  95.256 80.905 95.814 81.059 ;
     RECT  48.204 80.671 49.014 81.095 ;
     RECT  91.908 81.059 93.258 81.095 ;
     RECT  59.544 80.699 60.066 81.131 ;
     RECT  55.548 81.059 57.438 81.167 ;
     RECT  50.508 80.249 51.297 81.175 ;
     RECT  59.544 81.131 59.922 81.175 ;
     RECT  63.18 80.789 63.198 81.175 ;
     RECT  63.936 80.333 64.314 81.175 ;
     RECT  29.415 80.519 30.978 81.203 ;
     RECT  26.928 80.761 27.09 81.211 ;
     RECT  48.312 81.095 49.014 81.211 ;
     RECT  50.04 81.175 51.297 81.211 ;
     RECT  80.964 80.635 81.09 81.211 ;
     RECT  43.632 81.059 43.902 81.301 ;
     RECT  44.748 80.357 44.766 81.301 ;
     RECT  17.28 80.905 17.298 81.307 ;
     RECT  4.32 80.957 5.382 81.329 ;
     RECT  14.544 80.905 15.21 81.329 ;
     RECT  17.28 81.307 17.658 81.329 ;
     RECT  22.464 80.933 24.297 81.329 ;
     RECT  26.784 81.211 27.09 81.329 ;
     RECT  79.992 80.905 80.01 81.329 ;
     RECT  17.352 81.329 17.658 81.365 ;
     RECT  80.748 81.211 81.306 81.365 ;
     RECT  80.748 81.365 80.982 81.374 ;
     RECT  59.22 81.175 59.922 81.401 ;
     RECT  20.088 80.563 20.106 81.409 ;
     RECT  59.256 81.401 59.922 81.437 ;
     RECT  20.088 81.409 20.214 81.445 ;
     RECT  45.615 80.249 46.602 81.445 ;
     RECT  77.436 79.979 78.57 81.445 ;
     RECT  85.5 80.941 86.13 81.445 ;
     RECT  91.908 81.095 92.61 81.445 ;
     RECT  27.9 80.671 27.918 81.473 ;
     RECT  58.212 81.059 58.41 81.473 ;
     RECT  79.848 81.337 79.866 81.485 ;
     RECT  39.96 80.699 40.497 81.499 ;
     RECT  48.312 81.211 51.297 81.509 ;
     RECT  17.532 81.365 17.658 81.571 ;
     RECT  84.96 81.445 86.13 81.571 ;
     RECT  91.872 81.445 92.61 81.571 ;
     RECT  10.188 80.861 10.674 81.599 ;
     RECT  17.532 81.571 17.694 81.599 ;
     RECT  19.62 81.445 20.538 81.599 ;
     RECT  45.615 81.445 46.746 81.599 ;
     RECT  57.42 81.167 57.438 81.599 ;
     RECT  91.296 81.571 92.61 81.599 ;
     RECT  53.856 80.249 54.738 81.607 ;
     RECT  55.548 81.167 56.697 81.607 ;
     RECT  60.912 80.789 62.19 81.607 ;
     RECT  63.18 81.175 64.314 81.607 ;
     RECT  67.176 80.321 68.202 81.607 ;
     RECT  87.732 80.761 89.097 81.607 ;
     RECT  34.344 80.599 36.198 81.643 ;
     RECT  4.32 81.329 5.166 81.679 ;
     RECT  13.215 79.745 13.497 81.679 ;
     RECT  14.544 81.329 15.174 81.679 ;
     RECT  60.912 81.607 64.314 81.679 ;
     RECT  4.176 81.679 5.166 81.715 ;
     RECT  9.288 81.175 9.306 81.715 ;
     RECT  66.816 81.607 68.202 81.715 ;
     RECT  84.888 81.571 86.13 81.715 ;
     RECT  94.068 80.933 94.497 81.715 ;
     RECT  95.256 81.059 95.346 81.715 ;
     RECT  48.456 81.509 51.297 81.743 ;
     RECT  34.272 81.643 36.198 81.751 ;
     RECT  38.88 80.861 38.898 81.751 ;
     RECT  39.672 81.499 40.497 81.751 ;
     RECT  66.384 81.715 68.85 81.751 ;
     RECT  41.544 81.059 42.858 81.779 ;
     RECT  48.456 81.743 49.626 81.779 ;
     RECT  58.392 81.473 58.41 81.779 ;
     RECT  91.296 81.599 91.926 81.841 ;
     RECT  4.104 81.715 5.166 81.869 ;
     RECT  15.948 81.445 15.966 81.869 ;
     RECT  42.588 81.779 42.858 81.869 ;
     RECT  48.636 81.779 49.626 81.869 ;
     RECT  53.856 81.607 56.697 81.869 ;
     RECT  84.708 81.715 86.13 81.869 ;
     RECT  94.068 81.715 95.346 81.869 ;
     RECT  13.215 81.679 15.174 81.877 ;
     RECT  66.384 81.751 68.958 81.877 ;
     RECT  83.415 80.519 83.697 81.877 ;
     RECT  87.696 81.607 89.097 81.877 ;
     RECT  55.656 81.869 56.697 81.905 ;
     RECT  87.336 81.877 89.097 81.941 ;
     RECT  70.164 80.159 70.182 81.949 ;
     RECT  85.464 81.869 86.13 81.977 ;
     RECT  77.148 81.445 78.57 82.021 ;
     RECT  13.068 81.877 15.174 82.049 ;
     RECT  85.68 81.977 86.13 82.049 ;
     RECT  4.104 81.869 4.662 82.139 ;
     RECT  7.02 81.985 7.038 82.139 ;
     RECT  19.944 81.599 20.538 82.139 ;
     RECT  41.544 81.779 41.778 82.139 ;
     RECT  48.636 81.869 49.446 82.139 ;
     RECT  53.856 81.869 54.846 82.139 ;
     RECT  82.656 81.877 84.582 82.139 ;
     RECT  42.732 81.869 42.858 82.147 ;
     RECT  43.632 81.301 44.766 82.147 ;
     RECT  52.884 80.663 52.902 82.147 ;
     RECT  53.856 82.139 54.414 82.147 ;
     RECT  59.292 81.437 59.922 82.147 ;
     RECT  60.66 81.679 64.314 82.147 ;
     RECT  66.204 81.877 68.958 82.147 ;
     RECT  74.448 80.905 74.934 82.183 ;
     RECT  48.636 82.139 48.654 82.211 ;
     RECT  59.292 82.147 64.314 82.211 ;
     RECT  34.056 81.751 36.198 82.219 ;
     RECT  59.292 82.211 63.882 82.219 ;
     RECT  85.788 82.049 86.13 82.219 ;
     RECT  87.336 81.941 87.786 82.219 ;
     RECT  42.732 82.147 44.766 82.247 ;
     RECT  58.716 82.219 63.882 82.247 ;
     RECT  4.104 82.139 4.482 82.255 ;
     RECT  14.76 82.049 15.174 82.255 ;
     RECT  34.056 82.219 36.486 82.255 ;
     RECT  66.132 82.147 68.958 82.255 ;
     RECT  74.448 82.183 75.114 82.255 ;
     RECT  82.656 82.139 84.402 82.255 ;
     RECT  73.8 82.255 75.114 82.291 ;
     RECT  76.068 82.147 76.086 82.291 ;
     RECT  77.148 82.021 78.642 82.291 ;
     RECT  58.716 82.247 63.666 82.319 ;
     RECT  77.148 82.291 78.822 82.319 ;
     RECT  85.788 82.219 87.786 82.319 ;
     RECT  34.056 82.255 36.522 82.363 ;
     RECT  73.8 82.291 76.086 82.381 ;
     RECT  3.672 82.255 4.482 82.409 ;
     RECT  9.216 81.715 9.306 82.409 ;
     RECT  12.096 82.291 12.114 82.409 ;
     RECT  13.068 82.049 13.662 82.409 ;
     RECT  34.02 82.363 36.522 82.409 ;
     RECT  66.132 82.255 69.066 82.409 ;
     RECT  73.8 82.381 76.266 82.409 ;
     RECT  82.584 82.255 84.402 82.409 ;
     RECT  76.068 82.409 76.266 82.445 ;
     RECT  85.788 82.319 87.714 82.445 ;
     RECT  16.488 82.411 16.506 82.451 ;
     RECT  38.88 81.751 40.497 82.453 ;
     RECT  77.22 82.319 78.822 82.453 ;
     RECT  10.656 81.599 10.674 82.481 ;
     RECT  76.248 82.445 76.266 82.481 ;
     RECT  82.584 82.409 83.697 82.481 ;
     RECT  27.072 81.329 27.09 82.489 ;
     RECT  29.415 81.203 30.258 82.489 ;
     RECT  72.615 80.861 72.897 82.489 ;
     RECT  9.216 82.409 9.234 82.525 ;
     RECT  13.068 82.409 13.497 82.525 ;
     RECT  45.615 81.599 46.422 82.525 ;
     RECT  77.22 82.453 79.002 82.525 ;
     RECT  74.052 82.409 75.114 82.541 ;
     RECT  38.664 82.453 40.497 82.553 ;
     RECT  66.132 82.409 68.67 82.553 ;
     RECT  74.124 82.541 75.114 82.553 ;
     RECT  17.676 81.599 17.694 82.561 ;
     RECT  60.948 82.319 63.666 82.589 ;
     RECT  74.124 82.553 75.042 82.589 ;
     RECT  90.576 81.841 91.926 82.589 ;
     RECT  26.748 82.489 27.09 82.651 ;
     RECT  52.128 80.663 52.146 82.651 ;
     RECT  52.884 82.147 54.414 82.651 ;
     RECT  56.052 81.905 56.697 82.651 ;
     RECT  80.784 81.374 80.982 82.651 ;
     RECT  3.672 82.409 4.374 82.679 ;
     RECT  12.384 82.525 13.497 82.679 ;
     RECT  17.28 82.561 17.694 82.679 ;
     RECT  26.748 82.651 27.306 82.679 ;
     RECT  77.22 82.525 79.326 82.679 ;
     RECT  80.28 82.651 80.982 82.679 ;
     RECT  83.232 82.481 83.697 82.679 ;
     RECT  85.896 82.445 87.714 82.679 ;
     RECT  94.068 81.869 95.202 82.679 ;
     RECT  71.568 82.219 71.586 82.699 ;
     RECT  74.124 82.589 74.97 82.715 ;
     RECT  77.22 82.679 79.146 82.751 ;
     RECT  42.768 82.247 44.766 82.759 ;
     RECT  71.568 82.699 71.838 82.759 ;
     RECT  72.615 82.489 73.242 82.759 ;
     RECT  80.28 82.679 80.802 82.759 ;
     RECT  90.576 82.589 91.458 82.759 ;
     RECT  42.768 82.759 44.838 82.787 ;
     RECT  74.916 82.715 74.934 82.787 ;
     RECT  88.815 81.941 89.097 82.789 ;
     RECT  9.108 82.525 9.234 82.795 ;
     RECT  14.76 82.255 15.606 82.795 ;
     RECT  25.632 80.909 25.65 82.795 ;
     RECT  26.856 82.679 27.306 82.795 ;
     RECT  93.276 82.789 93.294 82.795 ;
     RECT  74.124 82.715 74.142 82.823 ;
     RECT  23.112 81.329 24.297 82.831 ;
     RECT  26.856 82.795 27.522 82.831 ;
     RECT  29.415 82.489 30.798 82.831 ;
     RECT  57.852 82.219 57.87 82.831 ;
     RECT  58.716 82.319 59.922 82.831 ;
     RECT  14.292 82.795 15.606 82.859 ;
     RECT  44.748 82.787 44.838 82.859 ;
     RECT  52.128 82.651 54.414 82.921 ;
     RECT  71.568 82.759 73.242 82.921 ;
     RECT  11.556 82.525 11.574 82.949 ;
     RECT  19.944 82.139 20.07 82.949 ;
     RECT  25.632 82.795 26.046 82.949 ;
     RECT  26.856 82.831 27.594 82.949 ;
     RECT  38.772 82.553 40.497 82.949 ;
     RECT  42.768 82.787 43.686 82.949 ;
     RECT  50.688 81.743 51.297 82.949 ;
     RECT  63.648 82.589 63.666 82.949 ;
     RECT  77.22 82.751 78.678 82.949 ;
     RECT  79.92 82.759 80.802 82.949 ;
     RECT  90.36 82.759 91.458 82.949 ;
     RECT  94.068 82.679 94.77 82.949 ;
     RECT  17.28 82.679 17.442 82.957 ;
     RECT  23.112 82.831 24.57 82.957 ;
     RECT  25.632 82.949 25.686 82.957 ;
     RECT  45.615 82.525 46.71 82.957 ;
     RECT  88.815 82.789 89.586 82.957 ;
     RECT  90.36 82.949 91.242 82.957 ;
     RECT  34.272 82.409 36.486 82.985 ;
     RECT  42.768 82.949 43.614 82.985 ;
     RECT  56.052 82.651 56.934 82.985 ;
     RECT  57.852 82.831 59.922 82.985 ;
     RECT  66.132 82.553 68.202 82.985 ;
     RECT  88.815 82.957 91.242 82.985 ;
     RECT  19.944 82.949 19.998 82.993 ;
     RECT  71.424 82.921 73.242 82.993 ;
     RECT  38.772 82.949 39.042 83.021 ;
     RECT  42.768 82.985 43.398 83.021 ;
     RECT  19.908 82.993 19.998 83.029 ;
     RECT  29.088 82.831 30.798 83.029 ;
     RECT  47.808 82.957 47.826 83.029 ;
     RECT  52.128 82.921 54.738 83.029 ;
     RECT  70.164 81.949 70.29 83.029 ;
     RECT  93.132 82.795 93.294 83.029 ;
     RECT  19.836 83.029 19.998 83.057 ;
     RECT  77.796 82.949 78.534 83.057 ;
     RECT  80.1 82.949 80.334 83.057 ;
     RECT  3.672 82.679 4.194 83.065 ;
     RECT  9.072 82.795 9.234 83.065 ;
     RECT  18.615 79.781 18.897 83.065 ;
     RECT  93.06 83.029 93.294 83.065 ;
     RECT  94.068 82.949 94.497 83.065 ;
     RECT  15.516 82.859 15.606 83.093 ;
     RECT  85.896 82.679 87.606 83.093 ;
     RECT  42.768 83.021 43.326 83.101 ;
     RECT  45.615 82.957 46.782 83.101 ;
     RECT  56.052 82.985 56.862 83.101 ;
     RECT  59.904 82.985 59.922 83.101 ;
     RECT  60.948 82.589 62.802 83.101 ;
     RECT  70.164 83.029 70.362 83.101 ;
     RECT  81.72 82.993 81.738 83.101 ;
     RECT  47.808 83.029 47.898 83.129 ;
     RECT  52.128 83.029 54.81 83.129 ;
     RECT  77.796 83.057 78.297 83.129 ;
     RECT  80.1 83.057 80.118 83.129 ;
     RECT  16.848 82.957 17.442 83.191 ;
     RECT  57.852 82.985 59.166 83.191 ;
     RECT  23.112 82.957 25.686 83.213 ;
     RECT  10.476 83.065 10.494 83.219 ;
     RECT  12.384 82.679 12.474 83.219 ;
     RECT  16.488 83.191 17.442 83.219 ;
     RECT  19.836 83.057 19.962 83.219 ;
     RECT  22.104 82.831 22.122 83.219 ;
     RECT  23.112 83.213 24.57 83.219 ;
     RECT  25.632 83.213 25.686 83.219 ;
     RECT  34.272 82.985 35.658 83.219 ;
     RECT  45.615 83.101 46.998 83.219 ;
     RECT  52.128 83.129 54.414 83.219 ;
     RECT  55.836 83.101 56.862 83.219 ;
     RECT  71.316 82.993 73.242 83.219 ;
     RECT  81.72 83.101 81.954 83.219 ;
     RECT  85.896 83.093 87.354 83.219 ;
     RECT  88.815 82.985 91.134 83.219 ;
     RECT  93.06 83.065 94.497 83.219 ;
     RECT  23.112 83.219 24.297 83.221 ;
     RECT  34.272 83.219 35.406 83.227 ;
     RECT  21.096 83.029 21.114 83.255 ;
     RECT  72.576 83.219 73.242 83.255 ;
     RECT  88.815 83.219 90.918 83.255 ;
     RECT  57.744 83.191 59.166 83.291 ;
     RECT  81.72 83.219 81.738 83.291 ;
     RECT  6.84 82.255 6.858 83.299 ;
     RECT  85.896 83.219 86.814 83.327 ;
     RECT  6.84 83.299 6.93 83.335 ;
     RECT  10.296 83.227 10.314 83.335 ;
     RECT  16.488 83.219 16.506 83.363 ;
     RECT  86.796 83.327 86.814 83.363 ;
     RECT  88.815 83.255 90.45 83.363 ;
     RECT  93.132 83.219 94.497 83.363 ;
     RECT  6.804 83.335 6.93 83.371 ;
     RECT  66.132 82.985 67.497 83.371 ;
     RECT  71.316 83.219 71.802 83.371 ;
     RECT  57.744 83.291 57.942 83.399 ;
     RECT  45.615 83.219 46.062 83.405 ;
     RECT  3.492 83.065 4.194 83.489 ;
     RECT  6.12 83.371 6.93 83.489 ;
     RECT  10.008 83.335 10.314 83.489 ;
     RECT  22.176 83.221 24.297 83.489 ;
     RECT  26.856 82.949 27.522 83.489 ;
     RECT  33.624 83.227 35.406 83.489 ;
     RECT  57.924 83.399 57.942 83.489 ;
     RECT  90.36 83.363 90.45 83.489 ;
     RECT  93.636 83.363 94.497 83.489 ;
     RECT  31.896 83.029 31.914 83.533 ;
     RECT  41.76 82.139 41.778 83.533 ;
     RECT  42.732 83.101 43.326 83.533 ;
     RECT  26.856 83.489 27.378 83.569 ;
     RECT  22.5 83.489 24.297 83.597 ;
     RECT  33.624 83.489 35.334 83.597 ;
     RECT  38.772 83.021 38.79 83.597 ;
     RECT  5.904 83.569 5.922 83.605 ;
     RECT  7.815 80.333 8.154 83.605 ;
     RECT  8.892 83.065 9.234 83.605 ;
     RECT  55.836 83.219 56.754 83.605 ;
     RECT  65.52 83.371 67.497 83.605 ;
     RECT  22.5 83.597 23.13 83.633 ;
     RECT  41.76 83.533 43.326 83.633 ;
     RECT  52.128 83.219 54.162 83.633 ;
     RECT  55.26 83.605 56.754 83.633 ;
     RECT  31.896 83.533 32.634 83.641 ;
     RECT  33.624 83.597 35.097 83.641 ;
     RECT  26.784 83.569 27.378 83.669 ;
     RECT  69.84 83.101 70.362 83.669 ;
     RECT  7.164 83.605 9.234 83.731 ;
     RECT  10.008 83.489 10.026 83.731 ;
     RECT  29.088 83.029 31.122 83.731 ;
     RECT  31.896 83.641 35.097 83.731 ;
     RECT  7.164 83.731 10.026 83.759 ;
     RECT  25.668 83.219 25.686 83.767 ;
     RECT  29.088 83.731 35.097 83.795 ;
     RECT  58.68 83.291 59.166 83.803 ;
     RECT  59.904 83.101 62.802 83.803 ;
     RECT  69.948 83.669 70.362 83.803 ;
     RECT  71.244 83.371 71.802 83.803 ;
     RECT  7.164 83.759 9.702 83.831 ;
     RECT  58.68 83.803 62.802 83.831 ;
     RECT  43.236 83.633 43.326 83.875 ;
     RECT  59.112 83.831 62.802 83.903 ;
     RECT  25.668 83.767 26.046 83.911 ;
     RECT  29.088 83.795 32.634 83.911 ;
     RECT  40.215 82.949 40.497 83.911 ;
     RECT  41.76 83.633 42.462 83.911 ;
     RECT  52.128 83.633 52.902 83.939 ;
     RECT  20.88 83.911 20.898 84.001 ;
     RECT  7.164 83.831 9.414 84.029 ;
     RECT  14.292 82.859 14.778 84.029 ;
     RECT  15.588 83.093 15.606 84.029 ;
     RECT  43.236 83.875 43.542 84.029 ;
     RECT  59.112 83.903 59.742 84.029 ;
     RECT  36.468 82.985 36.486 84.043 ;
     RECT  20.88 84.001 21.078 84.065 ;
     RECT  59.292 84.029 59.742 84.065 ;
     RECT  12.384 83.219 12.402 84.073 ;
     RECT  13.215 82.679 13.497 84.073 ;
     RECT  55.26 83.633 56.697 84.073 ;
     RECT  21.06 84.065 21.078 84.101 ;
     RECT  12.384 84.073 13.497 84.109 ;
     RECT  69.948 83.803 71.802 84.109 ;
     RECT  72.615 83.255 73.242 84.109 ;
     RECT  2.415 73.841 2.697 84.145 ;
     RECT  3.492 83.489 4.086 84.145 ;
     RECT  18.216 83.065 18.897 84.145 ;
     RECT  47.88 83.129 47.898 84.145 ;
     RECT  25.668 83.911 26.118 84.173 ;
     RECT  28.8 83.911 32.634 84.173 ;
     RECT  14.292 84.029 14.418 84.181 ;
     RECT  47.34 84.145 48.186 84.181 ;
     RECT  11.772 84.109 13.497 84.271 ;
     RECT  49.608 84.181 49.626 84.271 ;
     RECT  11.232 84.271 13.497 84.299 ;
     RECT  28.8 84.173 31.734 84.299 ;
     RECT  32.616 84.173 32.634 84.299 ;
     RECT  60.552 83.903 62.802 84.299 ;
     RECT  63.684 83.803 64.098 84.299 ;
     RECT  33.48 83.795 35.097 84.317 ;
     RECT  30.636 84.299 30.942 84.335 ;
     RECT  44.748 82.859 44.766 84.335 ;
     RECT  12.492 84.299 13.497 84.343 ;
     RECT  14.22 84.181 14.418 84.343 ;
     RECT  25.668 84.173 26.046 84.343 ;
     RECT  36.468 84.043 37.098 84.343 ;
     RECT  40.215 83.911 42.462 84.343 ;
     RECT  26.856 83.669 27.378 84.371 ;
     RECT  33.66 84.317 35.097 84.371 ;
     RECT  47.052 84.181 48.186 84.371 ;
     RECT  69.948 84.109 73.242 84.371 ;
     RECT  11.232 84.299 11.538 84.415 ;
     RECT  49.608 84.271 50.202 84.415 ;
     RECT  51.015 82.949 51.297 84.415 ;
     RECT  36.468 84.343 37.242 84.451 ;
     RECT  38.016 84.181 38.034 84.451 ;
     RECT  52.56 83.939 52.902 84.451 ;
     RECT  53.64 83.633 54.162 84.451 ;
     RECT  52.56 84.451 54.162 84.479 ;
     RECT  39.924 84.343 42.462 84.541 ;
     RECT  43.236 84.029 43.254 84.541 ;
     RECT  5.652 83.605 5.922 84.569 ;
     RECT  12.492 84.343 14.418 84.569 ;
     RECT  17.28 84.415 17.298 84.569 ;
     RECT  23.112 83.633 23.13 84.569 ;
     RECT  30.78 84.335 30.942 84.569 ;
     RECT  31.716 84.299 31.734 84.569 ;
     RECT  47.124 84.371 48.186 84.569 ;
     RECT  36.468 84.451 38.034 84.605 ;
     RECT  45.615 83.405 45.99 84.605 ;
     RECT  47.556 84.569 48.042 84.605 ;
     RECT  52.956 84.479 54.162 84.611 ;
     RECT  65.484 83.605 67.497 84.611 ;
     RECT  49.608 84.415 51.297 84.641 ;
     RECT  59.328 84.065 59.742 84.649 ;
     RECT  60.552 84.299 62.586 84.649 ;
     RECT  47.628 84.605 47.646 84.677 ;
     RECT  2.415 84.145 4.086 84.685 ;
     RECT  22.788 84.613 23.022 84.685 ;
     RECT  53.64 84.611 54.162 84.685 ;
     RECT  55.008 84.073 56.697 84.685 ;
     RECT  65.7 84.611 67.497 84.685 ;
     RECT  22.572 84.685 23.022 84.713 ;
     RECT  59.328 84.649 62.586 84.713 ;
     RECT  69.948 84.371 71.838 84.713 ;
     RECT  7.164 84.029 8.154 84.721 ;
     RECT  19.944 83.219 19.962 84.721 ;
     RECT  69.948 84.713 71.766 84.721 ;
     RECT  12.528 84.569 14.418 84.811 ;
     RECT  12.528 84.811 15.03 84.839 ;
     RECT  15.984 84.685 16.002 84.839 ;
     RECT  18.18 84.145 18.897 84.839 ;
     RECT  22.572 84.713 22.95 84.839 ;
     RECT  26.856 84.371 26.874 84.839 ;
     RECT  36.468 84.605 37.782 84.839 ;
     RECT  65.7 84.685 67.626 84.839 ;
     RECT  69.552 84.721 71.766 84.839 ;
     RECT  33.66 84.371 33.93 84.875 ;
     RECT  37.008 84.839 37.782 84.875 ;
     RECT  38.736 84.721 38.754 84.875 ;
     RECT  39.924 84.541 43.254 84.875 ;
     RECT  69.552 84.839 71.226 84.875 ;
     RECT  11.052 84.415 11.538 84.883 ;
     RECT  59.328 84.713 60.066 84.883 ;
     RECT  69.552 84.875 70.614 84.893 ;
     RECT  13.176 84.839 15.03 84.911 ;
     RECT  16.92 84.811 16.938 84.911 ;
     RECT  53.64 84.685 56.697 84.911 ;
     RECT  66.168 84.839 67.626 84.911 ;
     RECT  59.076 84.883 60.066 84.941 ;
     RECT  25.632 84.343 26.046 84.955 ;
     RECT  21.636 84.811 21.654 84.991 ;
     RECT  69.552 84.893 70.074 85.099 ;
     RECT  13.176 84.911 14.814 85.109 ;
     RECT  40.215 84.875 43.254 85.109 ;
     RECT  69.408 85.099 70.074 85.109 ;
     RECT  50.148 84.641 51.297 85.145 ;
     RECT  66.636 84.911 67.626 85.145 ;
     RECT  69.408 85.109 69.966 85.145 ;
     RECT  37.008 84.875 37.674 85.181 ;
     RECT  53.712 84.911 56.697 85.217 ;
     RECT  2.415 84.685 4.374 85.225 ;
     RECT  21.096 84.991 21.654 85.261 ;
     RECT  22.572 84.839 22.842 85.261 ;
     RECT  34.815 84.371 35.097 85.261 ;
     RECT  42.48 85.109 43.254 85.261 ;
     RECT  37.008 85.181 37.026 85.289 ;
     RECT  69.48 85.145 69.966 85.289 ;
     RECT  18.615 84.839 18.897 85.339 ;
     RECT  9.108 84.029 9.414 85.379 ;
     RECT  13.176 85.109 14.562 85.379 ;
     RECT  16.56 84.955 16.578 85.379 ;
     RECT  19.944 84.721 19.998 85.379 ;
     RECT  21.096 85.261 22.842 85.379 ;
     RECT  33.48 85.261 33.606 85.379 ;
     RECT  40.215 85.109 41.67 85.379 ;
     RECT  42.48 85.261 43.47 85.379 ;
     RECT  33.48 85.379 33.498 85.381 ;
     RECT  24.015 83.597 24.297 85.387 ;
     RECT  25.632 84.955 26.622 85.387 ;
     RECT  31.608 85.339 31.626 85.415 ;
     RECT  42.48 85.379 42.498 85.415 ;
     RECT  53.748 85.217 56.697 85.415 ;
     RECT  69.48 85.289 69.858 85.415 ;
     RECT  33.408 85.381 33.498 85.421 ;
     RECT  22.14 85.379 22.842 85.451 ;
     RECT  24.015 85.387 26.622 85.451 ;
     RECT  30.78 84.569 30.798 85.451 ;
     RECT  33.48 85.421 33.498 85.451 ;
     RECT  38.772 85.261 38.79 85.451 ;
     RECT  41.652 85.379 41.67 85.451 ;
     RECT  43.452 85.379 43.47 85.451 ;
     RECT  50.724 85.145 51.297 85.451 ;
     RECT  61.164 84.713 62.586 85.451 ;
     RECT  10.332 84.883 11.538 85.459 ;
     RECT  34.74 85.261 35.097 85.487 ;
     RECT  69.48 85.415 69.822 85.487 ;
     RECT  61.164 85.451 62.097 85.495 ;
     RECT  69.588 85.487 69.822 85.523 ;
     RECT  2.415 85.225 4.59 85.531 ;
     RECT  5.652 84.569 5.67 85.531 ;
     RECT  6.804 84.721 8.154 85.531 ;
     RECT  10.332 85.459 11.97 85.531 ;
     RECT  18.615 85.339 19.026 85.531 ;
     RECT  59.292 84.941 60.066 85.531 ;
     RECT  61.092 85.495 62.097 85.531 ;
     RECT  10.26 85.531 11.97 85.559 ;
     RECT  5.652 85.531 8.154 85.649 ;
     RECT  10.26 85.559 10.926 85.649 ;
     RECT  11.952 85.559 11.97 85.649 ;
     RECT  24.015 85.451 26.262 85.649 ;
     RECT  54.288 85.415 56.697 85.649 ;
     RECT  69.696 85.523 69.822 85.649 ;
     RECT  14.22 85.379 14.562 85.685 ;
     RECT  18.615 85.531 19.17 85.685 ;
     RECT  59.292 85.531 62.097 85.685 ;
     RECT  69.696 85.649 69.714 85.685 ;
     RECT  6.768 85.649 8.154 85.693 ;
     RECT  9.108 85.379 9.234 85.693 ;
     RECT  66.636 85.145 67.554 85.721 ;
     RECT  0.18 85.531 0.198 85.729 ;
     RECT  2.415 85.531 4.698 85.765 ;
     RECT  5.652 85.649 5.814 85.765 ;
     RECT  18.615 85.685 19.026 85.801 ;
     RECT  20.916 85.459 20.934 85.829 ;
     RECT  2.415 85.765 5.814 85.919 ;
     RECT  6.768 85.693 9.234 85.919 ;
     RECT  19.98 85.379 19.998 85.919 ;
     RECT  24.015 85.649 25.794 85.919 ;
     RECT  66.672 85.721 67.554 85.919 ;
     RECT  18.36 85.801 19.026 85.955 ;
     RECT  54.504 85.649 56.697 85.955 ;
     RECT  10.548 85.649 10.926 85.991 ;
     RECT  2.415 85.919 3.402 85.999 ;
     RECT  54.828 85.955 56.697 86.027 ;
     RECT  18.36 85.955 18.954 86.035 ;
     RECT  10.908 85.991 10.926 86.063 ;
     RECT  24.015 85.919 25.11 86.063 ;
     RECT  18.18 86.035 18.954 86.099 ;
     RECT  14.4 85.685 14.562 86.161 ;
     RECT  17.1 85.963 17.118 86.189 ;
     RECT  18.18 86.099 18.897 86.189 ;
     RECT  24.015 86.063 24.498 86.189 ;
     RECT  66.924 85.919 67.554 86.189 ;
     RECT  66.924 86.189 67.497 86.225 ;
     RECT  12.348 85.891 12.366 86.305 ;
     RECT  13.176 85.379 13.497 86.305 ;
     RECT  2.304 85.999 3.402 86.333 ;
     RECT  4.356 85.919 5.814 86.333 ;
     RECT  14.4 86.161 14.85 86.333 ;
     RECT  8.928 85.919 9.234 86.431 ;
     RECT  12.348 86.305 13.497 86.431 ;
     RECT  59.292 85.685 59.958 86.431 ;
     RECT  60.732 85.685 62.097 86.431 ;
     RECT  5.652 86.333 5.814 86.459 ;
     RECT  6.768 85.919 8.154 86.459 ;
     RECT  7.776 86.459 8.154 86.495 ;
     RECT  59.292 86.431 62.097 86.495 ;
     RECT  66.996 86.225 67.497 86.495 ;
     RECT  5.652 86.459 5.742 86.531 ;
     RECT  8.928 86.431 9.522 86.531 ;
     RECT  11.844 86.431 13.497 86.531 ;
     RECT  5.652 86.531 5.67 86.573 ;
     RECT  4.356 86.333 4.77 86.603 ;
     RECT  6.768 86.459 6.93 86.603 ;
     RECT  12.384 86.531 13.497 86.611 ;
     RECT  4.356 86.603 4.59 86.621 ;
     RECT  16.452 86.197 16.47 86.729 ;
     RECT  21.636 86.305 21.654 86.729 ;
     RECT  12.384 86.611 14.31 86.765 ;
     RECT  59.904 86.495 62.097 86.765 ;
     RECT  0.18 85.729 0.558 86.779 ;
     RECT  15.408 86.701 15.426 86.801 ;
     RECT  17.712 86.701 17.73 86.801 ;
     RECT  59.904 86.765 60.606 86.801 ;
     RECT  2.304 86.333 3.078 86.845 ;
     RECT  1.692 86.845 3.078 86.861 ;
     RECT  0.18 86.779 0.63 86.873 ;
     RECT  54.9 86.027 56.697 86.881 ;
     RECT  0.216 86.873 0.63 86.909 ;
     RECT  14.292 86.765 14.31 86.909 ;
     RECT  16.236 86.737 16.254 86.909 ;
     RECT  12.384 86.765 13.497 86.999 ;
     RECT  59.904 86.801 60.066 86.999 ;
     RECT  1.692 86.861 2.862 87.005 ;
     RECT  6.768 86.603 6.858 87.005 ;
     RECT  6.804 87.005 6.858 87.035 ;
     RECT  59.904 86.999 59.922 87.035 ;
     RECT  0.216 86.909 0.342 87.053 ;
     RECT  4.356 86.621 4.374 87.053 ;
     RECT  12.384 86.999 12.402 87.071 ;
     RECT  4.284 87.067 4.302 87.107 ;
     RECT  7.776 86.495 8.097 87.107 ;
     RECT  0.216 87.053 0.234 87.149 ;
     RECT  6.804 87.035 6.822 87.149 ;
     RECT  2.415 87.005 2.862 87.179 ;
     RECT  54.72 86.881 56.697 87.259 ;
     RECT  54.576 87.259 56.697 87.269 ;
     RECT  55.404 87.269 56.697 87.539 ;
     RECT  54.576 87.269 54.594 87.575 ;
     RECT  55.404 87.539 55.53 87.809 ;
     RECT  55.404 87.809 55.422 87.845 ;
     RECT  2.415 87.179 2.697 98.027 ;
     RECT  7.815 87.107 8.097 98.027 ;
     RECT  13.215 86.999 13.497 98.027 ;
     RECT  18.615 86.189 18.897 98.027 ;
     RECT  24.015 86.189 24.297 98.027 ;
     RECT  29.415 84.299 29.697 98.027 ;
     RECT  34.815 85.487 35.097 98.027 ;
     RECT  40.215 85.379 40.497 98.027 ;
     RECT  45.615 84.605 45.897 98.027 ;
     RECT  51.015 85.451 51.297 98.027 ;
     RECT  56.415 87.539 56.697 98.027 ;
     RECT  61.815 86.765 62.097 98.027 ;
     RECT  67.215 86.495 67.497 98.027 ;
     RECT  72.615 84.371 72.897 98.027 ;
     RECT  78.015 83.129 78.297 98.027 ;
     RECT  83.415 82.679 83.697 98.027 ;
     RECT  88.815 83.363 89.097 98.027 ;
     RECT  94.215 83.489 94.497 98.027 ;
     RECT  99.615 77.279 99.897 98.027 ;
     RECT  105.015 72.023 105.297 98.027 ;
     RECT  110.415 68.243 110.697 98.027 ;
     RECT  115.815 67.483 116.097 98.027 ;
     RECT  121.215 67.483 121.497 98.027 ;
     RECT  126.615 74.921 126.897 98.027 ;
     RECT  132.015 67.163 132.297 98.027 ;
     RECT  137.415 69.449 137.697 98.027 ;
     RECT  142.815 68.009 143.097 98.027 ;
     RECT  148.215 68.243 148.497 98.027 ;
     RECT  153.615 68.405 153.897 98.027 ;
     RECT  2.415 98.027 2.505 98.297 ;
     RECT  7.815 98.027 7.905 98.297 ;
     RECT  13.215 98.027 13.305 98.297 ;
     RECT  18.615 98.027 18.705 98.297 ;
     RECT  24.015 98.027 24.105 98.297 ;
     RECT  29.415 98.027 29.505 98.297 ;
     RECT  34.815 98.027 34.905 98.297 ;
     RECT  40.215 98.027 40.305 98.297 ;
     RECT  45.615 98.027 45.705 98.297 ;
     RECT  51.015 98.027 51.105 98.297 ;
     RECT  56.415 98.027 56.505 98.297 ;
     RECT  61.815 98.027 61.905 98.297 ;
     RECT  67.215 98.027 67.305 98.297 ;
     RECT  72.615 98.027 72.705 98.297 ;
     RECT  78.015 98.027 78.105 98.297 ;
     RECT  83.415 98.027 83.505 98.297 ;
     RECT  88.815 98.027 88.905 98.297 ;
     RECT  94.215 98.027 94.305 98.297 ;
     RECT  99.615 98.027 99.705 98.297 ;
     RECT  105.015 98.027 105.105 98.297 ;
     RECT  110.415 98.027 110.505 98.297 ;
     RECT  115.815 98.027 115.905 98.297 ;
     RECT  121.215 98.027 121.305 98.297 ;
     RECT  126.615 98.027 126.705 98.297 ;
     RECT  132.015 98.027 132.105 98.297 ;
     RECT  137.415 98.027 137.505 98.297 ;
     RECT  142.815 98.027 142.905 98.297 ;
     RECT  148.215 98.027 148.305 98.297 ;
     RECT  153.615 98.027 153.705 98.297 ;
    LAYER M4 ;
     RECT  0.06 86.112 0.181 87.096 ;
     RECT  0.181 86.112 0.569 87.192 ;
     RECT  0.709 13.2 0.745 13.224 ;
     RECT  0.781 12.048 0.817 12.072 ;
     RECT  0.817 11.472 0.853 12.072 ;
     RECT  0.853 10.992 0.889 12.072 ;
     RECT  0.889 10.512 0.961 12.072 ;
     RECT  0.745 13.104 0.961 13.224 ;
     RECT  0.925 8.112 1.033 8.136 ;
     RECT  1.033 8.112 1.093 8.712 ;
     RECT  0.961 10.512 1.105 13.224 ;
     RECT  1.285 15.984 1.321 16.008 ;
     RECT  1.321 15.6 1.357 16.008 ;
     RECT  1.357 15.504 1.393 16.008 ;
     RECT  1.393 15.024 1.465 16.008 ;
     RECT  1.105 10.416 1.501 13.224 ;
     RECT  1.465 14.352 1.501 16.008 ;
     RECT  1.045 65.808 1.573 65.832 ;
     RECT  1.573 65.232 1.621 65.832 ;
     RECT  1.093 66.96 1.621 66.984 ;
     RECT  1.681 5.328 1.813 5.352 ;
     RECT  1.645 6.864 1.813 6.888 ;
     RECT  1.093 8.016 1.813 8.712 ;
     RECT  1.501 10.416 1.813 16.008 ;
     RECT  1.813 5.04 1.861 5.352 ;
     RECT  1.813 6.864 1.861 9.096 ;
     RECT  1.813 10.224 1.861 16.008 ;
     RECT  1.861 4.368 1.909 16.008 ;
     RECT  1.909 3.312 2.005 16.008 ;
     RECT  2.005 3.024 2.053 16.2 ;
     RECT  2.053 2.928 2.232 16.296 ;
     RECT  1.621 65.232 2.232 66.984 ;
     RECT  2.232 2.16 2.245 66.984 ;
     RECT  2.245 2.16 2.408 67.608 ;
     RECT  1.669 69.792 2.408 69.816 ;
     RECT  0.569 86.16 2.408 87.192 ;
     RECT  2.408 2.16 2.512 98.292 ;
     RECT  2.512 2.16 2.704 98.022 ;
     RECT  2.704 2.16 3.449 67.272 ;
     RECT  3.98 70.992 4.067 71.016 ;
     RECT  2.704 69.792 4.117 69.816 ;
     RECT  4.117 68.928 4.205 69.816 ;
     RECT  4.229 72.96 4.309 72.984 ;
     RECT  4.309 72.864 4.313 72.984 ;
     RECT  4.313 72.864 4.547 72.888 ;
     RECT  4.309 75.312 4.547 75.336 ;
     RECT  5.381 73.536 5.413 73.56 ;
     RECT  5.413 73.536 5.465 74.04 ;
     RECT  5.465 74.016 5.501 74.04 ;
     RECT  5.605 79.248 5.699 79.272 ;
     RECT  5.209 80.928 5.708 80.952 ;
     RECT  5.708 80.256 5.789 80.952 ;
     RECT  5.789 80.256 5.795 80.28 ;
     RECT  5.804 71.04 5.891 71.064 ;
     RECT  5.713 75.168 5.933 75.192 ;
     RECT  4.205 69.792 6.037 69.816 ;
     RECT  5.713 76.512 6.037 77.448 ;
     RECT  6.037 76.368 6.073 77.448 ;
     RECT  6.073 75.84 6.076 77.448 ;
     RECT  6.037 69.792 6.121 70.728 ;
     RECT  6.076 75.84 6.179 76.536 ;
     RECT  6.179 76.512 6.275 76.536 ;
     RECT  6.217 74.688 6.301 74.712 ;
     RECT  6.541 68.4 6.613 68.424 ;
     RECT  6.613 68.4 6.625 68.808 ;
     RECT  6.625 68.784 6.7 68.808 ;
     RECT  2.704 86.16 6.833 87.144 ;
     RECT  7.153 71.856 7.429 71.88 ;
     RECT  3.449 2.16 7.808 66.984 ;
     RECT  6.121 69.792 7.808 69.816 ;
     RECT  7.429 71.088 7.808 71.88 ;
     RECT  7.117 80.304 7.808 80.328 ;
     RECT  7.808 2.16 7.912 98.292 ;
     RECT  7.912 2.16 8.104 98.022 ;
     RECT  8.104 76.848 8.243 76.872 ;
     RECT  8.104 72.816 8.291 74.088 ;
     RECT  8.104 69.792 8.489 71.208 ;
     RECT  8.489 71.184 8.641 71.208 ;
     RECT  8.291 73.536 8.777 74.088 ;
     RECT  8.777 74.064 9.148 74.088 ;
     RECT  8.489 69.792 9.205 69.816 ;
     RECT  9.205 69.504 9.683 69.816 ;
     RECT  8.104 80.304 9.733 80.328 ;
     RECT  9.733 80.256 9.821 80.328 ;
     RECT  9.821 80.304 10.885 80.328 ;
     RECT  10.825 74.112 10.931 74.136 ;
     RECT  10.885 80.304 10.972 80.472 ;
     RECT  11.036 68.256 11.123 68.28 ;
     RECT  9.683 69.792 11.413 69.816 ;
     RECT  8.104 2.16 11.761 66.984 ;
     RECT  11.761 2.16 11.845 67.848 ;
     RECT  11.413 69.792 11.869 70.2 ;
     RECT  11.869 69.792 11.981 70.68 ;
     RECT  11.981 69.792 11.989 70.152 ;
     RECT  11.845 2.16 13.208 66.984 ;
     RECT  11.989 69.792 13.208 69.816 ;
     RECT  12.517 73.488 13.208 73.512 ;
     RECT  12.901 78.048 13.208 78.072 ;
     RECT  10.972 80.304 13.208 80.328 ;
     RECT  13.208 2.16 13.312 98.292 ;
     RECT  13.312 2.16 13.504 98.022 ;
     RECT  13.504 77.568 14.284 77.592 ;
     RECT  13.504 69.792 14.732 69.816 ;
     RECT  13.504 71.088 14.732 71.112 ;
     RECT  14.732 69.792 14.819 71.112 ;
     RECT  14.741 75.024 14.825 75.048 ;
     RECT  14.876 77.184 14.893 77.208 ;
     RECT  14.893 76.368 14.963 77.208 ;
     RECT  14.963 76.368 14.977 76.392 ;
     RECT  14.819 69.792 15.308 70.776 ;
     RECT  15.308 69.36 15.437 70.776 ;
     RECT  15.437 69.36 15.613 69.816 ;
     RECT  15.577 74.352 15.977 74.376 ;
     RECT  16.46 82.416 16.547 82.44 ;
     RECT  15.613 68.976 16.549 69.816 ;
     RECT  16.549 68.928 16.949 69.816 ;
     RECT  16.873 79.248 16.957 79.272 ;
     RECT  17.228 83.184 17.315 83.208 ;
     RECT  16.949 69.792 17.593 69.816 ;
     RECT  13.504 80.304 17.653 80.328 ;
     RECT  13.504 2.16 17.701 66.984 ;
     RECT  17.773 75.84 17.804 75.864 ;
     RECT  18.241 73.344 18.313 73.368 ;
     RECT  18.313 72.576 18.457 73.368 ;
     RECT  17.701 2.16 18.608 67.944 ;
     RECT  17.593 69.792 18.608 70.776 ;
     RECT  18.457 72.384 18.608 73.368 ;
     RECT  17.804 75.84 18.608 76.632 ;
     RECT  17.653 80.112 18.608 80.328 ;
     RECT  17.317 81.312 18.608 81.336 ;
     RECT  18.469 83.376 18.608 83.4 ;
     RECT  18.608 2.16 18.712 98.292 ;
     RECT  18.712 2.16 18.904 98.022 ;
     RECT  18.904 85.344 18.965 85.944 ;
     RECT  18.965 85.344 19.043 85.368 ;
     RECT  18.904 69.552 19.187 70.248 ;
     RECT  19.187 69.552 19.549 69.816 ;
     RECT  19.868 78.624 19.955 78.648 ;
     RECT  18.904 2.16 20.041 66.984 ;
     RECT  19.964 77.52 20.051 77.544 ;
     RECT  20.005 76.368 20.089 76.392 ;
     RECT  20.041 2.16 20.125 67.272 ;
     RECT  20.069 75.264 20.153 75.288 ;
     RECT  19.549 69.792 20.54 69.816 ;
     RECT  20.54 69.168 20.833 69.816 ;
     RECT  21.109 85.344 21.197 85.368 ;
     RECT  20.125 2.16 21.337 66.984 ;
     RECT  21.337 2.16 21.617 67.32 ;
     RECT  20.833 68.496 21.617 69.816 ;
     RECT  21.617 2.16 21.665 69.816 ;
     RECT  21.596 84.816 21.683 84.84 ;
     RECT  18.904 80.304 21.692 80.328 ;
     RECT  21.692 71.616 21.733 71.64 ;
     RECT  21.692 80.304 21.779 80.904 ;
     RECT  21.665 2.16 22.133 68.52 ;
     RECT  21.733 71.328 22.201 71.64 ;
     RECT  22.201 71.328 22.211 71.832 ;
     RECT  22.211 71.808 22.489 71.832 ;
     RECT  22.133 2.16 22.493 67.8 ;
     RECT  22.46 83.232 22.547 83.256 ;
     RECT  22.489 71.808 22.595 71.88 ;
     RECT  22.493 2.16 24.008 66.984 ;
     RECT  21.665 69.792 24.008 69.816 ;
     RECT  22.595 71.808 24.008 71.832 ;
     RECT  21.779 80.304 24.008 80.328 ;
     RECT  24.008 2.16 24.112 98.292 ;
     RECT  24.112 2.16 24.304 98.022 ;
     RECT  24.304 2.16 24.419 69.816 ;
     RECT  24.304 77.952 24.419 77.976 ;
     RECT  24.304 74.88 24.467 74.904 ;
     RECT  24.304 72.384 24.509 73.512 ;
     RECT  24.304 71.28 24.515 71.304 ;
     RECT  24.509 72.384 24.769 72.408 ;
     RECT  24.509 73.488 24.803 73.512 ;
     RECT  25.297 73.536 25.381 73.56 ;
     RECT  24.304 80.304 25.619 80.904 ;
     RECT  24.304 83.184 25.697 83.208 ;
     RECT  25.649 79.248 25.733 79.272 ;
     RECT  25.619 80.304 25.765 80.472 ;
     RECT  25.765 74.688 25.849 74.712 ;
     RECT  24.419 68.208 25.945 69.816 ;
     RECT  25.621 70.896 25.945 70.92 ;
     RECT  25.945 68.208 26.029 70.92 ;
     RECT  25.729 75.696 26.243 75.72 ;
     RECT  25.765 79.392 26.243 80.472 ;
     RECT  26.029 70.896 26.741 70.92 ;
     RECT  26.413 84.96 26.771 84.984 ;
     RECT  26.029 68.208 26.921 69.816 ;
     RECT  26.243 80.304 26.957 80.472 ;
     RECT  26.773 71.136 27.209 71.16 ;
     RECT  26.773 82.896 27.233 82.92 ;
     RECT  27.233 82.656 27.317 82.92 ;
     RECT  27.317 82.752 27.361 82.776 ;
     RECT  27.349 78.96 27.497 78.984 ;
     RECT  28.748 79.152 28.825 79.176 ;
     RECT  24.419 2.16 29.408 66.984 ;
     RECT  26.921 68.208 29.408 68.232 ;
     RECT  26.921 69.792 29.408 69.816 ;
     RECT  29.249 73.92 29.408 73.944 ;
     RECT  28.796 76.704 29.408 76.728 ;
     RECT  28.825 78.576 29.408 79.176 ;
     RECT  26.957 80.304 29.408 80.328 ;
     RECT  29.269 83.616 29.408 83.64 ;
     RECT  29.408 2.16 29.512 98.292 ;
     RECT  29.512 2.16 29.704 98.022 ;
     RECT  29.704 79.824 29.881 80.904 ;
     RECT  29.704 77.568 29.981 78.408 ;
     RECT  29.981 78.336 29.987 78.408 ;
     RECT  29.881 79.968 30.028 80.904 ;
     RECT  29.987 78.336 30.227 78.36 ;
     RECT  29.704 68.208 30.757 70.728 ;
     RECT  30.757 68.208 30.844 71.064 ;
     RECT  30.769 84.528 30.853 84.552 ;
     RECT  30.805 77.184 30.889 77.208 ;
     RECT  30.028 79.968 30.917 80.424 ;
     RECT  31.004 74.064 31.021 74.088 ;
     RECT  31.021 73.536 31.091 74.088 ;
     RECT  31.091 73.536 31.165 73.56 ;
     RECT  31.165 72.96 31.249 73.56 ;
     RECT  30.844 68.208 31.313 70.728 ;
     RECT  31.237 79.056 31.324 79.08 ;
     RECT  30.917 80.304 31.331 80.424 ;
     RECT  29.704 2.16 31.417 66.984 ;
     RECT  31.313 68.208 31.417 68.232 ;
     RECT  31.249 73.536 31.421 73.56 ;
     RECT  31.417 2.16 31.523 68.232 ;
     RECT  31.573 85.344 31.66 85.368 ;
     RECT  31.489 78.672 31.907 78.696 ;
     RECT  31.313 69.792 32.285 70.728 ;
     RECT  32.929 77.472 33.059 77.496 ;
     RECT  33.164 73.392 33.251 73.416 ;
     RECT  33.325 72.384 33.409 72.408 ;
     RECT  33.349 85.392 33.437 85.416 ;
     RECT  33.061 84.288 33.509 84.312 ;
     RECT  31.523 2.16 33.541 66.984 ;
     RECT  31.523 68.208 33.541 68.232 ;
     RECT  33.577 85.344 33.661 85.368 ;
     RECT  31.331 80.304 33.733 80.328 ;
     RECT  33.637 74.784 33.788 74.808 ;
     RECT  33.733 80.112 33.82 80.328 ;
     RECT  34.009 82.368 34.501 82.392 ;
     RECT  33.541 2.16 34.645 68.232 ;
     RECT  32.285 69.792 34.645 69.816 ;
     RECT  34.645 2.16 34.808 69.816 ;
     RECT  33.788 74.784 34.808 74.856 ;
     RECT  33.82 80.304 34.808 80.328 ;
     RECT  34.501 81.6 34.808 82.392 ;
     RECT  34.808 2.16 34.912 98.292 ;
     RECT  34.912 2.16 35.104 98.022 ;
     RECT  35.104 82.272 35.237 82.296 ;
     RECT  35.104 76.8 35.315 77.544 ;
     RECT  35.104 74.784 35.381 74.808 ;
     RECT  35.104 71.232 35.699 71.256 ;
     RECT  35.104 2.16 35.741 69.816 ;
     RECT  35.315 76.8 35.957 76.824 ;
     RECT  35.741 2.16 36.001 68.232 ;
     RECT  36.476 77.184 36.563 77.208 ;
     RECT  36.001 68.208 36.757 68.232 ;
     RECT  36.001 2.16 37.249 66.984 ;
     RECT  36.757 68.208 37.249 68.28 ;
     RECT  35.104 80.304 37.381 80.328 ;
     RECT  37.249 2.16 37.613 68.28 ;
     RECT  37.069 84.048 37.619 84.072 ;
     RECT  37.613 68.208 37.789 68.28 ;
     RECT  37.789 68.208 38.045 68.712 ;
     RECT  37.381 80.304 38.108 80.52 ;
     RECT  38.108 80.304 38.195 80.712 ;
     RECT  38.389 72.912 38.477 72.936 ;
     RECT  38.636 77.184 38.723 77.208 ;
     RECT  38.684 72.432 38.771 72.456 ;
     RECT  37.613 2.16 38.789 66.984 ;
     RECT  38.045 68.208 38.789 68.232 ;
     RECT  38.972 82.992 39.059 83.016 ;
     RECT  38.789 2.16 39.301 68.232 ;
     RECT  35.741 69.792 39.301 69.816 ;
     RECT  39.877 77.568 39.925 77.592 ;
     RECT  39.301 2.16 40.208 69.816 ;
     RECT  39.829 71.472 40.208 71.496 ;
     RECT  39.925 77.568 40.208 78.072 ;
     RECT  38.195 80.304 40.208 80.328 ;
     RECT  39.661 81.504 40.208 81.528 ;
     RECT  39.985 82.656 40.208 82.68 ;
     RECT  40.208 2.16 40.312 98.292 ;
     RECT  40.312 2.16 40.504 98.022 ;
     RECT  40.504 79.728 40.684 80.328 ;
     RECT  40.504 84.048 40.925 84.936 ;
     RECT  40.504 2.16 41.027 68.328 ;
     RECT  40.504 73.728 41.075 73.752 ;
     RECT  41.027 68.208 41.411 68.328 ;
     RECT  40.925 84.048 41.429 84.12 ;
     RECT  41.429 84.096 41.753 84.12 ;
     RECT  40.684 79.824 41.941 80.328 ;
     RECT  41.941 79.824 41.957 81.048 ;
     RECT  41.957 79.248 42.028 81.048 ;
     RECT  42.028 79.248 42.041 80.328 ;
     RECT  41.027 2.16 42.721 66.984 ;
     RECT  41.411 68.208 42.721 68.232 ;
     RECT  42.469 84.96 42.755 84.984 ;
     RECT  42.721 2.16 42.833 68.232 ;
     RECT  42.041 79.536 43.049 80.328 ;
     RECT  43.004 82.56 43.091 82.584 ;
     RECT  43.049 79.824 43.193 80.328 ;
     RECT  43.261 78 43.333 78.024 ;
     RECT  43.333 77.808 43.345 78.024 ;
     RECT  43.345 77.808 43.517 77.832 ;
     RECT  43.837 70.752 43.873 70.776 ;
     RECT  43.873 70.272 43.921 70.776 ;
     RECT  42.833 2.16 44.053 66.984 ;
     RECT  42.833 68.208 44.053 68.232 ;
     RECT  44.156 73.776 44.243 73.8 ;
     RECT  44.053 2.16 44.435 68.232 ;
     RECT  43.921 70.272 44.633 70.296 ;
     RECT  44.435 68.208 44.953 68.232 ;
     RECT  44.953 68.208 45.013 68.472 ;
     RECT  45.169 74.064 45.253 74.088 ;
     RECT  44.869 78.048 45.452 78.072 ;
     RECT  45.452 77.472 45.493 78.072 ;
     RECT  44.435 2.16 45.608 66.984 ;
     RECT  45.013 68.208 45.608 68.952 ;
     RECT  45.301 72.144 45.608 72.168 ;
     RECT  45.253 73.776 45.608 74.088 ;
     RECT  45.493 77.472 45.608 78.648 ;
     RECT  43.193 80.304 45.608 80.328 ;
     RECT  45.608 2.16 45.712 98.292 ;
     RECT  45.712 2.16 45.904 98.022 ;
     RECT  45.904 79.248 46.081 79.272 ;
     RECT  45.904 83.376 46.108 83.4 ;
     RECT  45.904 77.184 46.181 77.976 ;
     RECT  45.904 68.208 46.217 68.712 ;
     RECT  46.181 77.184 46.396 77.208 ;
     RECT  45.904 71.856 46.397 72.168 ;
     RECT  46.397 72.144 46.892 72.168 ;
     RECT  46.892 72.144 46.979 72.36 ;
     RECT  45.904 2.16 47.081 66.984 ;
     RECT  46.979 72.144 47.081 72.168 ;
     RECT  47.701 84.24 47.788 84.264 ;
     RECT  48.62 81.84 48.707 81.864 ;
     RECT  45.904 80.304 49.244 80.328 ;
     RECT  46.217 68.208 49.273 68.232 ;
     RECT  49.237 69.264 49.273 69.288 ;
     RECT  49.244 79.44 49.331 80.328 ;
     RECT  49.333 76.608 49.421 76.632 ;
     RECT  49.021 75.312 49.571 75.336 ;
     RECT  49.597 72.576 49.948 72.6 ;
     RECT  50.053 77.28 50.129 77.304 ;
     RECT  50.389 71.664 50.492 71.688 ;
     RECT  50.129 77.28 50.54 78.072 ;
     RECT  49.273 68.208 51.008 69.288 ;
     RECT  50.492 71.472 51.008 71.688 ;
     RECT  50.849 72.816 51.008 73.512 ;
     RECT  50.54 77.28 51.008 78.36 ;
     RECT  49.331 80.304 51.008 80.328 ;
     RECT  50.101 85.104 51.008 85.128 ;
     RECT  51.008 67.488 51.112 98.292 ;
     RECT  47.081 2.16 51.2 66.408 ;
     RECT  51.112 67.488 51.2 98.022 ;
     RECT  51.2 2.16 51.304 98.022 ;
     RECT  51.304 68.208 51.401 68.328 ;
     RECT  51.304 78.336 52.163 78.36 ;
     RECT  52.441 83.28 52.453 83.304 ;
     RECT  51.304 79.44 52.625 80.328 ;
     RECT  52.453 83.28 52.661 84.36 ;
     RECT  52.661 83.28 52.841 83.304 ;
     RECT  53.089 70.704 53.173 70.728 ;
     RECT  52.945 84.576 54.092 84.6 ;
     RECT  54.092 84.576 54.173 85.272 ;
     RECT  54.173 85.248 54.179 85.272 ;
     RECT  51.401 68.304 54.241 68.328 ;
     RECT  54.241 68.304 54.565 68.568 ;
     RECT  54.524 87.264 54.611 87.288 ;
     RECT  54.241 74.88 54.707 74.904 ;
     RECT  54.745 76.128 54.829 76.152 ;
     RECT  54.565 68.208 55.177 68.568 ;
     RECT  55.177 68.208 55.196 68.712 ;
     RECT  54.709 73.536 55.253 73.56 ;
     RECT  55.196 68.064 55.283 68.712 ;
     RECT  55.196 70.656 55.283 70.68 ;
     RECT  55.283 68.208 55.321 68.712 ;
     RECT  55.244 85.104 55.331 85.128 ;
     RECT  55.493 74.784 55.676 74.808 ;
     RECT  55.321 68.208 56.408 68.76 ;
     RECT  56.012 72.912 56.408 72.936 ;
     RECT  55.676 74.784 56.408 75.576 ;
     RECT  55.82 76.896 56.408 76.92 ;
     RECT  52.625 80.304 56.408 80.328 ;
     RECT  56.408 67.488 56.512 98.292 ;
     RECT  51.304 2.16 56.6 66.408 ;
     RECT  56.512 67.488 56.6 98.022 ;
     RECT  56.6 2.16 56.704 98.022 ;
     RECT  56.704 78.672 56.981 80.328 ;
     RECT  56.704 74.304 57.347 74.328 ;
     RECT  56.704 71.28 57.637 71.304 ;
     RECT  57.788 70.272 57.875 70.296 ;
     RECT  56.704 2.16 57.917 66.408 ;
     RECT  56.981 79.632 57.917 80.328 ;
     RECT  58.021 76.464 58.108 76.488 ;
     RECT  56.704 68.208 58.124 68.232 ;
     RECT  58.124 83.088 58.211 83.112 ;
     RECT  58.124 67.68 58.417 68.232 ;
     RECT  58.412 74.016 58.499 74.04 ;
     RECT  58.417 67.68 58.501 69 ;
     RECT  58.021 72.24 58.705 72.264 ;
     RECT  58.693 70.848 58.817 70.872 ;
     RECT  58.705 72.144 58.961 72.264 ;
     RECT  58.961 72.144 58.997 72.168 ;
     RECT  58.501 67.68 59.029 68.232 ;
     RECT  58.693 84.912 59.105 84.936 ;
     RECT  59.029 67.44 59.413 68.232 ;
     RECT  57.917 66.384 59.525 66.408 ;
     RECT  59.413 67.392 59.525 68.232 ;
     RECT  59.525 66.384 59.609 68.232 ;
     RECT  59.609 67.392 59.933 68.232 ;
     RECT  59.933 68.112 60.373 68.232 ;
     RECT  60.353 85.536 60.437 85.56 ;
     RECT  60.373 68.112 60.46 68.664 ;
     RECT  57.917 2.16 60.581 65.256 ;
     RECT  60.421 71.04 60.581 71.064 ;
     RECT  60.572 77.472 60.659 77.496 ;
     RECT  61.532 85.296 61.573 85.32 ;
     RECT  60.46 68.112 61.808 68.232 ;
     RECT  61.669 76.752 61.808 76.776 ;
     RECT  57.917 80.304 61.808 80.328 ;
     RECT  61.573 84.336 61.808 85.32 ;
     RECT  61.808 67.488 61.912 98.292 ;
     RECT  59.609 66.384 62 66.408 ;
     RECT  61.912 67.488 62 98.022 ;
     RECT  62 66.384 62.104 98.022 ;
     RECT  62.104 81.84 62.483 81.864 ;
     RECT  62.104 66.384 62.524 68.664 ;
     RECT  62.524 67.824 63.052 68.664 ;
     RECT  63.205 72.192 63.292 72.216 ;
     RECT  62.104 71.04 63.425 71.064 ;
     RECT  63.404 69.456 63.491 69.48 ;
     RECT  63.052 67.824 63.565 68.472 ;
     RECT  63.493 79.152 63.565 79.176 ;
     RECT  63.169 82.416 63.677 82.44 ;
     RECT  63.565 67.392 63.827 68.472 ;
     RECT  63.827 67.968 63.857 68.472 ;
     RECT  63.781 73.728 63.868 73.752 ;
     RECT  63.565 78.72 64.001 79.176 ;
     RECT  64.001 79.152 64.073 79.176 ;
     RECT  63.673 83.808 64.153 83.832 ;
     RECT  64.364 73.92 64.451 74.328 ;
     RECT  62.104 80.304 64.541 80.328 ;
     RECT  64.309 69.984 64.573 70.008 ;
     RECT  64.573 69.552 64.657 70.008 ;
     RECT  64.657 69.984 64.681 70.008 ;
     RECT  64.681 69.984 64.829 70.632 ;
     RECT  64.451 73.92 64.865 73.944 ;
     RECT  64.837 76.752 64.924 76.776 ;
     RECT  65.461 84.576 65.548 84.6 ;
     RECT  65.725 83.712 66.131 83.736 ;
     RECT  63.857 67.968 66.697 68.232 ;
     RECT  66.697 67.968 66.877 68.952 ;
     RECT  66.697 82.416 66.949 82.44 ;
     RECT  66.877 67.824 67.208 68.952 ;
     RECT  66.949 81.696 67.208 82.44 ;
     RECT  66.613 84.816 67.208 84.84 ;
     RECT  67.208 67.488 67.312 98.292 ;
     RECT  62.524 66.384 67.4 66.408 ;
     RECT  67.312 67.488 67.4 98.022 ;
     RECT  67.4 66.384 67.504 98.022 ;
     RECT  67.504 67.824 67.619 69 ;
     RECT  67.504 82.416 67.709 82.44 ;
     RECT  67.504 71.328 67.781 71.928 ;
     RECT  67.619 67.968 67.969 69 ;
     RECT  67.504 77.52 68.332 77.544 ;
     RECT  67.504 79.056 68.483 79.08 ;
     RECT  67.781 71.856 68.825 71.928 ;
     RECT  68.773 74.352 68.861 74.376 ;
     RECT  67.504 66.384 68.885 66.408 ;
     RECT  67.969 67.968 68.885 68.424 ;
     RECT  68.825 71.904 68.897 71.928 ;
     RECT  68.885 66.384 68.969 68.424 ;
     RECT  68.969 67.968 69.397 68.424 ;
     RECT  69.349 85.104 69.437 85.128 ;
     RECT  69.397 67.968 69.481 69 ;
     RECT  69.781 74.592 69.869 74.616 ;
     RECT  70.549 84.864 70.636 84.888 ;
     RECT  70.693 79.248 71.077 79.272 ;
     RECT  71.077 79.152 71.089 79.272 ;
     RECT  71.089 79.152 71.164 79.656 ;
     RECT  71.164 79.248 71.237 79.656 ;
     RECT  70.981 76.464 71.267 76.488 ;
     RECT  71.237 79.632 71.267 79.656 ;
     RECT  71.089 80.64 71.267 80.664 ;
     RECT  71.269 83.616 71.353 83.64 ;
     RECT  71.269 71.616 71.737 71.64 ;
     RECT  71.737 71.424 71.773 71.64 ;
     RECT  71.773 71.424 71.845 71.688 ;
     RECT  71.845 71.424 72.449 71.832 ;
     RECT  69.481 67.968 72.608 68.232 ;
     RECT  72.449 71.424 72.608 72.36 ;
     RECT  72.229 74.352 72.608 74.376 ;
     RECT  72.469 79.584 72.608 79.608 ;
     RECT  71.809 82.704 72.608 82.728 ;
     RECT  72.608 67.488 72.712 98.292 ;
     RECT  68.969 66.384 72.8 66.408 ;
     RECT  72.712 67.488 72.8 98.022 ;
     RECT  72.8 66.384 72.904 98.022 ;
     RECT  72.904 71.424 73.109 71.88 ;
     RECT  72.904 74.64 73.181 74.904 ;
     RECT  72.904 67.968 73.369 68.424 ;
     RECT  73.109 71.712 73.475 71.88 ;
     RECT  73.181 74.64 73.613 74.664 ;
     RECT  74.005 82.512 74.092 82.536 ;
     RECT  74.005 74.544 74.099 74.568 ;
     RECT  72.904 79.296 74.117 79.32 ;
     RECT  74.149 71.184 74.245 71.208 ;
     RECT  74.245 71.088 74.331 71.208 ;
     RECT  74.401 77.808 74.617 77.832 ;
     RECT  74.617 77.616 74.693 77.832 ;
     RECT  74.693 77.616 75.013 77.64 ;
     RECT  74.653 82.56 75.053 82.584 ;
     RECT  75.013 77.568 75.125 77.64 ;
     RECT  75.125 77.568 75.197 77.592 ;
     RECT  74.331 71.04 75.251 71.208 ;
     RECT  73.369 67.968 75.541 68.232 ;
     RECT  75.541 67.968 75.629 68.664 ;
     RECT  75.251 71.184 75.665 71.208 ;
     RECT  76.309 77.424 76.529 77.448 ;
     RECT  76.549 73.2 76.636 73.224 ;
     RECT  77.425 79.008 77.785 79.032 ;
     RECT  75.629 67.968 78.008 68.232 ;
     RECT  76.993 73.584 78.008 73.608 ;
     RECT  77.785 78.912 78.008 79.032 ;
     RECT  77.18 82.896 78.008 82.92 ;
     RECT  78.008 67.488 78.112 98.292 ;
     RECT  72.904 66.384 78.2 66.408 ;
     RECT  78.112 67.488 78.2 98.022 ;
     RECT  78.2 66.384 78.304 98.022 ;
     RECT  78.304 70.944 78.445 70.968 ;
     RECT  78.304 67.968 78.46 68.664 ;
     RECT  78.304 82.464 79.013 82.728 ;
     RECT  78.304 78.912 79.121 78.936 ;
     RECT  79.013 82.704 79.187 82.728 ;
     RECT  78.304 75.888 79.373 76.296 ;
     RECT  79.373 75.888 79.409 75.96 ;
     RECT  78.304 77.376 79.441 77.448 ;
     RECT  79.441 77.328 79.621 77.448 ;
     RECT  78.46 67.968 79.657 68.232 ;
     RECT  79.793 81.456 79.877 81.48 ;
     RECT  79.621 77.28 80.093 77.448 ;
     RECT  79.409 75.888 80.201 75.912 ;
     RECT  78.304 66.384 80.3 66.408 ;
     RECT  79.657 67.392 80.3 68.232 ;
     RECT  80.3 66.384 80.387 68.232 ;
     RECT  80.387 67.392 80.561 68.232 ;
     RECT  80.093 77.28 80.705 77.304 ;
     RECT  81.601 70.08 82.124 70.104 ;
     RECT  82.124 70.08 82.181 70.68 ;
     RECT  82.181 70.656 82.211 70.68 ;
     RECT  83.149 73.872 83.185 73.896 ;
     RECT  80.561 67.968 83.408 68.232 ;
     RECT  83.185 73.872 83.408 74.088 ;
     RECT  83.113 75.888 83.408 75.912 ;
     RECT  82.645 82.416 83.408 82.44 ;
     RECT  83.408 67.488 83.512 98.292 ;
     RECT  80.387 66.384 83.6 66.408 ;
     RECT  83.512 67.488 83.6 98.022 ;
     RECT  83.6 66.384 83.704 98.022 ;
     RECT  83.704 73.872 83.729 74.088 ;
     RECT  83.729 73.872 83.801 74.04 ;
     RECT  83.704 77.952 83.843 77.976 ;
     RECT  83.801 73.872 84.413 73.896 ;
     RECT  83.704 70.56 84.556 70.584 ;
     RECT  85.525 71.424 85.612 71.448 ;
     RECT  85.628 80.256 86.051 80.28 ;
     RECT  83.704 66.384 86.393 66.408 ;
     RECT  83.704 67.968 86.444 68.232 ;
     RECT  86.029 73.584 86.497 73.608 ;
     RECT  86.444 67.968 86.531 68.952 ;
     RECT  86.485 78.048 86.572 78.072 ;
     RECT  86.497 73.344 86.645 73.608 ;
     RECT  86.677 71.76 86.861 71.784 ;
     RECT  86.531 67.968 87.185 68.28 ;
     RECT  87.073 77.376 87.365 77.4 ;
     RECT  87.301 70.416 87.388 70.44 ;
     RECT  87.5 72.72 87.613 72.744 ;
     RECT  88.028 80.064 88.081 80.088 ;
     RECT  87.613 72.72 88.268 72.984 ;
     RECT  88.081 80.064 88.765 80.232 ;
     RECT  87.185 67.968 88.808 68.232 ;
     RECT  87.781 71.376 88.808 71.4 ;
     RECT  88.268 72.672 88.808 72.984 ;
     RECT  88.765 80.016 88.808 80.232 ;
     RECT  88.808 67.488 88.912 98.292 ;
     RECT  88.912 67.488 89 98.022 ;
     RECT  89 67.218 89.104 98.022 ;
     RECT  89.104 82.8 89.597 82.824 ;
     RECT  89.104 78.864 89.651 78.936 ;
     RECT  89.104 76.416 89.713 76.44 ;
     RECT  89.651 78.864 90.073 78.888 ;
     RECT  89.104 77.472 90.083 77.496 ;
     RECT  90.613 82.128 90.7 82.152 ;
     RECT  91.292 74.4 91.379 74.424 ;
     RECT  89.104 67.968 91.501 68.808 ;
     RECT  91.573 77.952 91.66 77.976 ;
     RECT  91.501 67.968 91.667 69.672 ;
     RECT  91.667 67.968 91.763 68.808 ;
     RECT  91.853 82.56 91.937 82.584 ;
     RECT  92.396 80.592 92.483 80.616 ;
     RECT  91.573 71.472 92.509 71.496 ;
     RECT  92.645 75.312 92.729 75.336 ;
     RECT  92.509 71.472 92.765 71.64 ;
     RECT  91.763 67.968 92.821 68.664 ;
     RECT  92.437 70.08 92.821 70.104 ;
     RECT  92.765 71.616 92.917 71.64 ;
     RECT  92.821 67.968 92.945 70.104 ;
     RECT  92.917 71.616 92.981 72.168 ;
     RECT  92.945 69.456 93.107 70.104 ;
     RECT  92.981 71.856 93.133 72.168 ;
     RECT  93.109 77.952 93.877 77.976 ;
     RECT  92.945 67.968 94.208 68.232 ;
     RECT  93.107 69.552 94.208 70.104 ;
     RECT  93.133 72.144 94.208 72.168 ;
     RECT  93.877 77.904 94.208 77.976 ;
     RECT  93.253 82.8 94.208 82.824 ;
     RECT  94.208 67.488 94.312 98.292 ;
     RECT  94.312 67.488 94.4 98.022 ;
     RECT  94.4 67.218 94.504 98.022 ;
     RECT  94.504 77.904 94.565 77.976 ;
     RECT  94.504 75.696 94.709 75.72 ;
     RECT  94.504 73.824 94.787 74.712 ;
     RECT  94.504 69.312 95.116 69.336 ;
     RECT  94.787 74.688 95.257 74.712 ;
     RECT  94.565 77.904 95.501 77.928 ;
     RECT  95.605 80.592 95.692 80.616 ;
     RECT  96.145 69.552 96.509 69.576 ;
     RECT  96.901 76.896 97.121 76.92 ;
     RECT  94.504 67.968 97.369 67.992 ;
     RECT  97.369 67.248 97.453 67.992 ;
     RECT  97.381 0.24 97.765 0.264 ;
     RECT  97.765 0.048 97.955 0.264 ;
     RECT  97.955 0.048 98.021 0.168 ;
     RECT  98.089 75.312 98.173 75.336 ;
     RECT  98.437 73.872 98.524 73.896 ;
     RECT  97.453 67.968 99.068 67.992 ;
     RECT  99.068 67.968 99.608 68.184 ;
     RECT  99.397 70.272 99.608 70.296 ;
     RECT  99.133 73.776 99.608 73.8 ;
     RECT  99.608 67.488 99.712 98.292 ;
     RECT  99.712 67.488 99.8 98.022 ;
     RECT  99.8 67.218 99.904 98.022 ;
     RECT  99.904 69.552 100.081 71.064 ;
     RECT  100.081 69.552 100.261 70.392 ;
     RECT  99.904 67.872 100.307 68.136 ;
     RECT  100.261 70.128 100.685 70.392 ;
     RECT  100.685 70.368 100.801 70.392 ;
     RECT  100.307 67.872 100.973 67.992 ;
     RECT  100.973 67.968 103.273 67.992 ;
     RECT  103.273 67.968 103.82 68.424 ;
     RECT  103.82 67.968 103.907 68.808 ;
     RECT  103.813 71.856 103.907 71.88 ;
     RECT  103.907 67.968 104.293 67.992 ;
     RECT  104.293 67.488 104.965 67.992 ;
     RECT  104.965 67.488 105.008 68.184 ;
     RECT  105.008 67.488 105.112 98.292 ;
     RECT  105.112 67.488 105.2 98.022 ;
     RECT  105.2 67.218 105.304 98.022 ;
     RECT  105.304 67.824 105.443 68.184 ;
     RECT  105.304 69.984 105.491 70.008 ;
     RECT  105.443 67.92 106.585 68.184 ;
     RECT  106.585 67.872 106.697 68.184 ;
     RECT  106.697 67.872 107.941 67.896 ;
     RECT  107.941 67.872 108.028 68.184 ;
     RECT  108.028 67.872 109.093 67.896 ;
     RECT  109.093 67.872 109.181 68.184 ;
     RECT  109.181 67.872 110.408 68.088 ;
     RECT  110.408 67.488 110.512 98.292 ;
     RECT  110.512 67.488 110.6 98.022 ;
     RECT  110.6 67.218 110.704 98.022 ;
     RECT  110.704 67.968 114.661 67.992 ;
     RECT  114.661 67.296 114.797 67.992 ;
     RECT  114.797 67.968 115.808 67.992 ;
     RECT  115.808 67.488 115.912 98.292 ;
     RECT  115.912 67.488 116 98.022 ;
     RECT  116 67.218 116.104 98.022 ;
     RECT  116.104 67.248 116.345 67.992 ;
     RECT  116.345 67.968 117.733 67.992 ;
     RECT  117.733 67.824 117.821 68.376 ;
     RECT  117.821 67.824 118.465 67.992 ;
     RECT  118.465 67.344 118.549 67.992 ;
     RECT  118.549 67.968 121.208 67.992 ;
     RECT  121.208 67.488 121.312 98.292 ;
     RECT  121.312 67.488 121.4 98.022 ;
     RECT  121.4 67.218 121.504 98.022 ;
     RECT  60.581 2.16 123.912 65.07 ;
     RECT  123.912 2.928 123.984 16.296 ;
     RECT  123.984 2.928 124.115 15.336 ;
     RECT  124.115 3.024 124.163 15.336 ;
     RECT  98.021 0.048 125.993 0.072 ;
     RECT  125.989 2.064 126.209 2.088 ;
     RECT  124.163 3.12 126.608 15.336 ;
     RECT  123.912 33.312 126.608 33.336 ;
     RECT  126.169 55.824 126.608 55.944 ;
     RECT  121.504 67.968 126.608 67.992 ;
     RECT  126.608 2.148 126.712 98.292 ;
     RECT  126.712 2.208 126.904 98.022 ;
     RECT  126.904 2.208 127.721 15.336 ;
     RECT  126.904 55.68 127.763 55.704 ;
     RECT  128.684 31.872 128.771 31.896 ;
     RECT  128.684 35.904 128.771 35.928 ;
     RECT  128.905 23.328 129.049 23.352 ;
     RECT  126.904 33.312 129.205 33.336 ;
     RECT  129.205 33.312 129.292 34.152 ;
     RECT  129.049 23.136 129.373 23.352 ;
     RECT  129.301 19.344 129.395 19.368 ;
     RECT  128.977 25.056 129.413 25.08 ;
     RECT  128.653 26.784 129.413 26.808 ;
     RECT  129.356 21.888 129.443 21.912 ;
     RECT  129.373 23.136 129.481 23.448 ;
     RECT  129.625 21.216 129.953 21.24 ;
     RECT  129.445 39.744 129.971 39.768 ;
     RECT  129.292 33.312 130.405 33.336 ;
     RECT  129.481 22.848 130.417 23.448 ;
     RECT  130.405 33.312 130.46 34.104 ;
     RECT  127.721 3.12 130.525 15.336 ;
     RECT  130.46 33.312 130.547 34.296 ;
     RECT  130.417 22.224 130.745 23.448 ;
     RECT  130.525 3.072 131.389 15.336 ;
     RECT  131.389 3.072 132.008 15.48 ;
     RECT  130.745 22.224 132.008 23.064 ;
     RECT  131.852 31.872 132.008 31.896 ;
     RECT  130.547 33.312 132.008 33.336 ;
     RECT  131.852 34.32 132.008 34.344 ;
     RECT  131.353 43.44 132.008 43.464 ;
     RECT  126.904 67.968 132.008 67.992 ;
     RECT  132.008 2.148 132.112 98.292 ;
     RECT  132.112 2.418 132.304 98.022 ;
     RECT  132.304 35.328 132.707 35.352 ;
     RECT  132.304 33.312 132.733 34.2 ;
     RECT  132.304 22.896 132.796 22.92 ;
     RECT  132.304 38.4 132.803 38.424 ;
     RECT  132.304 3.072 132.995 15.432 ;
     RECT  132.304 18.72 133.379 18.744 ;
     RECT  132.304 25.008 133.379 25.032 ;
     RECT  133.292 28.944 133.379 28.968 ;
     RECT  132.304 30 133.379 30.024 ;
     RECT  133.484 20.448 133.571 20.472 ;
     RECT  133.381 65.136 133.697 65.16 ;
     RECT  133.729 44.688 133.837 44.712 ;
     RECT  133.513 38.256 133.841 38.28 ;
     RECT  132.995 3.072 133.955 15.336 ;
     RECT  133.837 44.688 133.955 44.952 ;
     RECT  133.916 23.04 134.003 23.064 ;
     RECT  133.955 44.928 134.053 44.952 ;
     RECT  133.973 65.04 134.057 65.064 ;
     RECT  134.053 44.928 134.237 45 ;
     RECT  133.955 4.464 134.341 15.336 ;
     RECT  134.341 4.464 134.531 16.296 ;
     RECT  134.444 26.352 134.531 26.376 ;
     RECT  134.237 44.976 134.705 45 ;
     RECT  134.533 25.584 134.741 25.608 ;
     RECT  133.955 3.072 135.065 3.432 ;
     RECT  134.531 4.464 135.065 15.384 ;
     RECT  135.068 46.944 135.155 46.968 ;
     RECT  135.109 54.192 135.425 54.216 ;
     RECT  135.169 16.896 135.533 16.92 ;
     RECT  135.5 31.872 135.587 31.896 ;
     RECT  134.269 20.112 135.641 20.136 ;
     RECT  135.932 37.584 136.019 37.608 ;
     RECT  136.028 45.888 136.115 45.912 ;
     RECT  136.213 34.944 136.297 34.968 ;
     RECT  136.309 29.472 136.396 29.496 ;
     RECT  132.733 33.312 136.537 33.336 ;
     RECT  136.537 32.736 136.741 33.336 ;
     RECT  135.065 3.072 137.408 3.144 ;
     RECT  135.065 4.464 137.408 15.336 ;
     RECT  136.933 17.616 137.408 17.64 ;
     RECT  136.796 20.496 137.408 20.52 ;
     RECT  137.029 23.376 137.408 23.4 ;
     RECT  136.741 31.92 137.408 33.336 ;
     RECT  136.604 36.912 137.408 36.936 ;
     RECT  136.597 44.352 137.408 44.376 ;
     RECT  136.789 47.04 137.408 47.064 ;
     RECT  132.304 67.968 137.408 67.992 ;
     RECT  137.408 2.148 137.512 98.292 ;
     RECT  137.512 2.418 137.704 98.022 ;
     RECT  137.704 20.592 137.987 20.616 ;
     RECT  137.704 28.464 138.028 28.488 ;
     RECT  137.704 29.616 138.028 29.976 ;
     RECT  138.028 29.952 138.035 29.976 ;
     RECT  137.704 36.48 138.035 36.504 ;
     RECT  137.704 41.328 138.268 41.832 ;
     RECT  137.704 22.896 138.413 23.928 ;
     RECT  137.704 34.752 138.413 34.968 ;
     RECT  138.413 34.752 138.515 34.776 ;
     RECT  137.704 2.88 138.521 6.024 ;
     RECT  137.704 44.688 138.521 44.712 ;
     RECT  138.413 23.664 138.557 23.928 ;
     RECT  138.521 2.88 138.659 4.488 ;
     RECT  137.704 26.544 138.659 26.568 ;
     RECT  137.704 7.488 138.665 15.336 ;
     RECT  138.557 23.664 138.737 23.688 ;
     RECT  138.757 18.384 138.844 18.408 ;
     RECT  138.665 9.072 138.917 15.336 ;
     RECT  137.704 67.968 139.052 67.992 ;
     RECT  138.268 41.328 139.132 41.352 ;
     RECT  139.052 67.344 139.139 67.992 ;
     RECT  139.196 38.112 139.283 38.136 ;
     RECT  138.917 9.312 139.292 15.336 ;
     RECT  139.292 9.312 139.379 15.384 ;
     RECT  139.333 40.272 139.421 40.296 ;
     RECT  138.659 2.88 139.457 3.144 ;
     RECT  139.484 30.096 139.571 30.12 ;
     RECT  138.659 4.464 139.673 4.488 ;
     RECT  139.628 16.512 139.715 16.536 ;
     RECT  139.628 25.584 139.715 25.608 ;
     RECT  139.457 3.12 139.765 3.144 ;
     RECT  139.379 9.312 139.781 15.336 ;
     RECT  139.781 10.032 139.961 15.336 ;
     RECT  139.961 14.448 139.997 15.336 ;
     RECT  140.204 29.616 140.291 29.64 ;
     RECT  138.521 5.472 140.293 6.024 ;
     RECT  138.665 7.488 140.293 7.752 ;
     RECT  137.704 33.312 140.3 33.336 ;
     RECT  140.252 44.832 140.339 44.856 ;
     RECT  140.293 5.472 140.38 7.752 ;
     RECT  140.3 33.312 140.387 33.528 ;
     RECT  139.765 3.12 140.425 3.384 ;
     RECT  140.444 18.672 140.531 18.696 ;
     RECT  140.425 3.12 140.677 3.864 ;
     RECT  140.677 2.976 140.753 3.864 ;
     RECT  140.753 2.976 141.005 3.144 ;
     RECT  141.109 19.728 141.196 19.752 ;
     RECT  141.116 32.16 141.203 32.184 ;
     RECT  141.253 40.272 141.34 40.296 ;
     RECT  141.349 35.136 141.436 35.16 ;
     RECT  139.997 14.448 141.437 15 ;
     RECT  140.38 5.472 141.637 6.024 ;
     RECT  140.38 7.488 141.637 7.752 ;
     RECT  141.637 5.472 141.724 7.752 ;
     RECT  141.724 5.472 141.761 6.024 ;
     RECT  137.704 47.04 142.117 47.064 ;
     RECT  141.005 3.12 142.357 3.144 ;
     RECT  142.045 45.552 142.501 45.576 ;
     RECT  137.704 50.64 142.508 50.664 ;
     RECT  139.961 10.032 142.513 13.464 ;
     RECT  142.501 44.736 142.585 45.576 ;
     RECT  142.357 3.12 142.808 3.384 ;
     RECT  141.761 5.472 142.808 5.544 ;
     RECT  141.724 7.488 142.808 7.752 ;
     RECT  142.513 9.888 142.808 13.608 ;
     RECT  141.437 14.64 142.808 15 ;
     RECT  142.333 20.352 142.808 20.376 ;
     RECT  142.333 23.568 142.808 23.592 ;
     RECT  142.117 31.632 142.808 31.656 ;
     RECT  140.387 33.312 142.808 33.336 ;
     RECT  141.925 37.584 142.808 37.608 ;
     RECT  142.585 44.448 142.808 45.576 ;
     RECT  142.117 47.04 142.808 47.832 ;
     RECT  142.508 50.64 142.808 51 ;
     RECT  139.139 67.968 142.808 67.992 ;
     RECT  142.808 2.148 142.912 98.292 ;
     RECT  142.912 2.418 143.104 98.022 ;
     RECT  143.104 13.296 143.219 14.952 ;
     RECT  143.104 23.856 143.219 23.88 ;
     RECT  143.104 22.176 143.267 22.824 ;
     RECT  143.104 25.68 143.281 26.76 ;
     RECT  143.104 18.768 143.315 19.656 ;
     RECT  143.267 22.8 143.315 22.824 ;
     RECT  143.281 25.68 143.315 26.232 ;
     RECT  143.104 53.52 143.315 53.544 ;
     RECT  143.315 19.632 143.363 19.656 ;
     RECT  143.104 3.12 143.381 4.44 ;
     RECT  143.315 26.208 143.533 26.232 ;
     RECT  143.104 44.448 143.741 44.472 ;
     RECT  143.104 9.888 143.813 12.312 ;
     RECT  143.381 3.12 143.843 4.104 ;
     RECT  143.219 13.296 143.885 14.712 ;
     RECT  143.104 7.488 143.993 7.752 ;
     RECT  143.104 34.896 144.133 34.92 ;
     RECT  143.885 13.296 144.137 14.664 ;
     RECT  143.993 7.488 144.197 7.512 ;
     RECT  144.169 17.088 144.253 17.112 ;
     RECT  144.133 34.896 144.275 35.064 ;
     RECT  144.197 6.864 144.421 7.512 ;
     RECT  144.565 19.632 144.652 19.656 ;
     RECT  144.421 6.816 144.7 7.512 ;
     RECT  144.668 30 144.755 30.024 ;
     RECT  144.668 37.008 144.755 37.032 ;
     RECT  144.7 7.44 144.929 7.512 ;
     RECT  144.385 24.384 144.949 24.408 ;
     RECT  144.917 18.24 145.001 18.264 ;
     RECT  144.949 24.24 145.036 24.408 ;
     RECT  143.104 33.312 145.1 33.336 ;
     RECT  145.045 28.464 145.132 28.488 ;
     RECT  145.1 32.976 145.187 33.336 ;
     RECT  145.213 27.936 145.297 27.96 ;
     RECT  144.275 34.896 145.34 34.92 ;
     RECT  143.813 10.128 145.357 12.312 ;
     RECT  144.137 13.296 145.357 13.32 ;
     RECT  145.34 34.608 145.427 34.92 ;
     RECT  145.333 44.784 145.436 44.808 ;
     RECT  145.436 44.784 145.505 45.576 ;
     RECT  145.505 45.552 145.523 45.576 ;
     RECT  143.843 3.12 145.676 3.144 ;
     RECT  145.357 10.128 145.721 13.32 ;
     RECT  145.427 34.896 145.753 34.92 ;
     RECT  145.676 3.024 145.763 3.144 ;
     RECT  145.537 29.04 145.765 29.112 ;
     RECT  143.104 47.04 145.813 47.064 ;
     RECT  145.036 24.384 145.865 24.408 ;
     RECT  145.333 22.176 145.901 22.2 ;
     RECT  145.813 47.04 145.901 47.592 ;
     RECT  145.753 34.896 145.937 35.256 ;
     RECT  145.765 29.04 145.973 29.064 ;
     RECT  145.937 34.896 145.973 34.92 ;
     RECT  146.005 21.648 146.099 21.672 ;
     RECT  145.721 13.296 146.101 13.32 ;
     RECT  144.137 14.64 146.101 14.664 ;
     RECT  144.929 7.488 146.293 7.512 ;
     RECT  146.341 19.104 146.365 19.128 ;
     RECT  146.365 18.912 146.428 19.128 ;
     RECT  146.293 6.672 146.435 7.512 ;
     RECT  146.101 13.296 146.449 14.664 ;
     RECT  146.485 43.92 146.581 43.944 ;
     RECT  146.545 44.928 146.581 44.952 ;
     RECT  146.428 18.912 146.585 18.936 ;
     RECT  146.581 43.92 146.621 44.952 ;
     RECT  146.588 18.768 146.675 18.792 ;
     RECT  146.449 14.64 146.689 14.664 ;
     RECT  146.621 44.496 146.801 44.952 ;
     RECT  146.965 26.64 147.013 26.664 ;
     RECT  147.013 26.208 147.053 26.664 ;
     RECT  146.689 14.64 147.059 15.48 ;
     RECT  145.187 33.312 147.061 33.336 ;
     RECT  147.053 26.208 147.589 26.232 ;
     RECT  147.061 33.312 147.637 33.816 ;
     RECT  143.104 5.472 147.769 5.544 ;
     RECT  145.763 3.12 148.069 3.144 ;
     RECT  147.589 25.68 148.129 26.232 ;
     RECT  148.069 2.88 148.208 3.144 ;
     RECT  147.769 4.512 148.208 5.544 ;
     RECT  146.435 7.488 148.208 7.512 ;
     RECT  145.721 10.128 148.208 12.312 ;
     RECT  146.449 13.296 148.208 13.32 ;
     RECT  147.059 14.64 148.208 14.664 ;
     RECT  148.129 25.68 148.208 26.28 ;
     RECT  147.637 33.312 148.208 34.824 ;
     RECT  146.801 44.496 148.208 44.52 ;
     RECT  145.901 47.04 148.208 47.064 ;
     RECT  143.104 67.968 148.208 67.992 ;
     RECT  148.208 2.148 148.312 98.292 ;
     RECT  148.312 2.418 148.504 98.022 ;
     RECT  148.504 2.88 148.601 3.144 ;
     RECT  148.504 18.24 148.789 18.264 ;
     RECT  148.601 3.12 148.961 3.144 ;
     RECT  148.504 26.256 148.961 26.28 ;
     RECT  148.504 32.448 148.997 33.336 ;
     RECT  148.504 30.816 149.005 30.84 ;
     RECT  148.504 28.992 149.02 29.016 ;
     RECT  148.504 13.296 149.033 14.232 ;
     RECT  149.033 14.208 149.212 14.232 ;
     RECT  148.504 24.816 149.363 24.84 ;
     RECT  148.504 21.12 149.569 21.144 ;
     RECT  148.504 5.472 149.605 5.544 ;
     RECT  149.533 13.104 149.617 13.128 ;
     RECT  149.569 21.12 149.645 21.24 ;
     RECT  149.605 5.472 149.749 6.024 ;
     RECT  149.677 18.768 149.789 18.792 ;
     RECT  149.749 5.472 149.891 6.168 ;
     RECT  149.645 21.216 149.891 21.24 ;
     RECT  148.504 7.44 149.9 7.896 ;
     RECT  149.821 17.088 149.905 17.112 ;
     RECT  149.9 7.44 149.987 8.136 ;
     RECT  149.9 24.24 149.987 24.264 ;
     RECT  148.504 67.968 149.989 67.992 ;
     RECT  149.941 19.68 150.041 19.704 ;
     RECT  149.989 67.968 150.076 68.904 ;
     RECT  149.996 17.856 150.083 18.264 ;
     RECT  149.987 7.44 150.113 7.656 ;
     RECT  149.989 23.376 150.113 23.4 ;
     RECT  149.821 27.024 150.221 27.048 ;
     RECT  150.083 18.24 150.265 18.264 ;
     RECT  150.253 29.088 150.337 29.112 ;
     RECT  149.891 5.472 150.365 5.544 ;
     RECT  150.113 7.488 150.509 7.656 ;
     RECT  150.397 21.552 150.509 21.576 ;
     RECT  150.373 29.568 150.515 29.592 ;
     RECT  148.504 10.128 151.189 11.784 ;
     RECT  151.189 15.408 151.237 15.432 ;
     RECT  151.237 15.408 151.283 16.008 ;
     RECT  151.283 15.984 151.324 16.008 ;
     RECT  151.189 10.128 151.405 12.024 ;
     RECT  151.333 13.056 151.405 13.08 ;
     RECT  151.405 10.128 151.489 13.08 ;
     RECT  151.489 11.664 151.517 13.08 ;
     RECT  151.517 11.76 151.697 13.08 ;
     RECT  151.697 11.76 151.715 12.024 ;
     RECT  151.489 10.128 151.913 10.488 ;
     RECT  151.715 11.76 151.949 11.784 ;
     RECT  150.365 5.472 152.021 5.496 ;
     RECT  150.509 7.632 152.197 7.656 ;
     RECT  152.189 18.432 152.197 18.456 ;
     RECT  151.697 13.056 152.273 13.08 ;
     RECT  152.197 18.432 152.273 18.696 ;
     RECT  152.273 18.672 152.284 18.696 ;
     RECT  152.197 7.44 152.293 7.656 ;
     RECT  148.997 33.312 152.345 33.336 ;
     RECT  152.293 7.44 152.381 7.896 ;
     RECT  152.381 7.44 152.417 7.656 ;
     RECT  152.197 14.976 152.561 15 ;
     RECT  152.533 5.856 152.62 5.88 ;
     RECT  152.533 21.12 152.633 21.144 ;
     RECT  153.061 2.832 153.313 2.856 ;
     RECT  151.913 10.464 153.349 10.488 ;
     RECT  153.349 10.32 153.397 10.488 ;
     RECT  153.445 25.68 153.457 25.704 ;
     RECT  153.313 2.832 153.608 3.144 ;
     RECT  153.377 6.288 153.608 6.312 ;
     RECT  152.417 7.632 153.608 7.656 ;
     RECT  153.397 10.32 153.608 10.776 ;
     RECT  153.452 18.384 153.608 18.408 ;
     RECT  153.432 19.632 153.608 19.656 ;
     RECT  152.269 22.176 153.608 22.2 ;
     RECT  153.457 25.68 153.608 25.848 ;
     RECT  152.725 31.92 153.608 31.944 ;
     RECT  148.504 47.04 153.608 47.064 ;
     RECT  150.076 67.968 153.608 67.992 ;
     RECT  153.608 2.148 153.712 98.292 ;
     RECT  153.712 2.418 153.904 98.022 ;
     RECT  153.904 3.312 154.204 3.336 ;
     RECT  153.904 7.632 154.289 7.656 ;
     RECT  153.904 24.864 154.325 26.808 ;
     RECT  153.904 67.872 154.325 68.376 ;
     RECT  153.904 30.048 154.397 30.072 ;
     RECT  153.904 16.56 154.433 17.064 ;
     RECT  153.904 21.12 154.54 22.824 ;
     RECT  153.904 18.768 154.547 19.032 ;
     RECT  154.433 17.04 154.549 17.064 ;
     RECT  153.904 5.088 154.595 5.256 ;
     RECT  154.547 18.864 154.595 19.032 ;
     RECT  154.54 22.224 154.621 22.824 ;
     RECT  154.595 5.136 154.649 5.256 ;
     RECT  153.904 13.968 154.649 13.992 ;
     RECT  154.54 21.12 154.657 21.144 ;
     RECT  154.325 26.784 154.685 26.808 ;
     RECT  154.649 5.232 154.691 5.256 ;
     RECT  154.595 19.008 154.757 19.032 ;
     RECT  154.621 22.8 154.757 22.824 ;
     RECT  154.325 67.872 154.865 67.896 ;
     RECT  154.961 9.648 155.045 9.672 ;
     RECT  154.325 24.864 155.045 24.888 ;
     RECT  155.029 15.072 155.125 15.192 ;
     RECT  155.077 23.952 155.161 23.976 ;
     RECT  155.125 14.832 155.217 15.192 ;
     RECT  155.217 14.832 155.225 15.096 ;
     RECT  155.225 15.072 155.261 15.096 ;
     RECT  155.365 13.104 155.449 13.128 ;
     RECT  155.029 10.848 155.521 10.872 ;
     RECT  155.029 6.288 155.573 6.312 ;
     RECT  155.573 6.288 155.621 7.08 ;
     RECT  155.621 7.056 155.657 7.08 ;
     RECT  153.904 47.04 155.689 47.064 ;
     RECT  155.573 18.864 155.717 18.984 ;
     RECT  155.717 18.816 155.737 18.984 ;
     RECT  155.737 18.816 155.801 18.84 ;
     RECT  155.689 46.704 156.121 47.064 ;
     RECT  156.121 46.512 158.425 47.064 ;
     RECT  158.425 46.512 158.713 47.208 ;
     RECT  158.713 46.512 159.037 47.256 ;
     RECT  159.037 46.464 159.948 47.256 ;
    LAYER M5 ;
     RECT  97.872 0.016 97.992 0.037 ;
     RECT  97.776 0.037 97.992 0.179 ;
     RECT  97.776 0.179 97.944 0.229 ;
     RECT  97.392 0.229 97.944 0.275 ;
     RECT  97.392 0.275 97.8 2.091 ;
     RECT  126 2.015 126.024 2.099 ;
     RECT  126.6 2.137 126.72 2.151 ;
     RECT  132 2.137 132.12 2.151 ;
     RECT  137.4 2.137 137.52 2.151 ;
     RECT  142.8 2.137 142.92 2.151 ;
     RECT  148.2 2.137 148.32 2.151 ;
     RECT  153.6 2.137 153.72 2.151 ;
     RECT  126.6 2.151 126.912 2.197 ;
     RECT  126.6 2.197 127.704 2.283 ;
     RECT  153.6 2.151 153.912 2.821 ;
     RECT  148.2 2.151 148.512 2.869 ;
     RECT  2.4 2.151 2.712 2.899 ;
     RECT  99.6 2.151 99.912 2.933 ;
     RECT  148.08 2.869 148.512 2.953 ;
     RECT  2.064 2.899 2.712 2.986 ;
     RECT  124.08 2.899 124.104 2.986 ;
     RECT  124.08 2.986 124.152 2.987 ;
     RECT  145.728 2.869 145.752 3.059 ;
     RECT  61.8 2.151 62.112 3.061 ;
     RECT  124.128 2.987 124.152 3.115 ;
     RECT  2.016 2.986 2.712 3.125 ;
     RECT  153.072 2.821 153.912 3.283 ;
     RECT  142.8 2.151 143.112 3.311 ;
     RECT  142.464 3.311 143.112 3.349 ;
     RECT  153.072 3.283 154.152 3.371 ;
     RECT  34.8 2.151 35.112 3.381 ;
     RECT  137.4 2.151 137.712 3.381 ;
     RECT  130.32 3.349 130.344 3.435 ;
     RECT  139.776 3.349 139.8 3.435 ;
     RECT  142.368 3.349 143.112 3.435 ;
     RECT  67.2 2.151 67.512 3.445 ;
     RECT  34.8 3.381 35.976 3.573 ;
     RECT  137.4 3.381 138.648 3.755 ;
     RECT  40.2 2.151 40.512 3.765 ;
     RECT  134.544 3.397 134.568 3.795 ;
     RECT  133.824 3.795 134.568 3.883 ;
     RECT  56.4 2.151 56.712 3.893 ;
     RECT  58.464 3.189 58.488 3.893 ;
     RECT  133.92 3.883 134.568 3.947 ;
     RECT  39.84 3.765 40.512 4.021 ;
     RECT  142.8 3.435 143.112 4.021 ;
     RECT  61.8 3.061 62.952 4.085 ;
     RECT  142.8 4.021 143.832 4.115 ;
     RECT  34.272 3.573 35.976 4.149 ;
     RECT  128.64 4.261 128.664 4.271 ;
     RECT  128.496 4.271 128.664 4.277 ;
     RECT  153.6 3.371 154.152 4.277 ;
     RECT  128.496 4.277 128.808 4.355 ;
     RECT  1.92 3.125 2.712 4.357 ;
     RECT  128.64 4.355 128.808 4.365 ;
     RECT  38.832 4.021 40.512 4.395 ;
     RECT  128.64 4.365 128.664 4.395 ;
     RECT  153.6 4.277 154.488 4.469 ;
     RECT  148.2 2.953 148.512 4.501 ;
     RECT  148.08 4.501 148.512 4.587 ;
     RECT  153.408 4.469 154.488 4.597 ;
     RECT  132 2.151 132.312 4.661 ;
     RECT  153.408 4.597 154.632 4.725 ;
     RECT  144.192 4.789 144.216 4.853 ;
     RECT  149.904 4.213 149.928 4.853 ;
     RECT  153.408 4.725 154.68 4.853 ;
     RECT  131.184 4.661 132.312 4.883 ;
     RECT  1.872 4.357 2.712 5.011 ;
     RECT  149.904 4.853 150.504 5.035 ;
     RECT  148.2 4.587 148.512 5.045 ;
     RECT  1.824 5.011 2.712 5.099 ;
     RECT  149.904 5.035 149.928 5.237 ;
     RECT  153.408 4.853 155.064 5.429 ;
     RECT  126.6 2.283 126.912 5.493 ;
     RECT  144.192 4.853 144.792 5.621 ;
     RECT  137.4 3.755 137.712 5.685 ;
     RECT  153.408 5.429 155.4 5.685 ;
     RECT  137.4 5.685 137.928 5.795 ;
     RECT  152.544 5.685 155.4 5.813 ;
     RECT  126 5.493 126.912 5.877 ;
     RECT  130.56 5.797 130.584 5.939 ;
     RECT  135.84 5.893 135.864 6.059 ;
     RECT  148.2 5.045 148.632 6.069 ;
     RECT  149.76 5.237 149.928 6.069 ;
     RECT  1.872 5.099 2.712 6.123 ;
     RECT  148.2 6.069 149.928 6.179 ;
     RECT  144.192 5.621 145.752 6.453 ;
     RECT  144.096 6.453 145.752 6.623 ;
     RECT  146.928 5.557 146.952 6.623 ;
     RECT  149.856 6.179 149.928 6.709 ;
     RECT  126 5.877 127.56 6.805 ;
     RECT  133.824 6.709 133.848 6.827 ;
     RECT  152.208 5.813 155.4 6.837 ;
     RECT  140.304 6.767 140.328 6.851 ;
     RECT  141.648 6.767 141.672 6.851 ;
     RECT  126 6.805 128.472 6.891 ;
     RECT  152.208 6.837 155.64 7.091 ;
     RECT  124.08 6.949 124.104 7.139 ;
     RECT  129.408 7.199 129.432 7.283 ;
     RECT  1.92 6.123 2.712 7.315 ;
     RECT  1.872 7.315 2.712 7.402 ;
     RECT  130.416 7.333 130.44 7.417 ;
     RECT  126 6.891 127.56 7.475 ;
     RECT  152.208 7.091 155.496 7.477 ;
     RECT  149.856 6.709 150.312 7.605 ;
     RECT  151.68 7.477 155.496 7.605 ;
     RECT  1.824 7.402 2.712 7.669 ;
     RECT  137.4 5.795 137.712 7.765 ;
     RECT  148.2 6.179 148.824 7.827 ;
     RECT  149.856 7.605 155.496 7.827 ;
     RECT  1.824 7.669 2.904 7.915 ;
     RECT  124.032 7.477 124.056 7.915 ;
     RECT  134.784 7.827 134.808 7.915 ;
     RECT  137.4 7.765 138.6 7.915 ;
     RECT  148.2 7.827 155.496 7.915 ;
     RECT  1.824 7.915 2.712 8.005 ;
     RECT  1.104 8.005 2.712 8.197 ;
     RECT  129.936 8.149 129.96 8.235 ;
     RECT  38.832 4.395 38.856 8.309 ;
     RECT  39.84 4.395 40.512 8.309 ;
     RECT  24 2.151 24.312 8.437 ;
     RECT  137.4 7.915 138.552 8.521 ;
     RECT  142.8 4.115 143.112 8.629 ;
     RECT  144.096 6.623 146.952 8.629 ;
     RECT  148.2 7.915 148.68 9.077 ;
     RECT  149.856 7.915 155.496 9.077 ;
     RECT  126.6 7.475 127.56 9.155 ;
     RECT  130.56 9.269 130.584 9.461 ;
     RECT  134.496 9.269 134.52 9.461 ;
     RECT  148.2 9.077 155.496 9.461 ;
     RECT  133.968 9.461 134.52 9.549 ;
     RECT  130.56 9.461 130.68 9.643 ;
     RECT  134.4 9.549 134.52 9.643 ;
     RECT  126.6 9.155 126.912 9.781 ;
     RECT  129.744 9.925 129.768 10.027 ;
     RECT  105 2.151 105.312 10.037 ;
     RECT  24 8.437 24.456 10.101 ;
     RECT  69.408 8.949 69.432 10.357 ;
     RECT  126 9.781 126.912 10.549 ;
     RECT  126 10.549 127.128 10.633 ;
     RECT  18.6 2.151 18.912 10.741 ;
     RECT  148.2 9.461 155.784 10.795 ;
     RECT  148.2 10.795 152.568 10.869 ;
     RECT  148.08 10.869 152.568 10.957 ;
     RECT  18.48 10.741 18.912 11.189 ;
     RECT  24 10.101 25.368 11.253 ;
     RECT  56.4 3.893 58.488 11.317 ;
     RECT  130.128 11.317 130.152 11.411 ;
     RECT  126 10.633 126.912 11.507 ;
     RECT  126.144 11.507 126.912 11.755 ;
     RECT  72.6 2.151 72.912 11.765 ;
     RECT  6.24 10.613 6.264 11.829 ;
     RECT  126.288 11.755 126.912 11.891 ;
     RECT  126.48 11.891 126.912 11.977 ;
     RECT  148.2 10.957 152.568 12.035 ;
     RECT  142.8 8.629 146.952 12.149 ;
     RECT  142.704 12.149 146.952 12.237 ;
     RECT  124.128 11.509 124.152 12.277 ;
     RECT  124.032 12.277 124.152 12.323 ;
     RECT  14.688 12.405 14.712 12.469 ;
     RECT  14.688 12.469 15.672 12.651 ;
     RECT  124.032 12.323 124.104 12.691 ;
     RECT  17.76 11.189 18.912 12.725 ;
     RECT  20.064 3.957 20.088 12.725 ;
     RECT  129.216 12.661 129.24 12.755 ;
     RECT  123.984 12.691 124.104 12.779 ;
     RECT  7.8 2.151 8.112 12.981 ;
     RECT  134.496 13.011 134.52 13.099 ;
     RECT  67.2 3.445 67.944 13.429 ;
     RECT  33.552 4.149 35.976 13.557 ;
     RECT  31.488 9.525 31.512 13.621 ;
     RECT  124.032 12.779 124.104 13.955 ;
     RECT  5.424 11.829 6.264 14.581 ;
     RECT  132 4.883 132.312 14.821 ;
     RECT  129.36 15.157 129.384 15.251 ;
     RECT  17.76 12.725 20.088 15.285 ;
     RECT  131.664 14.821 132.312 15.349 ;
     RECT  139.344 15.315 139.368 15.403 ;
     RECT  131.664 15.349 132.984 15.407 ;
     RECT  135.024 15.349 135.048 15.433 ;
     RECT  131.616 15.407 132.984 15.443 ;
     RECT  142.8 12.237 146.952 15.445 ;
     RECT  131.616 15.443 132.312 15.491 ;
     RECT  142.8 15.445 147.048 15.531 ;
     RECT  148.2 12.035 151.272 16.043 ;
     RECT  10.896 12.149 10.92 16.117 ;
     RECT  11.952 10.677 11.976 16.117 ;
     RECT  137.4 8.521 137.712 16.245 ;
     RECT  134.496 16.223 134.52 16.307 ;
     RECT  51 2.151 51.312 16.309 ;
     RECT  139.68 16.467 139.704 16.555 ;
     RECT  142.8 15.531 146.664 17.123 ;
     RECT  136.944 16.245 137.712 17.651 ;
     RECT  144.96 17.123 146.664 18.275 ;
     RECT  152.544 12.035 152.568 18.335 ;
     RECT  153.6 10.795 155.784 18.335 ;
     RECT  152.544 18.335 155.784 18.419 ;
     RECT  152.544 18.419 152.568 18.421 ;
     RECT  138.768 18.357 138.792 18.445 ;
     RECT  152.208 18.421 152.568 18.707 ;
     RECT  140.496 18.643 140.52 18.731 ;
     RECT  133.344 18.709 133.368 18.795 ;
     RECT  145.248 18.275 146.664 18.803 ;
     RECT  153.6 18.419 155.784 18.851 ;
     RECT  153.6 18.851 155.688 18.995 ;
     RECT  145.248 18.803 146.376 19.603 ;
     RECT  152.544 18.707 152.568 19.603 ;
     RECT  153.6 18.995 155.112 19.603 ;
     RECT  144.576 19.603 146.376 19.691 ;
     RECT  152.544 19.603 155.112 19.691 ;
     RECT  141.12 19.509 141.144 19.789 ;
     RECT  129.36 19.333 129.384 19.947 ;
     RECT  137.4 17.651 137.712 20.469 ;
     RECT  133.536 19.957 133.56 20.523 ;
     RECT  136.848 20.469 137.712 20.557 ;
     RECT  137.4 20.557 137.712 20.563 ;
     RECT  137.4 20.563 137.976 20.651 ;
     RECT  148.2 16.043 150.312 21.155 ;
     RECT  152.544 19.691 152.568 21.155 ;
     RECT  149.856 21.155 150.312 21.251 ;
     RECT  145.248 19.691 146.088 21.683 ;
     RECT  129.408 21.813 129.432 21.923 ;
     RECT  153.6 19.691 155.112 22.165 ;
     RECT  152.736 22.165 155.112 22.251 ;
     RECT  153.6 22.251 155.112 22.259 ;
     RECT  153.6 22.259 154.008 22.739 ;
     RECT  132 15.491 132.312 22.741 ;
     RECT  137.4 20.651 137.712 22.837 ;
     RECT  131.184 22.741 132.312 22.885 ;
     RECT  137.4 22.837 138.024 22.931 ;
     RECT  131.184 22.885 132.744 23.083 ;
     RECT  133.968 22.995 133.992 23.083 ;
     RECT  137.4 22.931 137.712 23.327 ;
     RECT  137.04 23.327 137.712 23.411 ;
     RECT  155.088 22.259 155.112 23.987 ;
     RECT  145.248 21.683 145.752 24.211 ;
     RECT  150 21.251 150.312 24.229 ;
     RECT  144.96 24.211 145.752 24.299 ;
     RECT  148.2 21.155 148.512 24.757 ;
     RECT  149.952 24.229 150.312 24.757 ;
     RECT  153.6 22.739 153.912 24.757 ;
     RECT  148.2 24.757 150.312 24.851 ;
     RECT  153.6 24.757 154.488 24.899 ;
     RECT  133.344 24.997 133.368 25.081 ;
     RECT  148.2 24.851 148.512 25.631 ;
     RECT  139.68 25.555 139.704 25.643 ;
     RECT  153.6 24.899 153.912 25.653 ;
     RECT  134.544 25.573 134.568 25.657 ;
     RECT  147.6 25.631 148.512 25.715 ;
     RECT  153.456 25.653 153.912 25.741 ;
     RECT  142.8 17.123 143.496 26.243 ;
     RECT  134.496 26.293 134.52 26.387 ;
     RECT  137.4 23.411 137.712 26.515 ;
     RECT  137.4 26.515 138.648 26.603 ;
     RECT  142.8 26.243 143.256 26.795 ;
     RECT  146.976 26.629 147 26.795 ;
     RECT  145.248 24.299 145.752 28.435 ;
     RECT  137.4 26.603 137.712 28.453 ;
     RECT  145.056 28.435 145.752 28.523 ;
     RECT  148.2 25.715 148.512 28.947 ;
     RECT  148.2 28.947 148.968 29.035 ;
     RECT  145.728 28.523 145.752 29.123 ;
     RECT  150.288 24.851 150.312 29.123 ;
     RECT  136.32 29.429 136.344 29.517 ;
     RECT  150.384 29.523 150.408 29.557 ;
     RECT  150.384 29.557 150.504 29.611 ;
     RECT  150.48 29.611 150.504 29.641 ;
     RECT  137.4 28.453 137.976 29.907 ;
     RECT  137.4 29.907 138.024 29.995 ;
     RECT  153.6 25.741 153.912 30.005 ;
     RECT  133.344 28.725 133.368 30.035 ;
     RECT  140.256 29.605 140.28 30.069 ;
     RECT  153.6 30.005 154.344 30.093 ;
     RECT  139.536 30.069 140.28 30.123 ;
     RECT  144.72 29.941 144.744 30.123 ;
     RECT  139.536 30.123 139.56 30.157 ;
     RECT  148.2 29.035 148.512 30.773 ;
     RECT  148.2 30.773 148.968 30.861 ;
     RECT  142.8 26.795 143.112 31.605 ;
     RECT  142.128 31.605 143.112 31.693 ;
     RECT  132 23.083 132.312 31.861 ;
     RECT  137.4 29.995 137.712 31.861 ;
     RECT  153.6 30.093 153.912 31.891 ;
     RECT  128.736 31.827 128.76 31.915 ;
     RECT  135.552 31.827 135.576 31.915 ;
     RECT  131.904 31.861 132.312 31.945 ;
     RECT  136.752 31.861 137.712 31.955 ;
     RECT  152.736 31.891 153.912 31.979 ;
     RECT  141.168 32.117 141.192 32.205 ;
     RECT  145.152 32.965 145.176 33.067 ;
     RECT  124.032 13.955 124.056 33.347 ;
     RECT  140.352 33.461 140.376 33.549 ;
     RECT  147.072 33.781 147.096 33.865 ;
     RECT  148.2 30.861 148.512 33.973 ;
     RECT  132 31.945 132.312 34.165 ;
     RECT  129.216 34.117 129.24 34.219 ;
     RECT  130.416 34.069 130.536 34.219 ;
     RECT  132 34.165 132.696 34.293 ;
     RECT  130.512 34.219 130.536 34.307 ;
     RECT  131.904 34.293 132.696 34.381 ;
     RECT  145.392 34.579 145.416 34.667 ;
     RECT  137.4 31.955 137.712 34.741 ;
     RECT  147.648 33.973 148.512 34.835 ;
     RECT  136.224 34.933 136.248 35.017 ;
     RECT  144.24 34.613 144.264 35.029 ;
     RECT  144.144 35.029 144.264 35.115 ;
     RECT  137.4 34.741 138.504 35.179 ;
     RECT  141.36 35.091 141.384 35.179 ;
     RECT  144.144 35.115 144.168 35.179 ;
     RECT  132 34.381 132.696 35.363 ;
     RECT  128.736 35.859 128.76 35.947 ;
     RECT  137.4 35.179 137.712 36.435 ;
     RECT  137.4 36.435 138.024 36.523 ;
     RECT  137.4 36.523 137.712 36.901 ;
     RECT  144.72 36.981 144.744 37.069 ;
     RECT  142.8 31.693 143.112 37.535 ;
     RECT  136.656 36.901 137.712 37.557 ;
     RECT  135.984 37.557 137.712 37.611 ;
     RECT  141.936 37.535 143.112 37.619 ;
     RECT  135.984 37.611 136.008 37.645 ;
     RECT  139.248 37.557 139.272 38.208 ;
     RECT  132 35.363 132.312 38.355 ;
     RECT  132 38.355 132.792 38.443 ;
     RECT  129.936 39.733 129.96 39.817 ;
     RECT  139.344 40.245 139.368 40.333 ;
     RECT  141.264 40.245 141.288 40.333 ;
     RECT  137.4 37.611 137.712 41.269 ;
     RECT  137.4 41.269 139.08 41.363 ;
     RECT  137.4 41.363 138.216 41.899 ;
     RECT  146.496 43.871 146.52 43.955 ;
     RECT  137.4 41.899 137.712 44.341 ;
     RECT  136.608 44.341 137.712 44.661 ;
     RECT  142.8 37.619 143.112 44.661 ;
     RECT  136.608 44.661 138.504 44.715 ;
     RECT  133.92 44.639 133.944 44.723 ;
     RECT  137.4 44.715 138.504 44.749 ;
     RECT  145.344 44.725 145.368 44.819 ;
     RECT  140.304 44.661 140.328 44.867 ;
     RECT  142.512 44.661 143.112 45.541 ;
     RECT  145.488 45.523 145.512 45.611 ;
     RECT  142.08 45.541 143.112 45.625 ;
     RECT  136.08 45.843 136.104 45.931 ;
     RECT  135.12 46.933 135.144 47.275 ;
     RECT  142.8 45.625 143.112 47.541 ;
     RECT  145.824 47.541 145.848 47.629 ;
     RECT  142.464 47.541 143.112 47.851 ;
     RECT  137.4 44.749 137.712 50.421 ;
     RECT  137.4 50.421 138.216 50.731 ;
     RECT  142.8 47.851 143.112 50.741 ;
     RECT  142.56 50.741 143.112 51.051 ;
     RECT  142.8 51.051 143.112 53.493 ;
     RECT  142.8 53.493 143.304 53.581 ;
     RECT  135.12 54.133 135.144 54.227 ;
     RECT  126.6 11.977 126.912 55.635 ;
     RECT  126.6 55.635 127.752 55.669 ;
     RECT  126.48 55.669 127.752 55.723 ;
     RECT  126.48 55.723 126.912 55.775 ;
     RECT  126.192 55.775 126.912 55.859 ;
     RECT  126.48 55.859 126.912 55.955 ;
     RECT  134.016 64.991 134.04 65.075 ;
     RECT  133.392 65.125 133.416 65.209 ;
     RECT  1.056 8.197 2.712 65.843 ;
     RECT  1.104 65.843 2.712 66.995 ;
     RECT  1.68 66.995 2.712 67.237 ;
     RECT  4.272 11.701 4.296 67.237 ;
     RECT  115.8 2.151 116.112 67.237 ;
     RECT  22.56 13.045 22.584 67.247 ;
     RECT  38.832 8.309 40.512 67.247 ;
     RECT  55.824 11.317 58.488 67.253 ;
     RECT  59.568 67.247 59.592 67.253 ;
     RECT  33.36 13.557 35.976 67.283 ;
     RECT  38.832 67.247 41.016 67.283 ;
     RECT  68.928 10.357 69.432 67.283 ;
     RECT  97.392 2.091 97.416 67.283 ;
     RECT  1.68 67.237 4.296 67.321 ;
     RECT  115.8 67.237 116.328 67.321 ;
     RECT  55.824 67.253 59.592 67.331 ;
     RECT  114.672 67.247 114.696 67.331 ;
     RECT  118.512 67.295 118.536 67.379 ;
     RECT  61.8 4.085 63.624 67.381 ;
     RECT  64.608 3.253 64.632 67.381 ;
     RECT  139.104 67.317 139.128 67.405 ;
     RECT  55.824 67.331 59.448 67.427 ;
     RECT  61.8 67.381 64.632 67.465 ;
     RECT  55.824 67.427 59.256 67.475 ;
     RECT  105 10.037 105.432 67.477 ;
     RECT  21.648 67.247 22.584 67.657 ;
     RECT  80.352 67.219 80.376 67.657 ;
     RECT  44.112 15.349 44.136 67.765 ;
     RECT  22.416 67.657 22.584 67.819 ;
     RECT  153.6 31.979 153.912 67.823 ;
     RECT  39.744 67.283 41.016 67.829 ;
     RECT  42 9.909 42.024 67.829 ;
     RECT  54.288 12.917 54.312 67.829 ;
     RECT  55.824 67.475 58.488 67.829 ;
     RECT  30.912 13.621 31.512 67.859 ;
     RECT  44.112 67.765 44.424 67.859 ;
     RECT  61.8 67.465 63.624 67.859 ;
     RECT  66.96 13.429 67.944 67.859 ;
     RECT  104.304 67.477 105.432 67.859 ;
     RECT  44.4 67.859 44.424 67.883 ;
     RECT  153.6 67.823 154.584 67.907 ;
     RECT  104.304 67.859 105.312 67.947 ;
     RECT  110.4 2.151 110.712 68.053 ;
     RECT  54.288 67.829 58.488 68.099 ;
     RECT  99.6 2.933 100.776 68.115 ;
     RECT  109.968 68.053 110.712 68.115 ;
     RECT  109.104 68.115 110.712 68.139 ;
     RECT  67.2 67.859 67.944 68.149 ;
     RECT  69.408 67.283 69.432 68.149 ;
     RECT  74.496 68.115 74.52 68.203 ;
     RECT  99.12 68.115 100.776 68.203 ;
     RECT  107.952 68.115 107.976 68.203 ;
     RECT  109.104 68.139 109.128 68.203 ;
     RECT  69.408 68.149 69.528 68.233 ;
     RECT  10.896 16.117 11.976 68.331 ;
     RECT  67.2 68.149 68.424 68.387 ;
     RECT  117.744 67.813 117.768 68.387 ;
     RECT  39.744 67.829 42.024 68.4 ;
     RECT  78 2.151 78.312 68.405 ;
     RECT  153.6 67.907 154.008 68.425 ;
     RECT  54.288 68.099 54.312 68.435 ;
     RECT  55.824 68.099 58.488 68.435 ;
     RECT  72.6 11.765 73.32 68.435 ;
     RECT  103.296 8.501 103.32 68.435 ;
     RECT  75.552 68.405 75.576 68.675 ;
     RECT  60.384 68.629 60.408 68.715 ;
     RECT  78 68.405 78.408 68.736 ;
     RECT  5.424 14.581 6.6 68.773 ;
     RECT  88.8 2.151 89.112 68.773 ;
     RECT  103.872 68.755 103.896 68.843 ;
     RECT  4.272 67.321 4.296 68.883 ;
     RECT  29.4 2.151 29.712 68.883 ;
     RECT  30.912 67.859 31.272 68.883 ;
     RECT  34.8 67.283 35.112 68.883 ;
     RECT  45.6 2.151 45.912 68.883 ;
     RECT  67.2 68.387 67.944 68.883 ;
     RECT  150 68.853 150.024 68.941 ;
     RECT  4.128 68.883 4.296 68.971 ;
     RECT  5.424 68.773 6.648 68.971 ;
     RECT  29.4 68.883 31.272 68.971 ;
     RECT  34.656 68.883 35.112 68.971 ;
     RECT  36.768 68.245 36.792 68.971 ;
     RECT  45.024 68.883 45.912 68.971 ;
     RECT  67.104 68.883 67.944 68.971 ;
     RECT  86.496 68.883 86.52 68.971 ;
     RECT  88.8 68.773 90.072 68.971 ;
     RECT  91.728 68.773 91.752 68.971 ;
     RECT  39.744 68.4 40.512 68.975 ;
     RECT  49.296 14.773 49.32 68.981 ;
     RECT  14.784 12.651 15.672 69.011 ;
     RECT  49.296 68.981 49.56 69.011 ;
     RECT  56.4 68.435 58.488 69.011 ;
     RECT  67.2 68.971 67.944 69.011 ;
     RECT  69.408 68.233 69.432 69.011 ;
     RECT  39.312 68.975 40.512 69.059 ;
     RECT  17.76 15.285 20.136 69.109 ;
     RECT  49.536 69.011 49.56 69.155 ;
     RECT  24 11.253 25.8 69.173 ;
     RECT  17.76 69.109 20.616 69.203 ;
     RECT  92.832 68.917 92.856 69.251 ;
     RECT  50.88 16.309 51.312 69.291 ;
     RECT  94.2 2.151 94.512 69.301 ;
     RECT  24 69.173 26.232 69.347 ;
     RECT  14.784 69.011 15.384 69.419 ;
     RECT  61.8 67.859 63 69.429 ;
     RECT  7.8 12.981 8.664 69.459 ;
     RECT  9.648 69.429 9.672 69.459 ;
     RECT  91.632 69.237 91.656 69.493 ;
     RECT  61.8 69.429 63.48 69.517 ;
     RECT  93.072 69.429 93.096 69.517 ;
     RECT  7.8 69.459 9.672 69.539 ;
     RECT  94.2 69.301 95.064 69.541 ;
     RECT  7.8 69.539 9.24 69.547 ;
     RECT  29.4 68.971 30.024 69.547 ;
     RECT  91.536 69.493 91.656 69.577 ;
     RECT  64.608 67.465 64.632 69.587 ;
     RECT  93.456 69.541 95.064 69.611 ;
     RECT  93.456 69.611 94.512 69.625 ;
     RECT  91.632 69.577 91.656 69.683 ;
     RECT  1.68 67.321 2.712 69.827 ;
     RECT  105 67.947 105.312 69.941 ;
     RECT  64.32 69.941 64.344 70.029 ;
     RECT  105 69.941 105.48 70.029 ;
     RECT  10.896 68.331 10.92 70.127 ;
     RECT  11.952 68.331 11.976 70.127 ;
     RECT  10.896 70.127 11.976 70.163 ;
     RECT  10.896 70.163 11.448 70.211 ;
     RECT  56.4 69.011 57.624 70.227 ;
     RECT  99.6 68.203 100.776 70.227 ;
     RECT  56.4 70.227 57.864 70.315 ;
     RECT  99.408 70.227 100.776 70.315 ;
     RECT  99.6 70.315 100.776 70.403 ;
     RECT  17.76 69.203 20.136 70.507 ;
     RECT  87.312 70.405 87.336 70.507 ;
     RECT  83.4 2.151 83.712 70.549 ;
     RECT  83.4 70.549 84.504 70.635 ;
     RECT  55.248 70.389 55.272 70.691 ;
     RECT  82.176 70.611 82.2 70.699 ;
     RECT  17.76 70.507 18.912 70.703 ;
     RECT  24 69.347 25.8 70.703 ;
     RECT  53.136 3.701 53.16 70.739 ;
     RECT  17.616 70.703 18.912 70.787 ;
     RECT  24 70.703 25.992 70.787 ;
     RECT  43.872 70.703 43.896 70.787 ;
     RECT  58.704 70.837 58.728 70.921 ;
     RECT  78 68.736 78.312 70.933 ;
     RECT  4.272 68.971 4.296 70.981 ;
     RECT  31.056 68.971 31.224 70.995 ;
     RECT  78 70.933 78.408 71.019 ;
     RECT  7.8 69.547 8.664 71.029 ;
     RECT  61.8 69.517 62.952 71.029 ;
     RECT  75.216 70.965 75.24 71.059 ;
     RECT  61.8 71.029 63.24 71.075 ;
     RECT  74.256 71.059 75.24 71.075 ;
     RECT  4.032 70.981 4.296 71.083 ;
     RECT  30.768 70.995 31.224 71.083 ;
     RECT  99.6 70.403 100.056 71.083 ;
     RECT  60.432 71.029 60.456 71.113 ;
     RECT  74.256 71.075 74.28 71.147 ;
     RECT  14.784 69.419 14.952 71.161 ;
     RECT  34.8 68.971 35.112 71.187 ;
     RECT  34.8 71.187 35.688 71.275 ;
     RECT  67.2 69.011 67.512 71.279 ;
     RECT  56.4 70.315 57.624 71.315 ;
     RECT  22.56 67.819 22.584 71.317 ;
     RECT  67.2 71.279 67.608 71.363 ;
     RECT  87.792 71.327 87.816 71.411 ;
     RECT  51 69.291 51.312 71.443 ;
     RECT  85.536 71.349 85.56 71.459 ;
     RECT  50.544 71.443 51.312 71.531 ;
     RECT  22.176 71.317 22.584 71.541 ;
     RECT  21.744 71.541 22.584 71.651 ;
     RECT  71.28 71.605 71.304 71.689 ;
     RECT  72.6 68.435 72.912 71.797 ;
     RECT  7.44 71.029 8.664 71.845 ;
     RECT  22.56 71.651 22.584 71.891 ;
     RECT  68.784 71.797 68.808 71.891 ;
     RECT  72.6 71.797 73.464 71.891 ;
     RECT  93.072 71.797 93.096 71.891 ;
     RECT  103.872 71.797 103.896 71.891 ;
     RECT  7.392 71.845 8.664 71.929 ;
     RECT  45.6 68.971 45.912 72.117 ;
     RECT  92.928 72.095 92.952 72.179 ;
     RECT  45.312 72.117 45.912 72.205 ;
     RECT  63.216 71.075 63.24 72.227 ;
     RECT  72.6 71.891 72.912 72.309 ;
     RECT  46.944 72.309 46.968 72.397 ;
     RECT  72.48 72.309 72.912 72.397 ;
     RECT  33.36 67.283 33.384 72.419 ;
     RECT  38.736 72.421 38.76 72.505 ;
     RECT  88.8 68.971 89.112 72.661 ;
     RECT  88.32 72.661 89.112 72.693 ;
     RECT  87.552 72.693 89.112 72.781 ;
     RECT  51 71.531 51.312 72.805 ;
     RECT  4.272 71.083 4.296 72.853 ;
     RECT  5.424 68.971 6.264 72.853 ;
     RECT  88.32 72.781 89.112 72.875 ;
     RECT  56.4 71.315 56.712 72.885 ;
     RECT  4.272 72.853 6.264 72.939 ;
     RECT  49.872 72.565 49.896 72.939 ;
     RECT  38.4 72.885 38.424 72.973 ;
     RECT  56.064 72.885 56.712 72.973 ;
     RECT  4.272 72.939 4.296 72.995 ;
     RECT  31.2 71.083 31.224 72.995 ;
     RECT  76.56 73.141 76.584 73.235 ;
     RECT  13.2 2.151 13.512 73.439 ;
     RECT  33.216 73.363 33.24 73.451 ;
     RECT  7.8 71.929 8.664 73.461 ;
     RECT  12.528 73.439 13.512 73.523 ;
     RECT  24 70.787 25.8 73.571 ;
     RECT  54.72 73.461 54.744 73.571 ;
     RECT  50.88 72.805 51.312 73.572 ;
     RECT  39.744 69.059 40.512 73.653 ;
     RECT  42 68.4 42.024 73.653 ;
     RECT  45.6 72.205 45.912 73.717 ;
     RECT  39.744 73.653 42.024 73.763 ;
     RECT  44.208 73.717 44.232 73.811 ;
     RECT  45.264 73.717 45.912 73.811 ;
     RECT  94.2 69.625 94.512 73.813 ;
     RECT  29.4 69.547 29.712 73.875 ;
     RECT  29.28 73.875 29.712 73.963 ;
     RECT  98.448 73.861 98.472 73.963 ;
     RECT  5.424 72.939 6.264 74.061 ;
     RECT  7.8 73.461 9.096 74.099 ;
     RECT  56.4 72.973 56.712 74.101 ;
     RECT  63.792 73.653 63.816 74.101 ;
     RECT  31.056 73.909 31.08 74.125 ;
     RECT  10.896 70.211 10.92 74.147 ;
     RECT  58.464 73.973 58.488 74.155 ;
     RECT  63.792 74.101 64.44 74.155 ;
     RECT  72.6 72.397 72.912 74.323 ;
     RECT  56.4 74.101 57.336 74.339 ;
     RECT  64.416 74.155 64.44 74.339 ;
     RECT  68.784 74.323 68.808 74.411 ;
     RECT  72.24 74.323 72.912 74.411 ;
     RECT  91.344 74.101 91.368 74.475 ;
     RECT  74.064 74.485 74.088 74.579 ;
     RECT  72.6 74.411 72.912 74.591 ;
     RECT  69.792 74.357 69.816 74.627 ;
     RECT  72.6 74.591 73.56 74.675 ;
     RECT  94.2 73.813 94.776 74.677 ;
     RECT  6.096 74.061 6.264 74.723 ;
     RECT  25.776 73.571 25.8 74.723 ;
     RECT  33.648 74.677 33.672 74.735 ;
     RECT  34.8 71.275 35.112 74.735 ;
     RECT  56.4 74.339 56.712 74.735 ;
     RECT  94.2 74.677 95.208 74.761 ;
     RECT  33.648 74.735 35.352 74.819 ;
     RECT  55.536 74.735 56.712 74.819 ;
     RECT  33.84 74.819 35.112 74.893 ;
     RECT  24 73.571 24.456 74.915 ;
     RECT  54.672 74.869 54.696 74.953 ;
     RECT  72.6 74.675 73.032 74.953 ;
     RECT  14.928 71.161 14.952 75.013 ;
     RECT  14.784 75.013 14.952 75.115 ;
     RECT  6.096 74.723 6.168 75.157 ;
     RECT  20.112 70.507 20.136 75.299 ;
     RECT  5.856 75.157 6.168 75.307 ;
     RECT  4.512 75.253 4.536 75.347 ;
     RECT  49.536 75.253 49.56 75.347 ;
     RECT  92.688 75.253 92.712 75.347 ;
     RECT  98.112 75.253 98.136 75.347 ;
     RECT  26.208 75.685 26.232 75.769 ;
     RECT  83.4 70.635 83.712 75.829 ;
     RECT  17.808 70.787 18.912 75.875 ;
     RECT  83.136 75.829 83.712 75.923 ;
     RECT  55.728 74.819 56.712 76.117 ;
     RECT  54.768 76.117 56.712 76.395 ;
     RECT  6.096 75.307 6.168 76.403 ;
     RECT  88.8 72.875 89.112 76.405 ;
     RECT  7.8 74.099 8.112 76.469 ;
     RECT  88.8 76.405 89.688 76.489 ;
     RECT  71.232 76.405 71.256 76.499 ;
     RECT  58.032 76.435 58.056 76.523 ;
     RECT  6.24 76.463 6.264 76.547 ;
     RECT  17.856 75.875 18.912 76.651 ;
     RECT  29.4 73.963 29.712 76.661 ;
     RECT  61.8 71.075 62.112 76.703 ;
     RECT  28.848 76.661 29.712 76.749 ;
     RECT  61.68 76.703 62.112 76.787 ;
     RECT  34.8 74.893 35.112 76.789 ;
     RECT  64.848 76.405 64.872 76.813 ;
     RECT  34.8 76.789 35.928 76.873 ;
     RECT  7.8 76.469 8.232 76.907 ;
     RECT  55.872 76.395 56.712 76.971 ;
     RECT  96.912 76.885 96.936 76.971 ;
     RECT  45.6 73.811 45.912 76.981 ;
     RECT  49.344 76.597 49.368 76.981 ;
     RECT  51 73.572 51.312 76.981 ;
     RECT  49.344 76.981 51.312 77.035 ;
     RECT  36.528 77.139 36.552 77.227 ;
     RECT  38.688 77.139 38.712 77.227 ;
     RECT  45.6 76.981 46.344 77.227 ;
     RECT  30.816 77.173 30.84 77.257 ;
     RECT  50.064 77.035 51.312 77.315 ;
     RECT  45.6 77.227 45.912 77.461 ;
     RECT  88.8 76.489 89.112 77.461 ;
     RECT  6 77.395 6.024 77.483 ;
     RECT  67.2 71.363 67.512 77.493 ;
     RECT  13.2 73.523 13.512 77.523 ;
     RECT  14.928 75.115 14.952 77.523 ;
     RECT  13.2 77.523 14.952 77.547 ;
     RECT  33.024 77.461 33.048 77.547 ;
     RECT  60.624 77.461 60.648 77.547 ;
     RECT  20.016 76.357 20.04 77.555 ;
     RECT  34.8 76.873 35.304 77.555 ;
     RECT  67.2 77.493 68.28 77.581 ;
     RECT  13.2 77.547 14.232 77.611 ;
     RECT  24 74.915 24.312 77.907 ;
     RECT  94.2 74.761 94.512 77.907 ;
     RECT  83.4 75.923 83.712 77.941 ;
     RECT  24 77.907 24.408 77.995 ;
     RECT  88.8 77.461 90.072 77.995 ;
     RECT  91.584 77.907 91.608 77.995 ;
     RECT  93.12 77.907 94.512 77.995 ;
     RECT  13.2 77.611 13.512 78.005 ;
     RECT  45.504 77.461 45.912 78.005 ;
     RECT  83.4 77.941 83.832 78.025 ;
     RECT  50.16 77.315 51.312 78.069 ;
     RECT  43.296 77.989 43.32 78.073 ;
     RECT  86.496 77.941 86.52 78.083 ;
     RECT  12.912 78.005 13.512 78.093 ;
     RECT  44.88 78.005 45.912 78.093 ;
     RECT  50.16 78.069 52.152 78.123 ;
     RECT  29.4 76.749 29.712 78.325 ;
     RECT  50.592 78.123 52.152 78.379 ;
     RECT  29.4 78.325 30.216 78.409 ;
     RECT  29.4 78.409 29.976 78.443 ;
     RECT  29.4 78.443 29.712 78.565 ;
     RECT  56.4 76.971 56.712 78.645 ;
     RECT  19.92 78.325 19.944 78.659 ;
     RECT  45.504 78.093 45.912 78.659 ;
     RECT  31.872 78.645 31.896 78.733 ;
     RECT  56.4 78.645 56.808 78.733 ;
     RECT  88.8 77.995 90.024 78.899 ;
     RECT  88.8 78.899 89.64 78.955 ;
     RECT  27.36 78.901 27.384 78.995 ;
     RECT  67.2 77.581 67.512 79.045 ;
     RECT  29.04 78.565 29.712 79.093 ;
     RECT  31.248 79.045 31.272 79.147 ;
     RECT  28.8 79.093 29.712 79.187 ;
     RECT  26.208 78.901 26.232 79.199 ;
     RECT  45.6 78.659 45.912 79.199 ;
     RECT  71.088 79.123 71.112 79.199 ;
     RECT  67.2 79.045 68.472 79.275 ;
     RECT  5.664 79.199 5.688 79.283 ;
     RECT  16.896 79.199 16.92 79.283 ;
     RECT  25.68 79.199 26.232 79.283 ;
     RECT  42 73.763 42.024 79.283 ;
     RECT  45.6 79.199 46.056 79.283 ;
     RECT  70.704 79.199 71.112 79.283 ;
     RECT  49.296 79.413 49.32 79.501 ;
     RECT  72.6 74.953 72.912 79.573 ;
     RECT  72.48 79.573 72.912 79.659 ;
     RECT  39.744 73.763 40.512 79.699 ;
     RECT  29.4 79.187 29.712 79.775 ;
     RECT  39.744 79.699 40.632 79.787 ;
     RECT  29.4 79.775 29.832 79.859 ;
     RECT  88.8 78.955 89.112 79.989 ;
     RECT  18.6 76.651 18.912 80.101 ;
     RECT  85.68 80.181 85.704 80.245 ;
     RECT  85.68 80.245 86.04 80.291 ;
     RECT  5.76 80.211 5.784 80.299 ;
     RECT  9.744 80.211 9.768 80.299 ;
     RECT  88.08 79.989 89.112 80.299 ;
     RECT  86.016 80.291 86.04 80.329 ;
     RECT  33.744 80.101 33.768 80.427 ;
     RECT  31.296 80.351 31.32 80.435 ;
     RECT  10.896 80.245 10.92 80.483 ;
     RECT  26.208 79.283 26.232 80.483 ;
     RECT  37.392 80.467 37.416 80.555 ;
     RECT  92.448 80.565 92.472 80.653 ;
     RECT  95.616 80.565 95.64 80.653 ;
     RECT  71.232 79.56 71.256 80.683 ;
     RECT  38.16 80.659 38.184 80.747 ;
     RECT  29.4 79.859 29.712 80.851 ;
     RECT  21.744 80.851 21.768 80.939 ;
     RECT  25.584 80.851 25.608 80.939 ;
     RECT  29.4 80.851 29.976 80.939 ;
     RECT  41.952 79.733 41.976 81.059 ;
     RECT  17.664 80.101 18.912 81.205 ;
     RECT  17.328 81.205 18.912 81.347 ;
     RECT  34.8 77.555 35.112 81.525 ;
     RECT  79.824 81.445 79.848 81.529 ;
     RECT  39.744 79.787 40.512 81.539 ;
     RECT  61.8 76.787 62.112 81.811 ;
     RECT  48.672 81.781 48.696 81.875 ;
     RECT  61.8 81.811 62.472 81.899 ;
     RECT  90.624 82.079 90.648 82.163 ;
     RECT  83.4 78.025 83.712 82.387 ;
     RECT  34.512 81.525 35.112 82.403 ;
     RECT  27.312 82.357 27.336 82.421 ;
     RECT  88.8 80.299 89.112 82.421 ;
     RECT  16.512 82.387 16.536 82.475 ;
     RECT  82.656 82.387 83.712 82.475 ;
     RECT  43.056 82.515 43.08 82.603 ;
     RECT  91.872 82.549 91.896 82.633 ;
     RECT  72.6 79.659 72.912 82.655 ;
     RECT  78 71.019 78.312 82.677 ;
     RECT  71.856 82.655 72.912 82.739 ;
     RECT  77.232 82.677 79.176 82.765 ;
     RECT  94.2 77.995 94.512 82.771 ;
     RECT  27.264 82.421 27.336 82.787 ;
     RECT  88.8 82.421 89.544 82.859 ;
     RECT  93.264 82.771 94.512 82.859 ;
     RECT  26.784 82.847 26.808 82.931 ;
     RECT  74.016 82.501 74.04 82.987 ;
     RECT  77.232 82.765 78.312 82.992 ;
     RECT  39.024 82.963 39.048 83.051 ;
     RECT  58.176 83.077 58.2 83.179 ;
     RECT  18.6 81.347 18.912 83.189 ;
     RECT  25.584 82.677 25.608 83.219 ;
     RECT  17.28 83.155 17.304 83.243 ;
     RECT  22.512 83.221 22.536 83.307 ;
     RECT  45.6 79.283 45.912 83.347 ;
     RECT  18.48 83.189 18.912 83.435 ;
     RECT  45.6 83.347 46.056 83.435 ;
     RECT  29.4 80.939 29.712 83.605 ;
     RECT  71.28 83.567 71.304 83.651 ;
     RECT  29.28 83.605 29.712 83.691 ;
     RECT  66.096 83.701 66.12 83.785 ;
     RECT  63.696 83.759 64.104 83.843 ;
     RECT  40.2 81.539 40.512 83.999 ;
     RECT  37.584 83.999 37.608 84.083 ;
     RECT  40.2 83.999 41.064 84.083 ;
     RECT  61.8 81.899 62.112 84.325 ;
     RECT  51 78.379 51.312 84.341 ;
     RECT  33.072 84.277 33.096 84.361 ;
     RECT  47.712 84.213 47.736 84.395 ;
     RECT  52.464 83.701 52.488 84.409 ;
     RECT  30.816 84.021 30.84 84.563 ;
     RECT  67.2 79.275 67.512 84.597 ;
     RECT  65.472 84.565 65.496 84.651 ;
     RECT  21.648 84.789 21.672 84.877 ;
     RECT  70.56 84.819 70.584 84.907 ;
     RECT  66.624 84.597 67.512 84.912 ;
     RECT  26.736 84.911 26.76 84.995 ;
     RECT  42.72 84.911 42.744 84.995 ;
     RECT  50.112 84.341 51.312 85.139 ;
     RECT  69.36 84.853 69.384 85.139 ;
     RECT  58.704 84.901 58.728 85.163 ;
     RECT  54.144 85.203 54.168 85.291 ;
     RECT  55.296 85.052 55.32 85.291 ;
     RECT  18.6 83.435 18.912 85.301 ;
     RECT  33.6 85.333 33.624 85.365 ;
     RECT  21.12 85.295 21.144 85.379 ;
     RECT  18.6 85.301 19.032 85.389 ;
     RECT  33.36 85.365 33.624 85.419 ;
     RECT  40.2 84.083 40.872 85.419 ;
     RECT  31.584 84.917 31.608 85.44 ;
     RECT  33.36 85.419 33.384 85.453 ;
     RECT  61.584 84.325 62.112 85.547 ;
     RECT  60.384 85.487 60.408 85.571 ;
     RECT  0.192 86.725 0.216 86.773 ;
     RECT  0.192 86.773 0.312 86.867 ;
     RECT  0.192 86.867 0.216 87.203 ;
     RECT  54.576 87.221 54.6 87.309 ;
     RECT  2.4 69.827 2.712 98.289 ;
     RECT  7.8 76.907 8.112 98.289 ;
     RECT  13.2 78.093 13.512 98.289 ;
     RECT  18.6 85.389 18.912 98.289 ;
     RECT  24 77.995 24.312 98.289 ;
     RECT  29.4 83.691 29.712 98.289 ;
     RECT  34.8 82.403 35.112 98.289 ;
     RECT  40.2 85.419 40.512 98.289 ;
     RECT  45.6 83.435 45.912 98.289 ;
     RECT  51 85.139 51.312 98.289 ;
     RECT  56.4 78.733 56.712 98.289 ;
     RECT  61.8 85.547 62.112 98.289 ;
     RECT  67.2 84.912 67.512 98.289 ;
     RECT  72.6 82.739 72.912 98.289 ;
     RECT  78 82.992 78.312 98.289 ;
     RECT  83.4 82.475 83.712 98.289 ;
     RECT  88.8 82.859 89.112 98.289 ;
     RECT  94.2 82.859 94.512 98.289 ;
     RECT  99.6 71.083 99.912 98.289 ;
     RECT  105 70.029 105.312 98.289 ;
     RECT  110.4 68.139 110.712 98.289 ;
     RECT  115.8 67.321 116.112 98.289 ;
     RECT  121.2 2.151 121.512 98.289 ;
     RECT  126.6 55.955 126.912 98.289 ;
     RECT  132 38.443 132.312 98.289 ;
     RECT  137.4 50.731 137.712 98.289 ;
     RECT  142.8 53.581 143.112 98.289 ;
     RECT  148.2 34.835 148.512 98.289 ;
     RECT  153.6 68.425 153.912 98.289 ;
     RECT  2.4 98.289 2.52 98.303 ;
     RECT  7.8 98.289 7.92 98.303 ;
     RECT  13.2 98.289 13.32 98.303 ;
     RECT  18.6 98.289 18.72 98.303 ;
     RECT  24 98.289 24.12 98.303 ;
     RECT  29.4 98.289 29.52 98.303 ;
     RECT  34.8 98.289 34.92 98.303 ;
     RECT  40.2 98.289 40.32 98.303 ;
     RECT  45.6 98.289 45.72 98.303 ;
     RECT  51 98.289 51.12 98.303 ;
     RECT  56.4 98.289 56.52 98.303 ;
     RECT  61.8 98.289 61.92 98.303 ;
     RECT  67.2 98.289 67.32 98.303 ;
     RECT  72.6 98.289 72.72 98.303 ;
     RECT  78 98.289 78.12 98.303 ;
     RECT  83.4 98.289 83.52 98.303 ;
     RECT  88.8 98.289 88.92 98.303 ;
     RECT  94.2 98.289 94.32 98.303 ;
     RECT  99.6 98.289 99.72 98.303 ;
     RECT  105 98.289 105.12 98.303 ;
     RECT  110.4 98.289 110.52 98.303 ;
     RECT  115.8 98.289 115.92 98.303 ;
     RECT  121.2 98.289 121.32 98.303 ;
     RECT  126.6 98.289 126.72 98.303 ;
     RECT  132 98.289 132.12 98.303 ;
     RECT  137.4 98.289 137.52 98.303 ;
     RECT  142.8 98.289 142.92 98.303 ;
     RECT  148.2 98.289 148.32 98.303 ;
     RECT  153.6 98.289 153.72 98.303 ;
    LAYER M6 ;
     RECT  0.181 86.784 0.323 86.816 ;
     RECT  1.813 5.056 1.861 5.088 ;
     RECT  1.813 7.488 1.861 7.52 ;
     RECT  1.861 4.48 1.909 7.52 ;
     RECT  1.813 9.088 1.909 10.272 ;
     RECT  1.861 11.584 1.909 12.512 ;
     RECT  1.909 3.136 1.957 7.712 ;
     RECT  1.909 9.024 1.957 10.272 ;
     RECT  1.909 11.584 1.957 13.024 ;
     RECT  1.957 3.136 2.005 13.664 ;
     RECT  1.909 15.936 2.005 15.968 ;
     RECT  2.005 3.072 2.053 16.48 ;
     RECT  2.053 2.944 2.219 16.48 ;
     RECT  2.165 67.264 2.245 67.296 ;
     RECT  2.245 67.264 3.443 67.616 ;
     RECT  4.501 72.896 5.365 72.928 ;
     RECT  4.501 75.264 5.365 75.296 ;
     RECT  5.365 72.896 5.419 75.296 ;
     RECT  5.419 73.984 5.459 75.296 ;
     RECT  5.653 79.232 5.739 79.264 ;
     RECT  5.459 75.264 5.891 75.296 ;
     RECT  5.685 77.44 6.035 77.472 ;
     RECT  4.021 68.928 6.659 68.96 ;
     RECT  4.006 71.04 7.381 71.072 ;
     RECT  7.381 71.04 7.475 71.904 ;
     RECT  6.229 76.48 8.197 76.512 ;
     RECT  8.197 76.48 8.243 76.896 ;
     RECT  7.475 71.168 8.245 71.904 ;
     RECT  8.243 76.864 8.245 76.896 ;
     RECT  8.245 76.864 8.299 78.048 ;
     RECT  2.219 3.072 8.483 16.48 ;
     RECT  8.245 71.168 8.565 72.864 ;
     RECT  8.565 71.168 8.619 73.504 ;
     RECT  8.619 71.168 8.811 71.904 ;
     RECT  8.757 69.504 9.251 69.536 ;
     RECT  3.443 67.584 11.077 67.616 ;
     RECT  9.637 69.44 11.077 69.472 ;
     RECT  11.077 67.584 11.189 69.472 ;
     RECT  11.189 67.584 11.243 70.176 ;
     RECT  5.749 80.256 11.317 80.288 ;
     RECT  11.317 80.256 11.371 81.248 ;
     RECT  11.243 70.144 11.459 70.176 ;
     RECT  8.619 73.472 12.563 73.504 ;
     RECT  8.299 78.016 12.947 78.048 ;
     RECT  11.371 81.216 14.197 81.248 ;
     RECT  8.811 71.872 14.251 71.904 ;
     RECT  14.178 77.568 14.251 77.6 ;
     RECT  14.754 75.072 14.827 75.104 ;
     RECT  14.773 77.056 14.963 77.536 ;
     RECT  14.773 71.104 15.349 71.136 ;
     RECT  15.33 69.376 15.403 69.408 ;
     RECT  15.349 70.72 15.403 71.136 ;
     RECT  14.963 77.504 16.885 77.536 ;
     RECT  16.885 77.504 16.939 79.264 ;
     RECT  16.939 78.08 16.954 79.264 ;
     RECT  14.197 81.216 17.269 82.464 ;
     RECT  17.269 81.216 17.363 83.232 ;
     RECT  15.403 70.72 18.165 70.752 ;
     RECT  11.243 67.584 18.181 67.616 ;
     RECT  18.165 70.464 18.219 70.752 ;
     RECT  17.845 76.608 18.229 76.64 ;
     RECT  16.954 78.08 18.229 78.112 ;
     RECT  18.229 76.608 18.283 78.112 ;
     RECT  17.363 82.432 18.469 83.232 ;
     RECT  18.469 82.432 18.539 83.424 ;
     RECT  18.219 70.464 19.141 70.496 ;
     RECT  19.141 70.208 19.187 70.496 ;
     RECT  18.181 67.584 19.189 67.936 ;
     RECT  19.187 70.208 19.189 70.24 ;
     RECT  19.189 67.584 19.243 70.24 ;
     RECT  18.283 77.184 19.909 77.216 ;
     RECT  19.909 77.184 20.051 78.368 ;
     RECT  18.485 85.312 21.155 85.344 ;
     RECT  19.243 67.584 21.637 67.616 ;
     RECT  21.637 67.264 21.685 67.616 ;
     RECT  19.243 69.12 21.739 69.152 ;
     RECT  21.685 71.552 21.779 71.584 ;
     RECT  21.685 67.264 22.451 67.808 ;
     RECT  18.539 82.432 22.501 82.464 ;
     RECT  21.733 80.896 22.571 80.928 ;
     RECT  22.501 82.432 22.571 83.296 ;
     RECT  21.637 84.8 22.571 84.832 ;
     RECT  22.451 67.264 24.354 67.296 ;
     RECT  20.051 78.336 24.373 78.368 ;
     RECT  24.354 67.264 24.427 67.488 ;
     RECT  22.165 71.36 24.469 71.392 ;
     RECT  24.738 73.472 24.811 73.504 ;
     RECT  24.373 77.952 25.515 78.368 ;
     RECT  22.571 82.432 25.573 82.464 ;
     RECT  25.461 80.896 25.643 80.928 ;
     RECT  25.515 78.336 25.646 78.368 ;
     RECT  25.646 78.336 25.715 79.264 ;
     RECT  25.715 78.336 25.846 78.944 ;
     RECT  24.469 71.04 25.957 71.392 ;
     RECT  25.957 70.72 26.027 71.392 ;
     RECT  25.573 82.432 26.819 82.912 ;
     RECT  26.819 82.432 27.301 82.464 ;
     RECT  27.301 82.368 27.302 82.464 ;
     RECT  25.846 78.4 27.395 78.944 ;
     RECT  27.395 78.4 28.789 78.432 ;
     RECT  26.197 75.712 28.837 75.744 ;
     RECT  28.837 75.712 28.907 76.704 ;
     RECT  27.302 82.368 29.269 82.4 ;
     RECT  26.725 84.928 29.269 84.96 ;
     RECT  29.269 82.368 29.675 84.96 ;
     RECT  28.789 78.4 29.797 79.136 ;
     RECT  29.621 80.896 29.797 80.928 ;
     RECT  29.797 78.4 29.813 80.928 ;
     RECT  29.813 77.184 29.867 80.928 ;
     RECT  29.867 80.896 29.987 80.928 ;
     RECT  25.973 69.184 29.989 69.216 ;
     RECT  26.027 71.04 30.133 71.392 ;
     RECT  29.989 69.184 30.187 69.536 ;
     RECT  30.133 71.04 30.803 71.52 ;
     RECT  29.867 77.184 30.851 79.136 ;
     RECT  29.675 84.032 30.851 84.96 ;
     RECT  28.853 73.92 31.045 73.952 ;
     RECT  31.045 73.92 31.091 74.08 ;
     RECT  30.851 78.336 31.283 79.136 ;
     RECT  30.851 84.288 31.573 84.96 ;
     RECT  31.283 78.336 31.93 78.688 ;
     RECT  31.861 76.8 33.013 76.832 ;
     RECT  31.93 78.336 33.013 78.432 ;
     RECT  31.573 84.288 33.107 85.408 ;
     RECT  31.091 74.048 33.186 74.08 ;
     RECT  33.186 73.408 33.205 74.08 ;
     RECT  33.205 73.408 33.259 74.72 ;
     RECT  8.483 3.072 33.395 16.352 ;
     RECT  31.285 80.384 33.653 80.416 ;
     RECT  33.259 74.688 33.683 74.72 ;
     RECT  29.675 82.368 33.707 82.4 ;
     RECT  30.803 71.488 33.899 71.52 ;
     RECT  33.829 74.752 33.899 74.848 ;
     RECT  33.653 80.384 34.165 80.544 ;
     RECT  34.165 80.384 34.219 81.568 ;
     RECT  34.219 80.512 34.547 81.568 ;
     RECT  33.899 74.752 35.691 74.784 ;
     RECT  35.637 71.232 35.71 71.264 ;
     RECT  33.013 76.8 35.939 78.432 ;
     RECT  30.421 68.928 36.803 68.96 ;
     RECT  34.547 80.512 38.149 80.544 ;
     RECT  35.637 72.896 38.435 72.928 ;
     RECT  38.149 80.512 38.709 80.736 ;
     RECT  35.939 77.184 38.763 78.432 ;
     RECT  37.573 84.032 39.013 84.064 ;
     RECT  38.709 79.744 39.083 80.736 ;
     RECT  39.013 83.008 39.083 84.064 ;
     RECT  24.427 67.264 39.285 67.296 ;
     RECT  39.278 68.992 39.285 69.024 ;
     RECT  39.285 67.264 39.347 69.024 ;
     RECT  38.725 72.448 39.797 72.48 ;
     RECT  39.797 71.488 39.851 73.696 ;
     RECT  39.851 71.488 39.875 71.52 ;
     RECT  38.763 77.568 39.923 78.432 ;
     RECT  39.923 78.336 39.971 78.432 ;
     RECT  33.107 85.376 40.883 85.408 ;
     RECT  39.851 73.664 41.075 73.696 ;
     RECT  39.083 84.032 41.075 84.064 ;
     RECT  39.347 67.264 41.411 68.384 ;
     RECT  39.083 79.744 41.987 80.544 ;
     RECT  43.045 82.56 43.253 82.592 ;
     RECT  39.971 78.4 43.285 78.432 ;
     RECT  43.253 82.56 43.307 83.424 ;
     RECT  42.709 84.928 43.307 84.96 ;
     RECT  33.395 14.784 44.147 16.352 ;
     RECT  41.411 67.264 45.013 67.872 ;
     RECT  45.013 67.264 45.099 68.96 ;
     RECT  43.861 70.72 45.099 70.752 ;
     RECT  44.197 73.728 45.299 73.76 ;
     RECT  45.045 72.128 45.347 72.16 ;
     RECT  43.285 78.016 45.474 78.432 ;
     RECT  45.474 77.504 45.998 78.432 ;
     RECT  41.987 80.512 45.998 80.544 ;
     RECT  45.998 77.504 46.067 80.544 ;
     RECT  46.067 77.504 46.133 78.048 ;
     RECT  46.133 77.184 46.187 78.048 ;
     RECT  46.187 77.184 46.309 77.216 ;
     RECT  46.309 76.992 46.355 77.216 ;
     RECT  43.307 83.392 47.669 83.424 ;
     RECT  47.669 83.392 47.701 84.256 ;
     RECT  47.701 83.392 47.723 84.384 ;
     RECT  47.723 84.224 47.747 84.384 ;
     RECT  46.067 80.512 48.661 80.544 ;
     RECT  48.661 80.512 48.693 81.824 ;
     RECT  48.693 79.424 48.747 81.824 ;
     RECT  44.147 14.784 49.331 14.816 ;
     RECT  46.933 72.32 49.525 72.352 ;
     RECT  49.525 75.264 49.594 75.296 ;
     RECT  46.355 76.992 50.099 77.024 ;
     RECT  48.747 79.424 50.155 80.544 ;
     RECT  49.525 72.32 50.485 72.928 ;
     RECT  50.485 71.488 50.579 72.928 ;
     RECT  50.101 78.08 50.581 78.112 ;
     RECT  47.747 84.352 50.613 84.384 ;
     RECT  50.581 78.08 50.667 78.368 ;
     RECT  50.155 80.512 50.667 80.544 ;
     RECT  49.525 68.992 50.869 69.024 ;
     RECT  50.579 72.32 50.869 72.928 ;
     RECT  44.147 16.32 50.915 16.352 ;
     RECT  50.869 68.992 50.915 69.28 ;
     RECT  50.667 78.08 52.117 78.112 ;
     RECT  52.117 78.08 52.163 78.368 ;
     RECT  50.613 83.712 52.499 84.384 ;
     RECT  33.395 3.072 54.323 13.472 ;
     RECT  54.565 87.232 54.699 87.264 ;
     RECT  50.869 72.32 54.755 73.504 ;
     RECT  45.099 67.264 55.237 67.296 ;
     RECT  50.915 69.248 55.237 69.28 ;
     RECT  54.133 85.248 55.285 85.28 ;
     RECT  55.285 85.12 55.331 85.28 ;
     RECT  54.661 74.88 55.525 74.912 ;
     RECT  55.525 74.752 55.595 74.912 ;
     RECT  55.237 69.248 55.797 70.432 ;
     RECT  54.755 72.32 55.797 72.352 ;
     RECT  54.757 76.352 55.842 76.384 ;
     RECT  55.797 69.248 55.851 72.352 ;
     RECT  52.163 78.336 55.861 78.368 ;
     RECT  55.842 76.352 55.907 76.96 ;
     RECT  55.907 76.48 55.915 76.96 ;
     RECT  55.861 78.336 55.915 78.688 ;
     RECT  55.915 78.656 56.819 78.688 ;
     RECT  56.053 72.896 57.301 72.928 ;
     RECT  55.595 74.88 57.301 74.912 ;
     RECT  55.915 76.48 58.067 76.512 ;
     RECT  55.237 67.264 58.677 67.872 ;
     RECT  55.851 69.248 58.677 71.072 ;
     RECT  57.301 72.896 58.731 74.912 ;
     RECT  58.165 83.136 58.795 83.168 ;
     RECT  55.331 85.12 58.795 85.152 ;
     RECT  54.323 3.072 59.573 11.936 ;
     RECT  58.677 67.264 59.627 71.072 ;
     RECT  59.627 67.392 60.467 71.072 ;
     RECT  60.373 85.504 61.573 85.536 ;
     RECT  61.573 84.608 61.619 85.536 ;
     RECT  60.613 77.504 61.669 77.536 ;
     RECT  61.669 76.736 62.507 77.536 ;
     RECT  62.437 81.856 62.507 81.888 ;
     RECT  59.573 2.24 63.155 11.936 ;
     RECT  60.467 67.392 63.531 70.432 ;
     RECT  61.619 84.608 63.662 84.64 ;
     RECT  63.531 67.392 63.669 69.984 ;
     RECT  58.731 74.88 63.781 74.912 ;
     RECT  63.781 73.664 63.851 74.912 ;
     RECT  63.662 83.776 64.115 84.64 ;
     RECT  63.669 67.264 64.427 69.984 ;
     RECT  63.851 74.112 64.451 74.912 ;
     RECT  62.507 76.736 64.837 76.768 ;
     RECT  64.837 76.416 64.883 76.768 ;
     RECT  64.115 84.608 66.085 84.64 ;
     RECT  66.085 83.712 66.613 84.64 ;
     RECT  54.323 13.312 66.995 13.472 ;
     RECT  66.995 13.312 67.619 13.344 ;
     RECT  63.797 71.296 67.619 71.328 ;
     RECT  63.155 2.24 67.955 11.808 ;
     RECT  64.451 74.88 68.085 74.912 ;
     RECT  64.883 76.416 68.085 76.448 ;
     RECT  68.085 76.416 68.139 77.536 ;
     RECT  68.139 77.504 68.291 77.536 ;
     RECT  68.773 71.616 68.843 71.84 ;
     RECT  68.085 74.368 69.827 74.912 ;
     RECT  66.613 83.712 70.645 84.896 ;
     RECT  70.645 83.584 70.699 84.896 ;
     RECT  68.437 79.232 71.077 79.264 ;
     RECT  71.077 79.168 71.147 79.264 ;
     RECT  70.699 83.584 71.147 83.744 ;
     RECT  69.827 74.624 71.221 74.912 ;
     RECT  71.221 76.416 71.29 76.448 ;
     RECT  68.843 71.616 71.315 71.648 ;
     RECT  71.147 83.584 71.315 83.616 ;
     RECT  71.221 79.616 71.915 80.672 ;
     RECT  71.221 74.368 72.275 74.912 ;
     RECT  72.437 72.32 72.515 72.352 ;
     RECT  71.915 79.616 72.515 79.648 ;
     RECT  72.275 74.624 73.043 74.912 ;
     RECT  67.955 4.224 73.331 11.808 ;
     RECT  73.429 71.808 73.461 71.84 ;
     RECT  73.461 71.104 73.515 71.84 ;
     RECT  73.043 74.624 73.571 74.656 ;
     RECT  71.845 82.688 74.005 82.72 ;
     RECT  74.005 82.688 74.051 82.976 ;
     RECT  73.515 71.104 74.291 71.136 ;
     RECT  74.053 74.496 74.731 74.528 ;
     RECT  74.677 72.704 76.533 72.736 ;
     RECT  76.533 72.704 76.606 73.184 ;
     RECT  74.051 82.944 77.221 82.976 ;
     RECT  77.221 82.688 77.267 82.976 ;
     RECT  64.427 67.264 78.419 69.28 ;
     RECT  75.205 70.976 78.419 71.008 ;
     RECT  77.267 82.688 79.157 82.72 ;
     RECT  79.157 81.472 79.211 82.72 ;
     RECT  79.211 81.472 79.859 81.504 ;
     RECT  78.419 67.264 80.341 67.296 ;
     RECT  78.419 68.672 80.341 69.28 ;
     RECT  82.165 70.656 83.125 70.688 ;
     RECT  83.125 75.84 83.194 75.872 ;
     RECT  83.125 70.656 84.45 71.392 ;
     RECT  84.45 70.592 84.523 71.392 ;
     RECT  85.669 80.192 85.739 80.224 ;
     RECT  83.797 77.952 86.531 77.984 ;
     RECT  80.341 67.264 87.285 69.28 ;
     RECT  84.523 71.36 87.285 71.392 ;
     RECT  87.285 67.264 87.358 71.392 ;
     RECT  87.358 71.36 87.827 71.392 ;
     RECT  86.005 80.256 88.069 80.288 ;
     RECT  88.069 80 88.115 80.288 ;
     RECT  76.606 72.704 88.309 72.736 ;
     RECT  82.645 82.432 89.509 82.464 ;
     RECT  88.309 72.704 89.589 72.864 ;
     RECT  88.115 80 89.589 80.032 ;
     RECT  89.509 82.432 89.589 82.848 ;
     RECT  89.589 72.128 89.653 72.864 ;
     RECT  89.653 72.128 89.707 74.144 ;
     RECT  89.653 76.416 89.722 76.448 ;
     RECT  89.589 78.912 89.966 80.032 ;
     RECT  89.966 78.848 89.973 80.032 ;
     RECT  89.973 77.952 90.027 80.032 ;
     RECT  90.027 77.952 90.035 78.88 ;
     RECT  89.589 82.112 90.659 82.848 ;
     RECT  89.707 74.112 91.333 74.144 ;
     RECT  91.333 74.112 91.379 74.464 ;
     RECT  87.358 67.264 91.502 69.28 ;
     RECT  91.502 67.264 91.571 69.536 ;
     RECT  90.659 82.56 91.907 82.848 ;
     RECT  91.379 74.432 92.654 74.464 ;
     RECT  92.654 74.432 92.715 75.296 ;
     RECT  92.715 74.688 92.723 75.296 ;
     RECT  89.707 72.128 92.963 72.16 ;
     RECT  93.038 71.808 93.107 71.84 ;
     RECT  91.907 82.816 93.299 82.848 ;
     RECT  91.571 67.264 93.445 69.472 ;
     RECT  92.723 74.688 94.741 74.72 ;
     RECT  93.445 67.264 95.075 69.6 ;
     RECT  94.741 73.92 95.219 74.72 ;
     RECT  92.437 80.576 95.651 80.608 ;
     RECT  90.035 77.952 96.878 77.984 ;
     RECT  96.878 76.928 96.939 77.984 ;
     RECT  96.939 76.928 96.947 76.96 ;
     RECT  67.955 2.24 97.717 2.272 ;
     RECT  98.101 75.264 98.17 75.296 ;
     RECT  95.219 73.92 98.483 73.952 ;
     RECT  95.075 67.264 99.381 69.472 ;
     RECT  99.381 67.264 99.435 71.072 ;
     RECT  99.435 70.272 99.454 71.072 ;
     RECT  97.717 2.048 100.213 2.272 ;
     RECT  73.331 4.224 100.213 10.592 ;
     RECT  99.435 67.264 103.842 68.192 ;
     RECT  103.842 67.264 103.861 68.832 ;
     RECT  99.454 71.04 103.861 71.072 ;
     RECT  103.861 67.264 103.915 71.84 ;
     RECT  103.915 71.808 103.93 71.84 ;
     RECT  103.915 69.952 105.491 69.984 ;
     RECT  103.915 67.264 109.139 68.192 ;
     RECT  109.139 67.264 114.707 68.128 ;
     RECT  114.707 68.096 116.293 68.128 ;
     RECT  116.293 67.264 117.779 68.128 ;
     RECT  123.973 12.736 124.115 12.768 ;
     RECT  100.213 2.048 124.163 10.592 ;
     RECT  124.163 2.048 126.035 2.272 ;
     RECT  117.779 67.264 126.059 67.36 ;
     RECT  124.163 4.224 126.114 10.592 ;
     RECT  63.797 15.104 126.133 15.136 ;
     RECT  126.114 4.224 126.187 11.744 ;
     RECT  126.133 15.104 126.187 15.328 ;
     RECT  126.181 55.808 126.251 55.84 ;
     RECT  126.187 4.224 127.139 10.592 ;
     RECT  126.035 2.24 127.715 2.272 ;
     RECT  128.725 31.872 128.811 31.904 ;
     RECT  128.725 35.904 128.811 35.936 ;
     RECT  127.139 4.224 129.141 10.208 ;
     RECT  126.469 11.904 129.141 11.936 ;
     RECT  129.141 4.224 129.195 12.704 ;
     RECT  129.195 12.672 129.251 12.704 ;
     RECT  126.187 15.296 129.349 15.328 ;
     RECT  129.349 19.904 129.451 19.936 ;
     RECT  129.378 21.824 129.451 21.856 ;
     RECT  129.195 4.224 130.163 11.36 ;
     RECT  130.163 4.224 130.309 10.208 ;
     RECT  128.757 34.176 130.501 34.208 ;
     RECT  130.309 3.392 131.179 10.208 ;
     RECT  131.173 22.784 131.243 23.072 ;
     RECT  129.349 15.168 131.605 15.328 ;
     RECT  131.605 15.168 131.699 15.456 ;
     RECT  130.501 34.112 131.874 34.272 ;
     RECT  131.874 34.112 131.947 34.336 ;
     RECT  131.893 31.872 131.962 31.904 ;
     RECT  131.947 34.24 132.661 34.336 ;
     RECT  129.925 39.744 132.779 39.776 ;
     RECT  132.725 37.568 132.803 38.432 ;
     RECT  126.005 65.152 133.427 65.184 ;
     RECT  133.333 18.752 133.525 18.784 ;
     RECT  133.493 20.48 133.525 20.512 ;
     RECT  133.525 18.752 133.571 20.512 ;
     RECT  133.571 18.752 133.611 20 ;
     RECT  131.179 3.84 133.859 10.208 ;
     RECT  134.005 65.024 134.074 65.056 ;
     RECT  133.333 25.024 134.453 25.056 ;
     RECT  131.699 15.296 134.485 15.456 ;
     RECT  134.453 25.024 134.507 26.336 ;
     RECT  133.941 13.056 134.531 13.088 ;
     RECT  134.507 25.6 134.531 26.336 ;
     RECT  133.859 3.904 134.579 10.208 ;
     RECT  134.531 25.6 134.579 25.632 ;
     RECT  135.086 54.144 135.155 54.176 ;
     RECT  133.909 44.672 136.053 44.704 ;
     RECT  135.086 47.232 136.053 47.264 ;
     RECT  136.053 44.672 136.107 47.264 ;
     RECT  136.107 44.672 136.126 46.816 ;
     RECT  133.333 28.736 136.245 28.768 ;
     RECT  132.661 34.24 136.259 34.976 ;
     RECT  136.245 28.736 136.299 29.472 ;
     RECT  136.299 29.44 136.373 29.472 ;
     RECT  136.373 29.44 136.427 29.664 ;
     RECT  135.541 31.872 136.787 31.904 ;
     RECT  134.485 15.296 136.933 16.288 ;
     RECT  131.243 23.04 137.006 23.072 ;
     RECT  136.837 20.48 137.067 20.512 ;
     RECT  137.006 23.04 137.075 23.392 ;
     RECT  134.005 18.688 137.973 18.72 ;
     RECT  136.427 29.632 137.973 29.664 ;
     RECT  136.259 34.24 137.973 34.272 ;
     RECT  137.973 29.632 137.987 29.984 ;
     RECT  132.803 37.568 137.989 37.6 ;
     RECT  137.941 20.608 138.027 20.64 ;
     RECT  137.966 22.848 138.035 22.88 ;
     RECT  137.987 29.952 138.046 29.984 ;
     RECT  138.158 50.688 138.181 50.72 ;
     RECT  138.165 41.856 138.21 41.888 ;
     RECT  126.469 55.68 138.219 55.712 ;
     RECT  138.181 50.432 138.227 50.72 ;
     RECT  138.21 41.28 138.238 41.888 ;
     RECT  137.973 33.792 138.283 34.272 ;
     RECT  138.227 50.432 138.283 50.464 ;
     RECT  134.579 4.224 138.594 10.208 ;
     RECT  138.594 3.712 138.613 10.208 ;
     RECT  137.989 36.48 139.237 37.6 ;
     RECT  138.238 41.28 139.253 41.312 ;
     RECT  139.237 36.48 139.307 38.176 ;
     RECT  139.253 40.256 139.307 41.312 ;
     RECT  138.283 33.792 139.317 33.824 ;
     RECT  139.307 36.48 139.371 37.6 ;
     RECT  138.613 26.56 139.669 26.592 ;
     RECT  136.933 15.296 139.715 16.544 ;
     RECT  139.669 25.6 139.755 26.592 ;
     RECT  137.973 18.368 140.341 18.72 ;
     RECT  139.317 33.472 140.395 33.824 ;
     RECT  140.341 18.368 140.789 19.04 ;
     RECT  140.789 18.368 140.843 19.744 ;
     RECT  140.843 18.688 141.155 19.744 ;
     RECT  139.307 40.256 141.299 40.288 ;
     RECT  141.157 32.128 141.301 32.16 ;
     RECT  141.301 31.616 141.355 32.16 ;
     RECT  139.371 37.568 141.971 37.6 ;
     RECT  136.126 44.672 142.069 44.704 ;
     RECT  136.126 46.784 142.069 46.816 ;
     RECT  142.069 44.672 142.123 47.584 ;
     RECT  142.123 44.672 142.138 45.6 ;
     RECT  141.355 31.616 142.163 31.648 ;
     RECT  138.613 3.392 142.453 10.208 ;
     RECT  142.123 47.552 142.453 47.584 ;
     RECT  142.138 44.672 142.547 44.768 ;
     RECT  142.517 50.752 142.549 50.784 ;
     RECT  142.453 47.552 142.571 47.84 ;
     RECT  142.549 50.752 142.595 51.04 ;
     RECT  142.595 51.008 142.635 51.04 ;
     RECT  142.693 12.16 143.093 12.192 ;
     RECT  139.715 15.296 143.093 15.328 ;
     RECT  143.093 11.584 143.147 12.192 ;
     RECT  143.093 14.848 143.219 15.328 ;
     RECT  139.755 26.56 143.221 26.592 ;
     RECT  143.221 26.56 143.267 26.784 ;
     RECT  126.059 67.328 143.285 67.36 ;
     RECT  142.581 53.504 143.339 53.536 ;
     RECT  142.453 3.328 143.507 10.208 ;
     RECT  141.155 18.688 143.605 19.552 ;
     RECT  143.507 3.328 143.797 9.696 ;
     RECT  143.797 2.88 143.851 9.696 ;
     RECT  138.469 35.136 144.179 35.168 ;
     RECT  143.173 23.872 144.181 23.904 ;
     RECT  140.395 33.792 144.229 33.824 ;
     RECT  144.181 23.872 144.235 24.288 ;
     RECT  139.525 30.08 144.693 30.112 ;
     RECT  142.547 44.736 144.693 44.768 ;
     RECT  144.229 33.792 144.747 35.104 ;
     RECT  144.693 29.952 144.755 30.112 ;
     RECT  144.755 29.952 144.766 29.984 ;
     RECT  144.693 36.992 144.766 37.024 ;
     RECT  144.235 24.256 144.995 24.288 ;
     RECT  144.693 28.48 145.091 28.512 ;
     RECT  144.747 33.792 145.122 34.656 ;
     RECT  145.122 33.024 145.195 34.656 ;
     RECT  143.221 22.144 145.379 22.176 ;
     RECT  144.693 43.904 145.379 44.768 ;
     RECT  145.461 45.568 145.534 45.6 ;
     RECT  142.571 47.552 145.859 47.584 ;
     RECT  143.851 4.224 145.909 9.696 ;
     RECT  143.147 11.584 145.909 11.616 ;
     RECT  143.219 15.296 145.909 15.328 ;
     RECT  145.909 4.224 145.963 11.616 ;
     RECT  145.909 14.016 146.147 15.328 ;
     RECT  143.605 18.688 146.387 19.68 ;
     RECT  145.379 43.904 146.531 43.936 ;
     RECT  143.267 26.752 147.011 26.784 ;
     RECT  146.147 15.296 147.013 15.328 ;
     RECT  145.195 33.792 147.107 34.656 ;
     RECT  146.387 18.688 147.573 19.04 ;
     RECT  147.566 25.664 147.635 25.696 ;
     RECT  147.107 34.624 147.683 34.656 ;
     RECT  143.851 2.88 148.115 2.912 ;
     RECT  145.963 4.224 148.115 10.912 ;
     RECT  148.91 30.784 148.917 30.816 ;
     RECT  148.917 28.992 148.979 30.816 ;
     RECT  148.979 28.992 148.99 29.6 ;
     RECT  147.013 15.296 149.109 15.52 ;
     RECT  149.109 14.208 149.182 15.52 ;
     RECT  149.73 11.136 149.803 11.168 ;
     RECT  147.573 18.432 149.922 19.04 ;
     RECT  148.115 4.224 149.939 9.696 ;
     RECT  149.939 4.288 149.941 9.696 ;
     RECT  143.285 67.328 149.941 68.384 ;
     RECT  149.922 18.432 149.995 19.744 ;
     RECT  149.845 21.12 149.995 21.152 ;
     RECT  149.941 67.328 149.995 68.896 ;
     RECT  149.941 4.288 150.01 10.848 ;
     RECT  149.995 67.84 150.035 68.896 ;
     RECT  149.995 18.432 150.037 19.04 ;
     RECT  149.182 15.296 151.221 15.52 ;
     RECT  150.037 17.856 151.275 19.04 ;
     RECT  150.01 4.288 151.283 9.632 ;
     RECT  151.221 15.296 151.294 16.032 ;
     RECT  151.283 9.472 151.413 9.632 ;
     RECT  151.406 11.264 151.413 11.296 ;
     RECT  151.413 9.472 151.475 11.296 ;
     RECT  151.283 4.288 152.339 7.904 ;
     RECT  148.99 29.568 152.693 29.6 ;
     RECT  152.693 29.568 152.747 30.048 ;
     RECT  152.693 31.936 152.771 31.968 ;
     RECT  152.339 4.288 153.061 7.84 ;
     RECT  151.475 9.472 153.443 10.784 ;
     RECT  149.317 24.768 153.445 24.8 ;
     RECT  151.275 18.432 153.493 19.04 ;
     RECT  153.445 24.768 153.515 25.696 ;
     RECT  152.725 22.208 153.845 22.24 ;
     RECT  153.493 18.368 153.899 19.68 ;
     RECT  151.294 15.296 153.909 15.328 ;
     RECT  153.909 15.168 153.963 15.328 ;
     RECT  153.845 21.312 154.019 22.24 ;
     RECT  150.035 67.84 154.019 68.384 ;
     RECT  152.747 30.016 154.355 30.048 ;
     RECT  153.061 3.328 154.403 7.84 ;
     RECT  154.338 16.832 154.411 16.864 ;
     RECT  153.899 18.368 154.451 19.04 ;
     RECT  153.963 15.168 154.485 15.264 ;
     RECT  154.019 21.312 154.499 21.344 ;
     RECT  153.515 24.768 154.499 24.8 ;
     RECT  154.485 17.024 154.558 17.056 ;
     RECT  154.485 14.016 154.595 15.264 ;
     RECT  154.019 67.84 154.595 67.872 ;
     RECT  154.403 3.328 154.603 7.008 ;
     RECT  154.603 4.608 154.643 7.008 ;
     RECT  154.643 4.736 154.691 7.008 ;
     RECT  153.443 9.472 154.997 10.592 ;
     RECT  154.451 18.368 155.051 18.976 ;
     RECT  154.691 4.864 155.075 7.008 ;
     RECT  154.997 9.472 155.075 10.848 ;
     RECT  154.595 15.04 155.075 15.264 ;
     RECT  155.075 5.44 155.123 7.008 ;
     RECT  155.075 9.472 155.171 9.632 ;
     RECT  155.075 15.232 155.171 15.264 ;
     RECT  155.123 5.44 155.411 5.472 ;
     RECT  155.123 6.848 155.507 7.008 ;
     RECT  155.507 6.848 155.651 6.88 ;
     RECT  155.051 18.816 155.651 18.976 ;
     RECT  155.651 18.944 155.699 18.976 ;
     RECT  155.171 9.472 155.795 9.504 ;
    LAYER M7 ;
     RECT  143.808 2.869 143.84 4.075 ;
     RECT  131.136 3.381 131.168 4.715 ;
     RECT  154.56 3.317 154.592 6.891 ;
     RECT  128.64 4.341 128.672 7.275 ;
     RECT  2.176 2.933 2.208 7.797 ;
     RECT  133.824 6.773 133.856 7.861 ;
     RECT  149.76 4.533 149.792 7.861 ;
     RECT  133.824 7.861 134.304 7.915 ;
     RECT  135.808 6.005 135.84 7.915 ;
     RECT  138.624 3.701 138.656 7.915 ;
     RECT  2.176 7.797 2.4 7.979 ;
     RECT  133.952 7.915 134.304 8.491 ;
     RECT  134.016 8.491 134.304 9.515 ;
     RECT  126.4 7.349 126.432 10.347 ;
     RECT  149.76 7.861 149.984 10.859 ;
     RECT  155.008 9.653 155.04 10.859 ;
     RECT  151.424 10.741 151.456 11.307 ;
     RECT  129.728 9.973 129.76 11.317 ;
     RECT  129.152 11.317 129.76 11.371 ;
     RECT  129.152 11.371 129.184 12.715 ;
     RECT  134.016 9.515 134.048 13.045 ;
     RECT  145.92 10.869 145.952 14.059 ;
     RECT  149.76 10.859 149.792 14.197 ;
     RECT  143.104 11.573 143.136 14.891 ;
     RECT  154.496 14.005 154.528 15.157 ;
     RECT  126.144 11.701 126.176 15.339 ;
     RECT  153.92 15.157 154.528 15.339 ;
     RECT  133.952 13.045 134.048 15.349 ;
     RECT  133.952 15.349 135.008 15.403 ;
     RECT  149.12 14.197 149.792 15.531 ;
     RECT  134.016 15.403 135.008 16.299 ;
     RECT  139.328 15.349 139.36 16.501 ;
     RECT  138.432 16.501 139.36 16.555 ;
     RECT  138.432 16.555 138.464 18.357 ;
     RECT  154.368 15.339 154.528 18.357 ;
     RECT  137.984 18.357 138.464 18.411 ;
     RECT  149.76 15.531 149.792 18.475 ;
     RECT  151.232 15.477 151.264 18.667 ;
     RECT  134.016 16.299 134.048 18.741 ;
     RECT  154.368 18.357 155.04 18.859 ;
     RECT  140.8 18.357 140.832 18.997 ;
     RECT  140.352 18.997 140.832 19.755 ;
     RECT  133.568 18.741 134.048 20.469 ;
     RECT  137.984 18.411 138.016 20.469 ;
     RECT  149.952 19.701 149.984 21.163 ;
     RECT  129.408 19.893 129.44 21.867 ;
     RECT  143.616 19.509 143.648 22.187 ;
     RECT  153.856 19.637 153.888 22.251 ;
     RECT  137.024 20.469 138.016 22.891 ;
     RECT  133.504 20.469 134.048 23.083 ;
     RECT  137.024 22.891 137.056 23.403 ;
     RECT  134.016 23.083 134.048 25.013 ;
     RECT  140.352 19.755 140.384 25.589 ;
     RECT  147.584 18.421 147.616 25.707 ;
     RECT  153.472 24.757 153.504 25.707 ;
     RECT  139.712 25.589 140.384 26.603 ;
     RECT  144.192 23.861 144.224 26.795 ;
     RECT  134.016 25.013 134.496 28.779 ;
     RECT  136.256 28.725 136.288 29.429 ;
     RECT  136.256 29.429 136.416 29.483 ;
     RECT  144.704 28.469 144.736 29.995 ;
     RECT  140.352 26.603 140.384 30.069 ;
     RECT  148.928 28.981 148.96 30.827 ;
     RECT  131.2 22.773 131.232 31.861 ;
     RECT  136.384 29.483 136.416 31.915 ;
     RECT  152.704 29.557 152.736 31.979 ;
     RECT  140.352 30.069 141.344 32.171 ;
     RECT  140.352 32.171 140.384 33.461 ;
     RECT  139.328 33.461 140.384 33.515 ;
     RECT  137.984 29.941 138.016 34.229 ;
     RECT  139.328 33.515 139.36 34.229 ;
     RECT  131.2 31.861 131.936 34.283 ;
     RECT  137.984 34.229 139.36 34.283 ;
     RECT  131.904 34.283 131.936 34.347 ;
     RECT  145.152 33.013 145.184 34.667 ;
     RECT  128.768 31.861 128.8 35.947 ;
     RECT  138.24 34.283 139.36 36.523 ;
     RECT  134.016 28.779 134.048 37.557 ;
     RECT  138.24 36.523 139.168 38.133 ;
     RECT  132.736 37.557 134.048 39.787 ;
     RECT  138.24 38.133 139.296 41.323 ;
     RECT  138.24 41.323 139.168 41.845 ;
     RECT  144.704 35.061 144.736 43.947 ;
     RECT  138.176 41.845 139.168 44.715 ;
     RECT  134.016 39.787 134.048 47.221 ;
     RECT  136.064 45.877 136.096 47.221 ;
     RECT  134.016 47.221 136.096 47.275 ;
     RECT  142.08 45.557 142.112 47.595 ;
     RECT  145.472 45.557 145.504 47.595 ;
     RECT  138.24 44.715 139.168 50.677 ;
     RECT  142.528 47.797 142.56 50.795 ;
     RECT  142.592 50.997 142.624 53.493 ;
     RECT  142.592 53.493 143.328 53.547 ;
     RECT  134.016 47.275 135.136 54.187 ;
     RECT  138.176 50.677 139.168 55.723 ;
     RECT  134.016 54.187 134.048 65.067 ;
     RECT  126.208 55.797 126.24 65.141 ;
     RECT  126.016 65.141 126.24 65.195 ;
     RECT  63.808 15.093 63.84 67.253 ;
     RECT  2.176 7.979 2.208 67.307 ;
     RECT  59.584 2.229 59.616 67.307 ;
     RECT  126.016 65.195 126.048 67.307 ;
     RECT  139.136 55.723 139.168 67.371 ;
     RECT  24.384 10.549 24.416 67.499 ;
     RECT  97.728 2.037 97.76 67.627 ;
     RECT  63.68 67.253 63.84 68.149 ;
     RECT  74.624 68.149 74.656 68.277 ;
     RECT  143.296 53.547 143.328 68.395 ;
     RECT  73.472 68.277 74.656 68.459 ;
     RECT  63.488 68.149 63.84 68.661 ;
     RECT  149.952 67.317 149.984 68.907 ;
     RECT  39.296 68.341 39.328 69.035 ;
     RECT  63.488 68.661 64.288 69.941 ;
     RECT  11.2 68.277 11.232 70.187 ;
     RECT  19.2 67.893 19.232 70.251 ;
     RECT  63.488 69.941 64.416 70.443 ;
     RECT  18.176 70.453 18.208 70.763 ;
     RECT  25.984 69.173 26.016 70.763 ;
     RECT  4.032 68.917 4.064 71.083 ;
     RECT  99.392 69.429 99.424 71.083 ;
     RECT  15.36 69.365 15.392 71.147 ;
     RECT  8.768 69.493 8.8 71.211 ;
     RECT  63.68 70.443 64.416 71.339 ;
     RECT  84.48 70.581 84.512 71.403 ;
     RECT  87.296 70.453 87.328 71.403 ;
     RECT  30.144 69.493 30.176 71.531 ;
     RECT  21.696 67.765 21.728 71.595 ;
     RECT  68.8 68.917 68.832 71.851 ;
     RECT  73.472 68.459 73.504 71.851 ;
     RECT  93.056 68.149 93.088 71.851 ;
     RECT  103.872 67.893 103.904 71.851 ;
     RECT  91.52 69.493 91.552 72.171 ;
     RECT  50.496 71.477 50.528 72.309 ;
     RECT  55.808 71.029 55.84 72.309 ;
     RECT  55.552 72.309 55.84 72.363 ;
     RECT  89.6 72.117 89.632 72.821 ;
     RECT  50.496 72.309 50.656 72.885 ;
     RECT  76.544 70.965 76.576 73.195 ;
     RECT  33.856 71.477 33.888 73.397 ;
     RECT  8.576 72.821 8.608 73.515 ;
     RECT  24.768 71.029 24.8 73.515 ;
     RECT  39.808 71.477 39.84 73.707 ;
     RECT  45.056 67.829 45.088 73.771 ;
     RECT  5.376 72.885 5.408 74.027 ;
     RECT  58.688 67.701 58.72 74.027 ;
     RECT  72.448 72.309 72.48 74.357 ;
     RECT  74.688 72.693 74.72 74.539 ;
     RECT  71.232 74.357 72.48 74.613 ;
     RECT  71.104 74.613 72.48 74.667 ;
     RECT  33.216 73.397 33.888 74.731 ;
     RECT  35.648 71.221 35.68 74.795 ;
     RECT  55.552 72.363 55.584 74.795 ;
     RECT  63.68 71.339 63.84 74.869 ;
     RECT  14.208 71.861 14.24 75.061 ;
     RECT  49.536 72.885 50.656 75.307 ;
     RECT  92.672 74.421 92.704 75.307 ;
     RECT  98.112 73.909 98.144 75.307 ;
     RECT  83.136 70.645 83.168 75.883 ;
     RECT  71.104 74.667 71.264 76.459 ;
     RECT  89.6 72.821 89.696 76.459 ;
     RECT  28.864 73.909 28.896 76.715 ;
     RECT  14.208 75.061 14.816 77.099 ;
     RECT  33.856 74.731 33.888 77.493 ;
     RECT  46.144 77.173 46.176 77.493 ;
     RECT  63.68 74.869 64.096 77.493 ;
     RECT  68.096 74.357 68.128 77.547 ;
     RECT  89.6 76.459 89.632 77.941 ;
     RECT  96.896 76.917 96.928 77.995 ;
     RECT  8.256 76.853 8.288 78.059 ;
     RECT  45.504 77.493 46.176 78.059 ;
     RECT  50.624 75.307 50.656 78.069 ;
     RECT  18.24 76.597 18.272 78.123 ;
     RECT  25.472 77.941 25.504 78.325 ;
     RECT  25.472 78.325 25.824 78.389 ;
     RECT  45.504 78.059 46.048 78.443 ;
     RECT  25.472 78.389 25.888 78.635 ;
     RECT  31.872 76.789 31.904 78.699 ;
     RECT  55.872 76.917 55.904 78.699 ;
     RECT  5.696 77.429 5.728 79.275 ;
     RECT  16.896 77.493 16.928 79.275 ;
     RECT  25.472 78.635 25.696 79.275 ;
     RECT  46.016 78.443 46.048 79.275 ;
     RECT  50.112 78.069 50.656 79.467 ;
     RECT  29.824 77.173 29.856 79.851 ;
     RECT  89.6 77.941 90.016 80.043 ;
     RECT  85.696 77.941 85.728 80.235 ;
     RECT  33.792 77.493 33.888 80.373 ;
     RECT  33.792 80.373 34.208 80.501 ;
     RECT  71.104 76.459 71.136 80.629 ;
     RECT  38.72 77.173 38.752 80.693 ;
     RECT  38.72 80.693 39.072 80.747 ;
     RECT  25.472 79.275 25.504 80.885 ;
     RECT  25.472 80.885 25.632 80.939 ;
     RECT  11.328 80.245 11.36 81.259 ;
     RECT  33.664 80.501 34.208 81.579 ;
     RECT  48.704 79.413 48.736 81.835 ;
     RECT  89.6 80.043 89.632 82.155 ;
     RECT  33.664 81.579 33.696 82.411 ;
     RECT  14.208 77.099 14.24 82.475 ;
     RECT  25.6 80.939 25.632 82.731 ;
     RECT  71.104 80.629 71.904 82.731 ;
     RECT  79.168 81.461 79.2 82.731 ;
     RECT  91.84 82.549 91.872 82.859 ;
     RECT  71.104 82.731 71.136 83.573 ;
     RECT  50.624 79.467 50.656 83.755 ;
     RECT  70.656 83.573 71.136 83.755 ;
     RECT  62.464 77.493 64.096 83.819 ;
     RECT  29.632 80.885 29.664 84.075 ;
     RECT  39.04 80.747 39.072 84.075 ;
     RECT  47.68 83.381 47.712 84.267 ;
     RECT  62.464 83.819 62.496 84.651 ;
     RECT  22.528 80.885 22.56 84.843 ;
     RECT  70.656 83.755 70.688 84.907 ;
     RECT  43.264 82.549 43.296 84.971 ;
     RECT  58.752 83.125 58.784 85.163 ;
     RECT  18.496 83.381 18.528 85.355 ;
     RECT  54.656 85.237 54.688 87.275 ;
  END
END ot_qwen_embed_scale_bank_parent
END LIBRARY
